VERSION 5.8 ;
BUSBITCHARS "[]" ;
DIVIDERCHAR "/" ;
UNITS
    DATABASE MICRONS 1000 ;
END UNITS

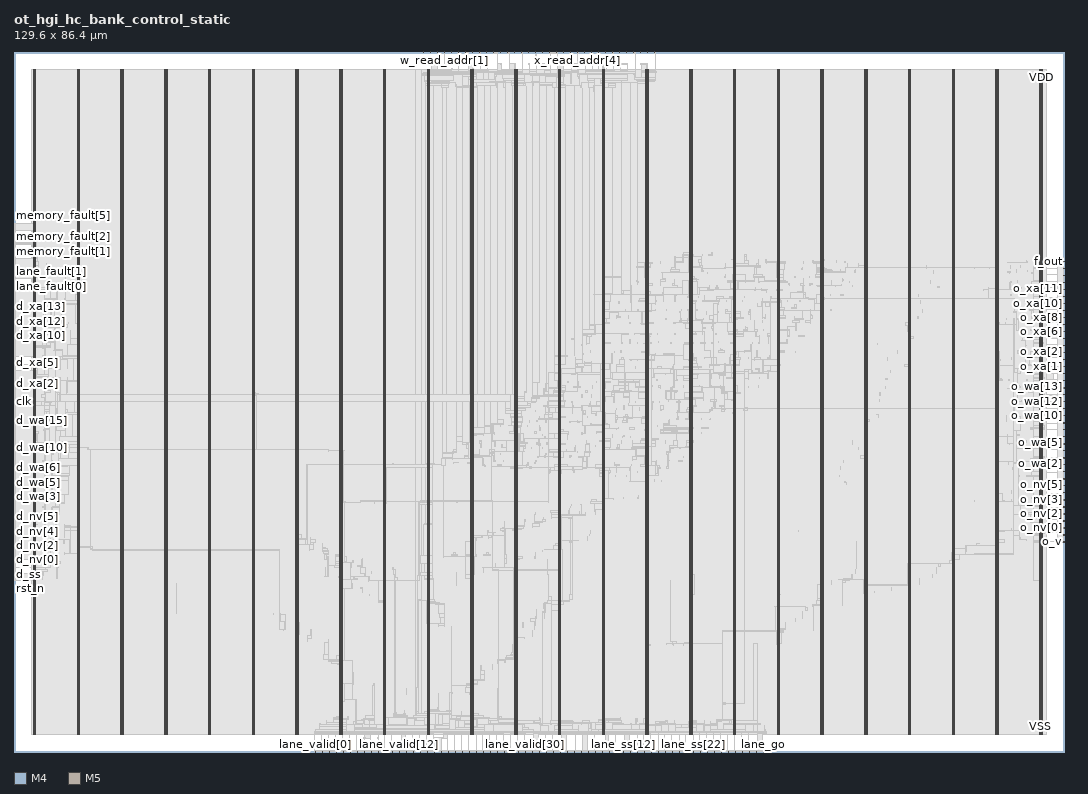
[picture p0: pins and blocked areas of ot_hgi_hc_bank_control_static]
MACRO ot_hgi_hc_bank_control_static
  FOREIGN ot_hgi_hc_bank_control_static 0 0 ;
  CLASS BLOCK ;
  SIZE 129.6 BY 86.4 ;
  PIN clk
    DIRECTION INPUT ;
    USE SIGNAL ;
    PORT
      LAYER M4 ;
        RECT  0 43.2 0.084 43.224 ;
    END
  END clk
  PIN d_nv[0]
    DIRECTION INPUT ;
    USE SIGNAL ;
    PORT
      LAYER M4 ;
        RECT  0 23.76 0.084 23.784 ;
    END
  END d_nv[0]
  PIN d_nv[1]
    DIRECTION INPUT ;
    USE SIGNAL ;
    PORT
      LAYER M4 ;
        RECT  0 24.624 0.084 24.648 ;
    END
  END d_nv[1]
  PIN d_nv[2]
    DIRECTION INPUT ;
    USE SIGNAL ;
    PORT
      LAYER M4 ;
        RECT  0 25.488 0.084 25.512 ;
    END
  END d_nv[2]
  PIN d_nv[3]
    DIRECTION INPUT ;
    USE SIGNAL ;
    PORT
      LAYER M4 ;
        RECT  0 26.352 0.084 26.376 ;
    END
  END d_nv[3]
  PIN d_nv[4]
    DIRECTION INPUT ;
    USE SIGNAL ;
    PORT
      LAYER M4 ;
        RECT  0 27.216 0.084 27.24 ;
    END
  END d_nv[4]
  PIN d_nv[5]
    DIRECTION INPUT ;
    USE SIGNAL ;
    PORT
      LAYER M4 ;
        RECT  0 28.08 0.084 28.104 ;
    END
  END d_nv[5]
  PIN d_ss
    DIRECTION INPUT ;
    USE SIGNAL ;
    PORT
      LAYER M4 ;
        RECT  0 22.896 0.084 22.92 ;
    END
  END d_ss
  PIN d_v
    DIRECTION INPUT ;
    USE SIGNAL ;
    PORT
      LAYER M4 ;
        RECT  0 22.032 0.084 22.056 ;
    END
  END d_v
  PIN d_wa[0]
    DIRECTION INPUT ;
    USE SIGNAL ;
    PORT
      LAYER M4 ;
        RECT  0 28.944 0.084 28.968 ;
    END
  END d_wa[0]
  PIN d_wa[10]
    DIRECTION INPUT ;
    USE SIGNAL ;
    PORT
      LAYER M4 ;
        RECT  0 37.584 0.084 37.608 ;
    END
  END d_wa[10]
  PIN d_wa[11]
    DIRECTION INPUT ;
    USE SIGNAL ;
    PORT
      LAYER M4 ;
        RECT  0 38.448 0.084 38.472 ;
    END
  END d_wa[11]
  PIN d_wa[12]
    DIRECTION INPUT ;
    USE SIGNAL ;
    PORT
      LAYER M4 ;
        RECT  0 39.312 0.084 39.336 ;
    END
  END d_wa[12]
  PIN d_wa[13]
    DIRECTION INPUT ;
    USE SIGNAL ;
    PORT
      LAYER M4 ;
        RECT  0 40.176 0.084 40.2 ;
    END
  END d_wa[13]
  PIN d_wa[14]
    DIRECTION INPUT ;
    USE SIGNAL ;
    PORT
      LAYER M4 ;
        RECT  0 41.04 0.084 41.064 ;
    END
  END d_wa[14]
  PIN d_wa[15]
    DIRECTION INPUT ;
    USE SIGNAL ;
    PORT
      LAYER M4 ;
        RECT  0 41.904 0.084 41.928 ;
    END
  END d_wa[15]
  PIN d_wa[1]
    DIRECTION INPUT ;
    USE SIGNAL ;
    PORT
      LAYER M4 ;
        RECT  0 29.808 0.084 29.832 ;
    END
  END d_wa[1]
  PIN d_wa[2]
    DIRECTION INPUT ;
    USE SIGNAL ;
    PORT
      LAYER M4 ;
        RECT  0 30.672 0.084 30.696 ;
    END
  END d_wa[2]
  PIN d_wa[3]
    DIRECTION INPUT ;
    USE SIGNAL ;
    PORT
      LAYER M4 ;
        RECT  0 31.536 0.084 31.56 ;
    END
  END d_wa[3]
  PIN d_wa[4]
    DIRECTION INPUT ;
    USE SIGNAL ;
    PORT
      LAYER M4 ;
        RECT  0 32.4 0.084 32.424 ;
    END
  END d_wa[4]
  PIN d_wa[5]
    DIRECTION INPUT ;
    USE SIGNAL ;
    PORT
      LAYER M4 ;
        RECT  0 33.264 0.084 33.288 ;
    END
  END d_wa[5]
  PIN d_wa[6]
    DIRECTION INPUT ;
    USE SIGNAL ;
    PORT
      LAYER M4 ;
        RECT  0 34.128 0.084 34.152 ;
    END
  END d_wa[6]
  PIN d_wa[7]
    DIRECTION INPUT ;
    USE SIGNAL ;
    PORT
      LAYER M4 ;
        RECT  0 34.992 0.084 35.016 ;
    END
  END d_wa[7]
  PIN d_wa[8]
    DIRECTION INPUT ;
    USE SIGNAL ;
    PORT
      LAYER M4 ;
        RECT  0 35.856 0.084 35.88 ;
    END
  END d_wa[8]
  PIN d_wa[9]
    DIRECTION INPUT ;
    USE SIGNAL ;
    PORT
      LAYER M4 ;
        RECT  0 36.72 0.084 36.744 ;
    END
  END d_wa[9]
  PIN d_xa[0]
    DIRECTION INPUT ;
    USE SIGNAL ;
    PORT
      LAYER M4 ;
        RECT  0 42.768 0.084 42.792 ;
    END
  END d_xa[0]
  PIN d_xa[10]
    DIRECTION INPUT ;
    USE SIGNAL ;
    PORT
      LAYER M4 ;
        RECT  0 51.408 0.084 51.432 ;
    END
  END d_xa[10]
  PIN d_xa[11]
    DIRECTION INPUT ;
    USE SIGNAL ;
    PORT
      LAYER M4 ;
        RECT  0 52.272 0.084 52.296 ;
    END
  END d_xa[11]
  PIN d_xa[12]
    DIRECTION INPUT ;
    USE SIGNAL ;
    PORT
      LAYER M4 ;
        RECT  0 53.136 0.084 53.16 ;
    END
  END d_xa[12]
  PIN d_xa[13]
    DIRECTION INPUT ;
    USE SIGNAL ;
    PORT
      LAYER M4 ;
        RECT  0 54 0.084 54.024 ;
    END
  END d_xa[13]
  PIN d_xa[14]
    DIRECTION INPUT ;
    USE SIGNAL ;
    PORT
      LAYER M4 ;
        RECT  0 54.864 0.084 54.888 ;
    END
  END d_xa[14]
  PIN d_xa[15]
    DIRECTION INPUT ;
    USE SIGNAL ;
    PORT
      LAYER M4 ;
        RECT  0 55.728 0.084 55.752 ;
    END
  END d_xa[15]
  PIN d_xa[1]
    DIRECTION INPUT ;
    USE SIGNAL ;
    PORT
      LAYER M4 ;
        RECT  0 43.632 0.084 43.656 ;
    END
  END d_xa[1]
  PIN d_xa[2]
    DIRECTION INPUT ;
    USE SIGNAL ;
    PORT
      LAYER M4 ;
        RECT  0 44.496 0.084 44.52 ;
    END
  END d_xa[2]
  PIN d_xa[3]
    DIRECTION INPUT ;
    USE SIGNAL ;
    PORT
      LAYER M4 ;
        RECT  0 45.36 0.084 45.384 ;
    END
  END d_xa[3]
  PIN d_xa[4]
    DIRECTION INPUT ;
    USE SIGNAL ;
    PORT
      LAYER M4 ;
        RECT  0 46.224 0.084 46.248 ;
    END
  END d_xa[4]
  PIN d_xa[5]
    DIRECTION INPUT ;
    USE SIGNAL ;
    PORT
      LAYER M4 ;
        RECT  0 47.088 0.084 47.112 ;
    END
  END d_xa[5]
  PIN d_xa[6]
    DIRECTION INPUT ;
    USE SIGNAL ;
    PORT
      LAYER M4 ;
        RECT  0 47.952 0.084 47.976 ;
    END
  END d_xa[6]
  PIN d_xa[7]
    DIRECTION INPUT ;
    USE SIGNAL ;
    PORT
      LAYER M4 ;
        RECT  0 48.816 0.084 48.84 ;
    END
  END d_xa[7]
  PIN d_xa[8]
    DIRECTION INPUT ;
    USE SIGNAL ;
    PORT
      LAYER M4 ;
        RECT  0 49.68 0.084 49.704 ;
    END
  END d_xa[8]
  PIN d_xa[9]
    DIRECTION INPUT ;
    USE SIGNAL ;
    PORT
      LAYER M4 ;
        RECT  0 50.544 0.084 50.568 ;
    END
  END d_xa[9]
  PIN f_in
    DIRECTION INPUT ;
    USE SIGNAL ;
    PORT
      LAYER M4 ;
        RECT  0 56.592 0.084 56.616 ;
    END
  END f_in
  PIN f_out
    DIRECTION OUTPUT ;
    USE SIGNAL ;
    PORT
      LAYER M4 ;
        RECT  129.516 60.48 129.6 60.504 ;
    END
  END f_out
  PIN lane_fault[0]
    DIRECTION INPUT ;
    USE SIGNAL ;
    PORT
      LAYER M4 ;
        RECT  0 57.456 0.084 57.48 ;
    END
  END lane_fault[0]
  PIN lane_fault[1]
    DIRECTION INPUT ;
    USE SIGNAL ;
    PORT
      LAYER M4 ;
        RECT  0 58.32 0.084 58.344 ;
    END
  END lane_fault[1]
  PIN lane_fault[2]
    DIRECTION INPUT ;
    USE SIGNAL ;
    PORT
      LAYER M4 ;
        RECT  0 59.184 0.084 59.208 ;
    END
  END lane_fault[2]
  PIN lane_fault[3]
    DIRECTION INPUT ;
    USE SIGNAL ;
    PORT
      LAYER M4 ;
        RECT  0 60.048 0.084 60.072 ;
    END
  END lane_fault[3]
  PIN lane_go
    DIRECTION OUTPUT ;
    USE SIGNAL ;
    PORT
      LAYER M5 ;
        RECT  92.448 0 92.472 0.084 ;
    END
  END lane_go
  PIN lane_ss[0]
    DIRECTION OUTPUT ;
    USE SIGNAL ;
    PORT
      LAYER M5 ;
        RECT  64.8 0 64.824 0.084 ;
    END
  END lane_ss[0]
  PIN lane_ss[10]
    DIRECTION OUTPUT ;
    USE SIGNAL ;
    PORT
      LAYER M5 ;
        RECT  73.44 0 73.464 0.084 ;
    END
  END lane_ss[10]
  PIN lane_ss[11]
    DIRECTION OUTPUT ;
    USE SIGNAL ;
    PORT
      LAYER M5 ;
        RECT  74.304 0 74.328 0.084 ;
    END
  END lane_ss[11]
  PIN lane_ss[12]
    DIRECTION OUTPUT ;
    USE SIGNAL ;
    PORT
      LAYER M5 ;
        RECT  75.168 0 75.192 0.084 ;
    END
  END lane_ss[12]
  PIN lane_ss[13]
    DIRECTION OUTPUT ;
    USE SIGNAL ;
    PORT
      LAYER M5 ;
        RECT  76.032 0 76.056 0.084 ;
    END
  END lane_ss[13]
  PIN lane_ss[14]
    DIRECTION OUTPUT ;
    USE SIGNAL ;
    PORT
      LAYER M5 ;
        RECT  76.896 0 76.92 0.084 ;
    END
  END lane_ss[14]
  PIN lane_ss[15]
    DIRECTION OUTPUT ;
    USE SIGNAL ;
    PORT
      LAYER M5 ;
        RECT  77.76 0 77.784 0.084 ;
    END
  END lane_ss[15]
  PIN lane_ss[16]
    DIRECTION OUTPUT ;
    USE SIGNAL ;
    PORT
      LAYER M5 ;
        RECT  78.624 0 78.648 0.084 ;
    END
  END lane_ss[16]
  PIN lane_ss[17]
    DIRECTION OUTPUT ;
    USE SIGNAL ;
    PORT
      LAYER M5 ;
        RECT  79.488 0 79.512 0.084 ;
    END
  END lane_ss[17]
  PIN lane_ss[18]
    DIRECTION OUTPUT ;
    USE SIGNAL ;
    PORT
      LAYER M5 ;
        RECT  80.352 0 80.376 0.084 ;
    END
  END lane_ss[18]
  PIN lane_ss[19]
    DIRECTION OUTPUT ;
    USE SIGNAL ;
    PORT
      LAYER M5 ;
        RECT  81.216 0 81.24 0.084 ;
    END
  END lane_ss[19]
  PIN lane_ss[1]
    DIRECTION OUTPUT ;
    USE SIGNAL ;
    PORT
      LAYER M5 ;
        RECT  65.664 0 65.688 0.084 ;
    END
  END lane_ss[1]
  PIN lane_ss[20]
    DIRECTION OUTPUT ;
    USE SIGNAL ;
    PORT
      LAYER M5 ;
        RECT  82.08 0 82.104 0.084 ;
    END
  END lane_ss[20]
  PIN lane_ss[21]
    DIRECTION OUTPUT ;
    USE SIGNAL ;
    PORT
      LAYER M5 ;
        RECT  82.944 0 82.968 0.084 ;
    END
  END lane_ss[21]
  PIN lane_ss[22]
    DIRECTION OUTPUT ;
    USE SIGNAL ;
    PORT
      LAYER M5 ;
        RECT  83.808 0 83.832 0.084 ;
    END
  END lane_ss[22]
  PIN lane_ss[23]
    DIRECTION OUTPUT ;
    USE SIGNAL ;
    PORT
      LAYER M5 ;
        RECT  84.672 0 84.696 0.084 ;
    END
  END lane_ss[23]
  PIN lane_ss[24]
    DIRECTION OUTPUT ;
    USE SIGNAL ;
    PORT
      LAYER M5 ;
        RECT  85.536 0 85.56 0.084 ;
    END
  END lane_ss[24]
  PIN lane_ss[25]
    DIRECTION OUTPUT ;
    USE SIGNAL ;
    PORT
      LAYER M5 ;
        RECT  86.4 0 86.424 0.084 ;
    END
  END lane_ss[25]
  PIN lane_ss[26]
    DIRECTION OUTPUT ;
    USE SIGNAL ;
    PORT
      LAYER M5 ;
        RECT  87.264 0 87.288 0.084 ;
    END
  END lane_ss[26]
  PIN lane_ss[27]
    DIRECTION OUTPUT ;
    USE SIGNAL ;
    PORT
      LAYER M5 ;
        RECT  88.128 0 88.152 0.084 ;
    END
  END lane_ss[27]
  PIN lane_ss[28]
    DIRECTION OUTPUT ;
    USE SIGNAL ;
    PORT
      LAYER M5 ;
        RECT  88.992 0 89.016 0.084 ;
    END
  END lane_ss[28]
  PIN lane_ss[29]
    DIRECTION OUTPUT ;
    USE SIGNAL ;
    PORT
      LAYER M5 ;
        RECT  89.856 0 89.88 0.084 ;
    END
  END lane_ss[29]
  PIN lane_ss[2]
    DIRECTION OUTPUT ;
    USE SIGNAL ;
    PORT
      LAYER M5 ;
        RECT  66.528 0 66.552 0.084 ;
    END
  END lane_ss[2]
  PIN lane_ss[30]
    DIRECTION OUTPUT ;
    USE SIGNAL ;
    PORT
      LAYER M5 ;
        RECT  90.72 0 90.744 0.084 ;
    END
  END lane_ss[30]
  PIN lane_ss[31]
    DIRECTION OUTPUT ;
    USE SIGNAL ;
    PORT
      LAYER M5 ;
        RECT  91.584 0 91.608 0.084 ;
    END
  END lane_ss[31]
  PIN lane_ss[3]
    DIRECTION OUTPUT ;
    USE SIGNAL ;
    PORT
      LAYER M5 ;
        RECT  67.392 0 67.416 0.084 ;
    END
  END lane_ss[3]
  PIN lane_ss[4]
    DIRECTION OUTPUT ;
    USE SIGNAL ;
    PORT
      LAYER M5 ;
        RECT  68.256 0 68.28 0.084 ;
    END
  END lane_ss[4]
  PIN lane_ss[5]
    DIRECTION OUTPUT ;
    USE SIGNAL ;
    PORT
      LAYER M5 ;
        RECT  69.12 0 69.144 0.084 ;
    END
  END lane_ss[5]
  PIN lane_ss[6]
    DIRECTION OUTPUT ;
    USE SIGNAL ;
    PORT
      LAYER M5 ;
        RECT  69.984 0 70.008 0.084 ;
    END
  END lane_ss[6]
  PIN lane_ss[7]
    DIRECTION OUTPUT ;
    USE SIGNAL ;
    PORT
      LAYER M5 ;
        RECT  70.848 0 70.872 0.084 ;
    END
  END lane_ss[7]
  PIN lane_ss[8]
    DIRECTION OUTPUT ;
    USE SIGNAL ;
    PORT
      LAYER M5 ;
        RECT  71.712 0 71.736 0.084 ;
    END
  END lane_ss[8]
  PIN lane_ss[9]
    DIRECTION OUTPUT ;
    USE SIGNAL ;
    PORT
      LAYER M5 ;
        RECT  72.576 0 72.6 0.084 ;
    END
  END lane_ss[9]
  PIN lane_valid[0]
    DIRECTION OUTPUT ;
    USE SIGNAL ;
    PORT
      LAYER M5 ;
        RECT  37.152 0 37.176 0.084 ;
    END
  END lane_valid[0]
  PIN lane_valid[10]
    DIRECTION OUTPUT ;
    USE SIGNAL ;
    PORT
      LAYER M5 ;
        RECT  45.792 0 45.816 0.084 ;
    END
  END lane_valid[10]
  PIN lane_valid[11]
    DIRECTION OUTPUT ;
    USE SIGNAL ;
    PORT
      LAYER M5 ;
        RECT  46.656 0 46.68 0.084 ;
    END
  END lane_valid[11]
  PIN lane_valid[12]
    DIRECTION OUTPUT ;
    USE SIGNAL ;
    PORT
      LAYER M5 ;
        RECT  47.52 0 47.544 0.084 ;
    END
  END lane_valid[12]
  PIN lane_valid[13]
    DIRECTION OUTPUT ;
    USE SIGNAL ;
    PORT
      LAYER M5 ;
        RECT  48.384 0 48.408 0.084 ;
    END
  END lane_valid[13]
  PIN lane_valid[14]
    DIRECTION OUTPUT ;
    USE SIGNAL ;
    PORT
      LAYER M5 ;
        RECT  49.248 0 49.272 0.084 ;
    END
  END lane_valid[14]
  PIN lane_valid[15]
    DIRECTION OUTPUT ;
    USE SIGNAL ;
    PORT
      LAYER M5 ;
        RECT  50.112 0 50.136 0.084 ;
    END
  END lane_valid[15]
  PIN lane_valid[16]
    DIRECTION OUTPUT ;
    USE SIGNAL ;
    PORT
      LAYER M5 ;
        RECT  50.976 0 51 0.084 ;
    END
  END lane_valid[16]
  PIN lane_valid[17]
    DIRECTION OUTPUT ;
    USE SIGNAL ;
    PORT
      LAYER M5 ;
        RECT  51.84 0 51.864 0.084 ;
    END
  END lane_valid[17]
  PIN lane_valid[18]
    DIRECTION OUTPUT ;
    USE SIGNAL ;
    PORT
      LAYER M5 ;
        RECT  52.704 0 52.728 0.084 ;
    END
  END lane_valid[18]
  PIN lane_valid[19]
    DIRECTION OUTPUT ;
    USE SIGNAL ;
    PORT
      LAYER M5 ;
        RECT  53.568 0 53.592 0.084 ;
    END
  END lane_valid[19]
  PIN lane_valid[1]
    DIRECTION OUTPUT ;
    USE SIGNAL ;
    PORT
      LAYER M5 ;
        RECT  38.016 0 38.04 0.084 ;
    END
  END lane_valid[1]
  PIN lane_valid[20]
    DIRECTION OUTPUT ;
    USE SIGNAL ;
    PORT
      LAYER M5 ;
        RECT  54.432 0 54.456 0.084 ;
    END
  END lane_valid[20]
  PIN lane_valid[21]
    DIRECTION OUTPUT ;
    USE SIGNAL ;
    PORT
      LAYER M5 ;
        RECT  55.296 0 55.32 0.084 ;
    END
  END lane_valid[21]
  PIN lane_valid[22]
    DIRECTION OUTPUT ;
    USE SIGNAL ;
    PORT
      LAYER M5 ;
        RECT  56.16 0 56.184 0.084 ;
    END
  END lane_valid[22]
  PIN lane_valid[23]
    DIRECTION OUTPUT ;
    USE SIGNAL ;
    PORT
      LAYER M5 ;
        RECT  57.024 0 57.048 0.084 ;
    END
  END lane_valid[23]
  PIN lane_valid[24]
    DIRECTION OUTPUT ;
    USE SIGNAL ;
    PORT
      LAYER M5 ;
        RECT  57.888 0 57.912 0.084 ;
    END
  END lane_valid[24]
  PIN lane_valid[25]
    DIRECTION OUTPUT ;
    USE SIGNAL ;
    PORT
      LAYER M5 ;
        RECT  58.752 0 58.776 0.084 ;
    END
  END lane_valid[25]
  PIN lane_valid[26]
    DIRECTION OUTPUT ;
    USE SIGNAL ;
    PORT
      LAYER M5 ;
        RECT  59.616 0 59.64 0.084 ;
    END
  END lane_valid[26]
  PIN lane_valid[27]
    DIRECTION OUTPUT ;
    USE SIGNAL ;
    PORT
      LAYER M5 ;
        RECT  60.48 0 60.504 0.084 ;
    END
  END lane_valid[27]
  PIN lane_valid[28]
    DIRECTION OUTPUT ;
    USE SIGNAL ;
    PORT
      LAYER M5 ;
        RECT  61.344 0 61.368 0.084 ;
    END
  END lane_valid[28]
  PIN lane_valid[29]
    DIRECTION OUTPUT ;
    USE SIGNAL ;
    PORT
      LAYER M5 ;
        RECT  62.208 0 62.232 0.084 ;
    END
  END lane_valid[29]
  PIN lane_valid[2]
    DIRECTION OUTPUT ;
    USE SIGNAL ;
    PORT
      LAYER M5 ;
        RECT  38.88 0 38.904 0.084 ;
    END
  END lane_valid[2]
  PIN lane_valid[30]
    DIRECTION OUTPUT ;
    USE SIGNAL ;
    PORT
      LAYER M5 ;
        RECT  63.072 0 63.096 0.084 ;
    END
  END lane_valid[30]
  PIN lane_valid[31]
    DIRECTION OUTPUT ;
    USE SIGNAL ;
    PORT
      LAYER M5 ;
        RECT  63.936 0 63.96 0.084 ;
    END
  END lane_valid[31]
  PIN lane_valid[3]
    DIRECTION OUTPUT ;
    USE SIGNAL ;
    PORT
      LAYER M5 ;
        RECT  39.744 0 39.768 0.084 ;
    END
  END lane_valid[3]
  PIN lane_valid[4]
    DIRECTION OUTPUT ;
    USE SIGNAL ;
    PORT
      LAYER M5 ;
        RECT  40.608 0 40.632 0.084 ;
    END
  END lane_valid[4]
  PIN lane_valid[5]
    DIRECTION OUTPUT ;
    USE SIGNAL ;
    PORT
      LAYER M5 ;
        RECT  41.472 0 41.496 0.084 ;
    END
  END lane_valid[5]
  PIN lane_valid[6]
    DIRECTION OUTPUT ;
    USE SIGNAL ;
    PORT
      LAYER M5 ;
        RECT  42.336 0 42.36 0.084 ;
    END
  END lane_valid[6]
  PIN lane_valid[7]
    DIRECTION OUTPUT ;
    USE SIGNAL ;
    PORT
      LAYER M5 ;
        RECT  43.2 0 43.224 0.084 ;
    END
  END lane_valid[7]
  PIN lane_valid[8]
    DIRECTION OUTPUT ;
    USE SIGNAL ;
    PORT
      LAYER M5 ;
        RECT  44.064 0 44.088 0.084 ;
    END
  END lane_valid[8]
  PIN lane_valid[9]
    DIRECTION OUTPUT ;
    USE SIGNAL ;
    PORT
      LAYER M5 ;
        RECT  44.928 0 44.952 0.084 ;
    END
  END lane_valid[9]
  PIN memory_fault[0]
    DIRECTION INPUT ;
    USE SIGNAL ;
    PORT
      LAYER M4 ;
        RECT  0 60.912 0.084 60.936 ;
    END
  END memory_fault[0]
  PIN memory_fault[1]
    DIRECTION INPUT ;
    USE SIGNAL ;
    PORT
      LAYER M4 ;
        RECT  0 61.776 0.084 61.8 ;
    END
  END memory_fault[1]
  PIN memory_fault[2]
    DIRECTION INPUT ;
    USE SIGNAL ;
    PORT
      LAYER M4 ;
        RECT  0 62.64 0.084 62.664 ;
    END
  END memory_fault[2]
  PIN memory_fault[3]
    DIRECTION INPUT ;
    USE SIGNAL ;
    PORT
      LAYER M4 ;
        RECT  0 63.504 0.084 63.528 ;
    END
  END memory_fault[3]
  PIN memory_fault[4]
    DIRECTION INPUT ;
    USE SIGNAL ;
    PORT
      LAYER M4 ;
        RECT  0 64.368 0.084 64.392 ;
    END
  END memory_fault[4]
  PIN memory_fault[5]
    DIRECTION INPUT ;
    USE SIGNAL ;
    PORT
      LAYER M4 ;
        RECT  0 65.232 0.084 65.256 ;
    END
  END memory_fault[5]
  PIN o_nv[0]
    DIRECTION OUTPUT ;
    USE SIGNAL ;
    PORT
      LAYER M4 ;
        RECT  129.516 27.648 129.6 27.672 ;
    END
  END o_nv[0]
  PIN o_nv[1]
    DIRECTION OUTPUT ;
    USE SIGNAL ;
    PORT
      LAYER M4 ;
        RECT  129.516 28.512 129.6 28.536 ;
    END
  END o_nv[1]
  PIN o_nv[2]
    DIRECTION OUTPUT ;
    USE SIGNAL ;
    PORT
      LAYER M4 ;
        RECT  129.516 29.376 129.6 29.4 ;
    END
  END o_nv[2]
  PIN o_nv[3]
    DIRECTION OUTPUT ;
    USE SIGNAL ;
    PORT
      LAYER M4 ;
        RECT  129.516 30.24 129.6 30.264 ;
    END
  END o_nv[3]
  PIN o_nv[4]
    DIRECTION OUTPUT ;
    USE SIGNAL ;
    PORT
      LAYER M4 ;
        RECT  129.516 31.104 129.6 31.128 ;
    END
  END o_nv[4]
  PIN o_nv[5]
    DIRECTION OUTPUT ;
    USE SIGNAL ;
    PORT
      LAYER M4 ;
        RECT  129.516 31.968 129.6 31.992 ;
    END
  END o_nv[5]
  PIN o_ss
    DIRECTION OUTPUT ;
    USE SIGNAL ;
    PORT
      LAYER M4 ;
        RECT  129.516 26.784 129.6 26.808 ;
    END
  END o_ss
  PIN o_v
    DIRECTION OUTPUT ;
    USE SIGNAL ;
    PORT
      LAYER M4 ;
        RECT  129.516 25.92 129.6 25.944 ;
    END
  END o_v
  PIN o_wa[0]
    DIRECTION OUTPUT ;
    USE SIGNAL ;
    PORT
      LAYER M4 ;
        RECT  129.516 32.832 129.6 32.856 ;
    END
  END o_wa[0]
  PIN o_wa[10]
    DIRECTION OUTPUT ;
    USE SIGNAL ;
    PORT
      LAYER M4 ;
        RECT  129.516 41.472 129.6 41.496 ;
    END
  END o_wa[10]
  PIN o_wa[11]
    DIRECTION OUTPUT ;
    USE SIGNAL ;
    PORT
      LAYER M4 ;
        RECT  129.516 42.336 129.6 42.36 ;
    END
  END o_wa[11]
  PIN o_wa[12]
    DIRECTION OUTPUT ;
    USE SIGNAL ;
    PORT
      LAYER M4 ;
        RECT  129.516 43.2 129.6 43.224 ;
    END
  END o_wa[12]
  PIN o_wa[13]
    DIRECTION OUTPUT ;
    USE SIGNAL ;
    PORT
      LAYER M4 ;
        RECT  129.516 44.064 129.6 44.088 ;
    END
  END o_wa[13]
  PIN o_wa[14]
    DIRECTION OUTPUT ;
    USE SIGNAL ;
    PORT
      LAYER M4 ;
        RECT  129.516 44.928 129.6 44.952 ;
    END
  END o_wa[14]
  PIN o_wa[15]
    DIRECTION OUTPUT ;
    USE SIGNAL ;
    PORT
      LAYER M4 ;
        RECT  129.516 45.792 129.6 45.816 ;
    END
  END o_wa[15]
  PIN o_wa[1]
    DIRECTION OUTPUT ;
    USE SIGNAL ;
    PORT
      LAYER M4 ;
        RECT  129.516 33.696 129.6 33.72 ;
    END
  END o_wa[1]
  PIN o_wa[2]
    DIRECTION OUTPUT ;
    USE SIGNAL ;
    PORT
      LAYER M4 ;
        RECT  129.516 34.56 129.6 34.584 ;
    END
  END o_wa[2]
  PIN o_wa[3]
    DIRECTION OUTPUT ;
    USE SIGNAL ;
    PORT
      LAYER M4 ;
        RECT  129.516 35.424 129.6 35.448 ;
    END
  END o_wa[3]
  PIN o_wa[4]
    DIRECTION OUTPUT ;
    USE SIGNAL ;
    PORT
      LAYER M4 ;
        RECT  129.516 36.288 129.6 36.312 ;
    END
  END o_wa[4]
  PIN o_wa[5]
    DIRECTION OUTPUT ;
    USE SIGNAL ;
    PORT
      LAYER M4 ;
        RECT  129.516 37.152 129.6 37.176 ;
    END
  END o_wa[5]
  PIN o_wa[6]
    DIRECTION OUTPUT ;
    USE SIGNAL ;
    PORT
      LAYER M4 ;
        RECT  129.516 38.016 129.6 38.04 ;
    END
  END o_wa[6]
  PIN o_wa[7]
    DIRECTION OUTPUT ;
    USE SIGNAL ;
    PORT
      LAYER M4 ;
        RECT  129.516 38.88 129.6 38.904 ;
    END
  END o_wa[7]
  PIN o_wa[8]
    DIRECTION OUTPUT ;
    USE SIGNAL ;
    PORT
      LAYER M4 ;
        RECT  129.516 39.744 129.6 39.768 ;
    END
  END o_wa[8]
  PIN o_wa[9]
    DIRECTION OUTPUT ;
    USE SIGNAL ;
    PORT
      LAYER M4 ;
        RECT  129.516 40.608 129.6 40.632 ;
    END
  END o_wa[9]
  PIN o_xa[0]
    DIRECTION OUTPUT ;
    USE SIGNAL ;
    PORT
      LAYER M4 ;
        RECT  129.516 46.656 129.6 46.68 ;
    END
  END o_xa[0]
  PIN o_xa[10]
    DIRECTION OUTPUT ;
    USE SIGNAL ;
    PORT
      LAYER M4 ;
        RECT  129.516 55.296 129.6 55.32 ;
    END
  END o_xa[10]
  PIN o_xa[11]
    DIRECTION OUTPUT ;
    USE SIGNAL ;
    PORT
      LAYER M4 ;
        RECT  129.516 56.16 129.6 56.184 ;
    END
  END o_xa[11]
  PIN o_xa[12]
    DIRECTION OUTPUT ;
    USE SIGNAL ;
    PORT
      LAYER M4 ;
        RECT  129.516 57.024 129.6 57.048 ;
    END
  END o_xa[12]
  PIN o_xa[13]
    DIRECTION OUTPUT ;
    USE SIGNAL ;
    PORT
      LAYER M4 ;
        RECT  129.516 57.888 129.6 57.912 ;
    END
  END o_xa[13]
  PIN o_xa[14]
    DIRECTION OUTPUT ;
    USE SIGNAL ;
    PORT
      LAYER M4 ;
        RECT  129.516 58.752 129.6 58.776 ;
    END
  END o_xa[14]
  PIN o_xa[15]
    DIRECTION OUTPUT ;
    USE SIGNAL ;
    PORT
      LAYER M4 ;
        RECT  129.516 59.616 129.6 59.64 ;
    END
  END o_xa[15]
  PIN o_xa[1]
    DIRECTION OUTPUT ;
    USE SIGNAL ;
    PORT
      LAYER M4 ;
        RECT  129.516 47.52 129.6 47.544 ;
    END
  END o_xa[1]
  PIN o_xa[2]
    DIRECTION OUTPUT ;
    USE SIGNAL ;
    PORT
      LAYER M4 ;
        RECT  129.516 48.384 129.6 48.408 ;
    END
  END o_xa[2]
  PIN o_xa[3]
    DIRECTION OUTPUT ;
    USE SIGNAL ;
    PORT
      LAYER M4 ;
        RECT  129.516 49.248 129.6 49.272 ;
    END
  END o_xa[3]
  PIN o_xa[4]
    DIRECTION OUTPUT ;
    USE SIGNAL ;
    PORT
      LAYER M4 ;
        RECT  129.516 50.112 129.6 50.136 ;
    END
  END o_xa[4]
  PIN o_xa[5]
    DIRECTION OUTPUT ;
    USE SIGNAL ;
    PORT
      LAYER M4 ;
        RECT  129.516 50.976 129.6 51 ;
    END
  END o_xa[5]
  PIN o_xa[6]
    DIRECTION OUTPUT ;
    USE SIGNAL ;
    PORT
      LAYER M4 ;
        RECT  129.516 51.84 129.6 51.864 ;
    END
  END o_xa[6]
  PIN o_xa[7]
    DIRECTION OUTPUT ;
    USE SIGNAL ;
    PORT
      LAYER M4 ;
        RECT  129.516 52.704 129.6 52.728 ;
    END
  END o_xa[7]
  PIN o_xa[8]
    DIRECTION OUTPUT ;
    USE SIGNAL ;
    PORT
      LAYER M4 ;
        RECT  129.516 53.568 129.6 53.592 ;
    END
  END o_xa[8]
  PIN o_xa[9]
    DIRECTION OUTPUT ;
    USE SIGNAL ;
    PORT
      LAYER M4 ;
        RECT  129.516 54.432 129.6 54.456 ;
    END
  END o_xa[9]
  PIN rst_n
    DIRECTION INPUT ;
    USE SIGNAL ;
    PORT
      LAYER M4 ;
        RECT  0 21.168 0.084 21.192 ;
    END
  END rst_n
  PIN w_read_addr[0]
    DIRECTION OUTPUT ;
    USE SIGNAL ;
    PORT
      LAYER M5 ;
        RECT  52.272 86.316 52.296 86.4 ;
    END
  END w_read_addr[0]
  PIN w_read_addr[10]
    DIRECTION OUTPUT ;
    USE SIGNAL ;
    PORT
      LAYER M5 ;
        RECT  60.912 86.316 60.936 86.4 ;
    END
  END w_read_addr[10]
  PIN w_read_addr[11]
    DIRECTION OUTPUT ;
    USE SIGNAL ;
    PORT
      LAYER M5 ;
        RECT  61.776 86.316 61.8 86.4 ;
    END
  END w_read_addr[11]
  PIN w_read_addr[12]
    DIRECTION OUTPUT ;
    USE SIGNAL ;
    PORT
      LAYER M5 ;
        RECT  62.64 86.316 62.664 86.4 ;
    END
  END w_read_addr[12]
  PIN w_read_addr[13]
    DIRECTION OUTPUT ;
    USE SIGNAL ;
    PORT
      LAYER M5 ;
        RECT  63.504 86.316 63.528 86.4 ;
    END
  END w_read_addr[13]
  PIN w_read_addr[14]
    DIRECTION OUTPUT ;
    USE SIGNAL ;
    PORT
      LAYER M5 ;
        RECT  64.368 86.316 64.392 86.4 ;
    END
  END w_read_addr[14]
  PIN w_read_addr[15]
    DIRECTION OUTPUT ;
    USE SIGNAL ;
    PORT
      LAYER M5 ;
        RECT  65.232 86.316 65.256 86.4 ;
    END
  END w_read_addr[15]
  PIN w_read_addr[1]
    DIRECTION OUTPUT ;
    USE SIGNAL ;
    PORT
      LAYER M5 ;
        RECT  53.136 86.316 53.16 86.4 ;
    END
  END w_read_addr[1]
  PIN w_read_addr[2]
    DIRECTION OUTPUT ;
    USE SIGNAL ;
    PORT
      LAYER M5 ;
        RECT  54 86.316 54.024 86.4 ;
    END
  END w_read_addr[2]
  PIN w_read_addr[3]
    DIRECTION OUTPUT ;
    USE SIGNAL ;
    PORT
      LAYER M5 ;
        RECT  54.864 86.316 54.888 86.4 ;
    END
  END w_read_addr[3]
  PIN w_read_addr[4]
    DIRECTION OUTPUT ;
    USE SIGNAL ;
    PORT
      LAYER M5 ;
        RECT  55.728 86.316 55.752 86.4 ;
    END
  END w_read_addr[4]
  PIN w_read_addr[5]
    DIRECTION OUTPUT ;
    USE SIGNAL ;
    PORT
      LAYER M5 ;
        RECT  56.592 86.316 56.616 86.4 ;
    END
  END w_read_addr[5]
  PIN w_read_addr[6]
    DIRECTION OUTPUT ;
    USE SIGNAL ;
    PORT
      LAYER M5 ;
        RECT  57.456 86.316 57.48 86.4 ;
    END
  END w_read_addr[6]
  PIN w_read_addr[7]
    DIRECTION OUTPUT ;
    USE SIGNAL ;
    PORT
      LAYER M5 ;
        RECT  58.32 86.316 58.344 86.4 ;
    END
  END w_read_addr[7]
  PIN w_read_addr[8]
    DIRECTION OUTPUT ;
    USE SIGNAL ;
    PORT
      LAYER M5 ;
        RECT  59.184 86.316 59.208 86.4 ;
    END
  END w_read_addr[8]
  PIN w_read_addr[9]
    DIRECTION OUTPUT ;
    USE SIGNAL ;
    PORT
      LAYER M5 ;
        RECT  60.048 86.316 60.072 86.4 ;
    END
  END w_read_addr[9]
  PIN w_read_v
    DIRECTION OUTPUT ;
    USE SIGNAL ;
    PORT
      LAYER M5 ;
        RECT  50.544 86.316 50.568 86.4 ;
    END
  END w_read_v
  PIN x_read_addr[0]
    DIRECTION OUTPUT ;
    USE SIGNAL ;
    PORT
      LAYER M5 ;
        RECT  66.096 86.316 66.12 86.4 ;
    END
  END x_read_addr[0]
  PIN x_read_addr[10]
    DIRECTION OUTPUT ;
    USE SIGNAL ;
    PORT
      LAYER M5 ;
        RECT  74.736 86.316 74.76 86.4 ;
    END
  END x_read_addr[10]
  PIN x_read_addr[11]
    DIRECTION OUTPUT ;
    USE SIGNAL ;
    PORT
      LAYER M5 ;
        RECT  75.6 86.316 75.624 86.4 ;
    END
  END x_read_addr[11]
  PIN x_read_addr[12]
    DIRECTION OUTPUT ;
    USE SIGNAL ;
    PORT
      LAYER M5 ;
        RECT  76.464 86.316 76.488 86.4 ;
    END
  END x_read_addr[12]
  PIN x_read_addr[13]
    DIRECTION OUTPUT ;
    USE SIGNAL ;
    PORT
      LAYER M5 ;
        RECT  77.328 86.316 77.352 86.4 ;
    END
  END x_read_addr[13]
  PIN x_read_addr[14]
    DIRECTION OUTPUT ;
    USE SIGNAL ;
    PORT
      LAYER M5 ;
        RECT  78.192 86.316 78.216 86.4 ;
    END
  END x_read_addr[14]
  PIN x_read_addr[15]
    DIRECTION OUTPUT ;
    USE SIGNAL ;
    PORT
      LAYER M5 ;
        RECT  79.056 86.316 79.08 86.4 ;
    END
  END x_read_addr[15]
  PIN x_read_addr[1]
    DIRECTION OUTPUT ;
    USE SIGNAL ;
    PORT
      LAYER M5 ;
        RECT  66.96 86.316 66.984 86.4 ;
    END
  END x_read_addr[1]
  PIN x_read_addr[2]
    DIRECTION OUTPUT ;
    USE SIGNAL ;
    PORT
      LAYER M5 ;
        RECT  67.824 86.316 67.848 86.4 ;
    END
  END x_read_addr[2]
  PIN x_read_addr[3]
    DIRECTION OUTPUT ;
    USE SIGNAL ;
    PORT
      LAYER M5 ;
        RECT  68.688 86.316 68.712 86.4 ;
    END
  END x_read_addr[3]
  PIN x_read_addr[4]
    DIRECTION OUTPUT ;
    USE SIGNAL ;
    PORT
      LAYER M5 ;
        RECT  69.552 86.316 69.576 86.4 ;
    END
  END x_read_addr[4]
  PIN x_read_addr[5]
    DIRECTION OUTPUT ;
    USE SIGNAL ;
    PORT
      LAYER M5 ;
        RECT  70.416 86.316 70.44 86.4 ;
    END
  END x_read_addr[5]
  PIN x_read_addr[6]
    DIRECTION OUTPUT ;
    USE SIGNAL ;
    PORT
      LAYER M5 ;
        RECT  71.28 86.316 71.304 86.4 ;
    END
  END x_read_addr[6]
  PIN x_read_addr[7]
    DIRECTION OUTPUT ;
    USE SIGNAL ;
    PORT
      LAYER M5 ;
        RECT  72.144 86.316 72.168 86.4 ;
    END
  END x_read_addr[7]
  PIN x_read_addr[8]
    DIRECTION OUTPUT ;
    USE SIGNAL ;
    PORT
      LAYER M5 ;
        RECT  73.008 86.316 73.032 86.4 ;
    END
  END x_read_addr[8]
  PIN x_read_addr[9]
    DIRECTION OUTPUT ;
    USE SIGNAL ;
    PORT
      LAYER M5 ;
        RECT  73.872 86.316 73.896 86.4 ;
    END
  END x_read_addr[9]
  PIN x_read_v
    DIRECTION OUTPUT ;
    USE SIGNAL ;
    PORT
      LAYER M5 ;
        RECT  51.408 86.316 51.432 86.4 ;
    END
  END x_read_v
  PIN VDD
    DIRECTION INOUT ;
    USE POWER ;
    PORT
      LAYER M5 ;
        RECT  126.792 2.151 126.912 84.249 ;
        RECT  121.392 2.151 121.512 84.249 ;
        RECT  115.992 2.151 116.112 84.249 ;
        RECT  110.592 2.151 110.712 84.249 ;
        RECT  105.192 2.151 105.312 84.249 ;
        RECT  99.792 2.151 99.912 84.249 ;
        RECT  94.392 2.151 94.512 84.249 ;
        RECT  88.992 2.151 89.112 84.249 ;
        RECT  83.592 2.151 83.712 84.249 ;
        RECT  78.192 2.151 78.312 84.249 ;
        RECT  72.792 2.151 72.912 84.249 ;
        RECT  67.392 2.151 67.512 84.249 ;
        RECT  61.992 2.151 62.112 84.249 ;
        RECT  56.592 2.151 56.712 84.249 ;
        RECT  51.192 2.151 51.312 84.249 ;
        RECT  45.792 2.151 45.912 84.249 ;
        RECT  40.392 2.151 40.512 84.249 ;
        RECT  34.992 2.151 35.112 84.249 ;
        RECT  29.592 2.151 29.712 84.249 ;
        RECT  24.192 2.151 24.312 84.249 ;
        RECT  18.792 2.151 18.912 84.249 ;
        RECT  13.392 2.151 13.512 84.249 ;
        RECT  7.992 2.151 8.112 84.249 ;
        RECT  2.592 2.151 2.712 84.249 ;
    END
  END VDD
  PIN VSS
    DIRECTION INOUT ;
    USE GROUND ;
    PORT
      LAYER M5 ;
        RECT  126.6 2.137 126.72 84.263 ;
        RECT  121.2 2.137 121.32 84.263 ;
        RECT  115.8 2.137 115.92 84.263 ;
        RECT  110.4 2.137 110.52 84.263 ;
        RECT  105 2.137 105.12 84.263 ;
        RECT  99.6 2.137 99.72 84.263 ;
        RECT  94.2 2.137 94.32 84.263 ;
        RECT  88.8 2.137 88.92 84.263 ;
        RECT  83.4 2.137 83.52 84.263 ;
        RECT  78 2.137 78.12 84.263 ;
        RECT  72.6 2.137 72.72 84.263 ;
        RECT  67.2 2.137 67.32 84.263 ;
        RECT  61.8 2.137 61.92 84.263 ;
        RECT  56.4 2.137 56.52 84.263 ;
        RECT  51 2.137 51.12 84.263 ;
        RECT  45.6 2.137 45.72 84.263 ;
        RECT  40.2 2.137 40.32 84.263 ;
        RECT  34.8 2.137 34.92 84.263 ;
        RECT  29.4 2.137 29.52 84.263 ;
        RECT  24 2.137 24.12 84.263 ;
        RECT  18.6 2.137 18.72 84.263 ;
        RECT  13.2 2.137 13.32 84.263 ;
        RECT  7.8 2.137 7.92 84.263 ;
        RECT  2.4 2.137 2.52 84.263 ;
    END
  END VSS
  # OT_OBS_CLOSED layer=M5 d_um=1.536 added=58
  OBS
    LAYER RVTN ;
     RECT  2.16 2.16 127.44 2.295 ;
     RECT  2.16 2.565 127.44 2.835 ;
     RECT  2.16 3.105 127.44 3.375 ;
     RECT  2.16 3.645 127.44 3.915 ;
     RECT  2.16 4.185 127.44 4.455 ;
     RECT  2.16 4.725 127.44 4.995 ;
     RECT  2.16 5.265 127.44 5.535 ;
     RECT  2.16 5.805 127.44 6.075 ;
     RECT  2.16 6.345 127.44 6.615 ;
     RECT  2.16 6.885 127.44 7.155 ;
     RECT  2.16 7.425 127.44 7.695 ;
     RECT  2.16 7.965 127.44 8.235 ;
     RECT  2.16 8.505 127.44 8.775 ;
     RECT  2.16 9.045 127.44 9.315 ;
     RECT  2.16 9.585 127.44 9.855 ;
     RECT  2.16 10.125 127.44 10.395 ;
     RECT  2.16 10.665 127.44 10.935 ;
     RECT  2.16 11.205 127.44 11.475 ;
     RECT  2.16 11.745 127.44 12.015 ;
     RECT  2.16 12.285 127.44 12.555 ;
     RECT  2.16 12.825 127.44 13.095 ;
     RECT  2.16 13.365 127.44 13.635 ;
     RECT  2.16 13.905 127.44 14.175 ;
     RECT  2.16 14.445 127.44 14.715 ;
     RECT  2.16 14.985 127.44 15.255 ;
     RECT  2.16 15.525 127.44 15.795 ;
     RECT  2.16 16.065 127.44 16.335 ;
     RECT  2.16 16.605 127.44 16.875 ;
     RECT  2.16 17.145 127.44 17.415 ;
     RECT  2.16 17.685 127.44 17.955 ;
     RECT  2.16 18.225 127.44 18.495 ;
     RECT  2.16 18.765 127.44 19.035 ;
     RECT  2.16 19.305 127.44 19.575 ;
     RECT  2.16 19.845 127.44 20.115 ;
     RECT  2.16 20.385 127.44 20.655 ;
     RECT  2.16 20.925 127.44 21.195 ;
     RECT  2.16 21.465 127.44 21.735 ;
     RECT  2.16 22.005 127.44 22.275 ;
     RECT  2.16 22.545 127.44 22.815 ;
     RECT  2.16 23.085 127.44 23.355 ;
     RECT  2.16 23.625 127.44 23.895 ;
     RECT  2.16 24.165 127.44 24.435 ;
     RECT  2.16 24.705 127.44 24.975 ;
     RECT  2.16 25.245 127.44 25.515 ;
     RECT  2.16 25.785 127.44 26.055 ;
     RECT  2.16 26.325 127.44 26.595 ;
     RECT  2.16 26.865 127.44 27.135 ;
     RECT  2.16 27.405 127.44 27.675 ;
     RECT  2.16 27.945 127.44 28.215 ;
     RECT  2.16 28.485 127.44 28.755 ;
     RECT  2.16 29.025 127.44 29.295 ;
     RECT  2.16 29.565 127.44 29.835 ;
     RECT  2.16 30.105 127.44 30.375 ;
     RECT  2.16 30.645 127.44 30.915 ;
     RECT  2.16 31.185 127.44 31.455 ;
     RECT  2.16 31.725 127.44 31.995 ;
     RECT  2.16 32.265 127.44 32.535 ;
     RECT  2.16 32.805 127.44 33.075 ;
     RECT  2.16 33.345 127.44 33.615 ;
     RECT  2.16 33.885 127.44 34.155 ;
     RECT  2.16 34.425 127.44 34.695 ;
     RECT  2.16 34.965 127.44 35.235 ;
     RECT  2.16 35.505 127.44 35.775 ;
     RECT  2.16 36.045 127.44 36.315 ;
     RECT  2.16 36.585 127.44 36.855 ;
     RECT  2.16 37.125 127.44 37.395 ;
     RECT  2.16 37.665 127.44 37.935 ;
     RECT  2.16 38.205 127.44 38.475 ;
     RECT  2.16 38.745 127.44 39.015 ;
     RECT  2.16 39.285 127.44 39.555 ;
     RECT  2.16 39.825 127.44 40.095 ;
     RECT  2.16 40.365 127.44 40.635 ;
     RECT  2.16 40.905 127.44 41.175 ;
     RECT  2.16 41.445 127.44 41.715 ;
     RECT  2.16 41.985 127.44 42.255 ;
     RECT  2.16 42.525 127.44 42.795 ;
     RECT  2.16 43.065 127.44 43.335 ;
     RECT  2.16 43.605 127.44 43.875 ;
     RECT  2.16 44.145 127.44 44.415 ;
     RECT  2.16 44.685 127.44 44.955 ;
     RECT  2.16 45.225 127.44 45.495 ;
     RECT  2.16 45.765 127.44 46.035 ;
     RECT  2.16 46.305 127.44 46.575 ;
     RECT  2.16 46.845 127.44 47.115 ;
     RECT  2.16 47.385 127.44 47.655 ;
     RECT  2.16 47.925 127.44 48.195 ;
     RECT  2.16 48.465 127.44 48.735 ;
     RECT  2.16 49.005 127.44 49.275 ;
     RECT  2.16 49.545 127.44 49.815 ;
     RECT  2.16 50.085 127.44 50.355 ;
     RECT  2.16 50.625 127.44 50.895 ;
     RECT  2.16 51.165 127.44 51.435 ;
     RECT  2.16 51.705 127.44 51.975 ;
     RECT  2.16 52.245 127.44 52.515 ;
     RECT  2.16 52.785 127.44 53.055 ;
     RECT  2.16 53.325 127.44 53.595 ;
     RECT  2.16 53.865 127.44 54.135 ;
     RECT  2.16 54.405 127.44 54.675 ;
     RECT  2.16 54.945 127.44 55.215 ;
     RECT  2.16 55.485 127.44 55.755 ;
     RECT  2.16 56.025 127.44 56.295 ;
     RECT  2.16 56.565 127.44 56.835 ;
     RECT  2.16 57.105 127.44 57.375 ;
     RECT  2.16 57.645 127.44 57.915 ;
     RECT  2.16 58.185 127.44 58.455 ;
     RECT  2.16 58.725 127.44 58.995 ;
     RECT  2.16 59.265 127.44 59.535 ;
     RECT  2.16 59.805 127.44 60.075 ;
     RECT  2.16 60.345 127.44 60.615 ;
     RECT  2.16 60.885 127.44 61.155 ;
     RECT  2.16 61.425 127.44 61.695 ;
     RECT  2.16 61.965 127.44 62.235 ;
     RECT  2.16 62.505 127.44 62.775 ;
     RECT  2.16 63.045 127.44 63.315 ;
     RECT  2.16 63.585 127.44 63.855 ;
     RECT  2.16 64.125 127.44 64.395 ;
     RECT  2.16 64.665 127.44 64.935 ;
     RECT  2.16 65.205 127.44 65.475 ;
     RECT  2.16 65.745 127.44 66.015 ;
     RECT  2.16 66.285 127.44 66.555 ;
     RECT  2.16 66.825 127.44 67.095 ;
     RECT  2.16 67.365 127.44 67.635 ;
     RECT  2.16 67.905 127.44 68.175 ;
     RECT  2.16 68.445 127.44 68.715 ;
     RECT  2.16 68.985 127.44 69.255 ;
     RECT  2.16 69.525 127.44 69.795 ;
     RECT  2.16 70.065 127.44 70.335 ;
     RECT  2.16 70.605 127.44 70.875 ;
     RECT  2.16 71.145 127.44 71.415 ;
     RECT  2.16 71.685 127.44 71.955 ;
     RECT  2.16 72.225 127.44 72.495 ;
     RECT  2.16 72.765 127.44 73.035 ;
     RECT  2.16 73.305 127.44 73.575 ;
     RECT  2.16 73.845 127.44 74.115 ;
     RECT  2.16 74.385 127.44 74.655 ;
     RECT  2.16 74.925 127.44 75.195 ;
     RECT  2.16 75.465 127.44 75.735 ;
     RECT  2.16 76.005 127.44 76.275 ;
     RECT  2.16 76.545 127.44 76.815 ;
     RECT  2.16 77.085 127.44 77.355 ;
     RECT  2.16 77.625 127.44 77.895 ;
     RECT  2.16 78.165 127.44 78.435 ;
     RECT  2.16 78.705 127.44 78.975 ;
     RECT  2.16 79.245 127.44 79.515 ;
     RECT  2.16 79.785 127.44 80.055 ;
     RECT  2.16 80.325 127.44 80.595 ;
     RECT  2.16 80.865 127.44 81.135 ;
     RECT  2.16 81.405 127.44 81.675 ;
     RECT  2.16 81.945 127.44 82.215 ;
     RECT  2.16 82.485 127.44 82.755 ;
     RECT  2.16 83.025 127.44 83.295 ;
     RECT  2.16 83.565 127.44 83.835 ;
     RECT  2.16 84.105 127.44 84.24 ;
    LAYER RVTP ;
     RECT  2.16 2.295 127.44 2.565 ;
     RECT  2.16 2.835 127.44 3.105 ;
     RECT  2.16 3.375 127.44 3.645 ;
     RECT  2.16 3.915 127.44 4.185 ;
     RECT  2.16 4.455 127.44 4.725 ;
     RECT  2.16 4.995 127.44 5.265 ;
     RECT  2.16 5.535 127.44 5.805 ;
     RECT  2.16 6.075 127.44 6.345 ;
     RECT  2.16 6.615 127.44 6.885 ;
     RECT  2.16 7.155 127.44 7.425 ;
     RECT  2.16 7.695 127.44 7.965 ;
     RECT  2.16 8.235 127.44 8.505 ;
     RECT  2.16 8.775 127.44 9.045 ;
     RECT  2.16 9.315 127.44 9.585 ;
     RECT  2.16 9.855 127.44 10.125 ;
     RECT  2.16 10.395 127.44 10.665 ;
     RECT  2.16 10.935 127.44 11.205 ;
     RECT  2.16 11.475 127.44 11.745 ;
     RECT  2.16 12.015 127.44 12.285 ;
     RECT  2.16 12.555 127.44 12.825 ;
     RECT  2.16 13.095 127.44 13.365 ;
     RECT  2.16 13.635 127.44 13.905 ;
     RECT  2.16 14.175 127.44 14.445 ;
     RECT  2.16 14.715 127.44 14.985 ;
     RECT  2.16 15.255 127.44 15.525 ;
     RECT  2.16 15.795 127.44 16.065 ;
     RECT  2.16 16.335 127.44 16.605 ;
     RECT  2.16 16.875 127.44 17.145 ;
     RECT  2.16 17.415 127.44 17.685 ;
     RECT  2.16 17.955 127.44 18.225 ;
     RECT  2.16 18.495 127.44 18.765 ;
     RECT  2.16 19.035 127.44 19.305 ;
     RECT  2.16 19.575 127.44 19.845 ;
     RECT  2.16 20.115 127.44 20.385 ;
     RECT  2.16 20.655 127.44 20.925 ;
     RECT  2.16 21.195 127.44 21.465 ;
     RECT  2.16 21.735 127.44 22.005 ;
     RECT  2.16 22.275 127.44 22.545 ;
     RECT  2.16 22.815 127.44 23.085 ;
     RECT  2.16 23.355 127.44 23.625 ;
     RECT  2.16 23.895 127.44 24.165 ;
     RECT  2.16 24.435 127.44 24.705 ;
     RECT  2.16 24.975 127.44 25.245 ;
     RECT  2.16 25.515 127.44 25.785 ;
     RECT  2.16 26.055 127.44 26.325 ;
     RECT  2.16 26.595 127.44 26.865 ;
     RECT  2.16 27.135 127.44 27.405 ;
     RECT  2.16 27.675 127.44 27.945 ;
     RECT  2.16 28.215 127.44 28.485 ;
     RECT  2.16 28.755 127.44 29.025 ;
     RECT  2.16 29.295 127.44 29.565 ;
     RECT  2.16 29.835 127.44 30.105 ;
     RECT  2.16 30.375 127.44 30.645 ;
     RECT  2.16 30.915 127.44 31.185 ;
     RECT  2.16 31.455 127.44 31.725 ;
     RECT  2.16 31.995 127.44 32.265 ;
     RECT  2.16 32.535 127.44 32.805 ;
     RECT  2.16 33.075 127.44 33.345 ;
     RECT  2.16 33.615 127.44 33.885 ;
     RECT  2.16 34.155 127.44 34.425 ;
     RECT  2.16 34.695 127.44 34.965 ;
     RECT  2.16 35.235 127.44 35.505 ;
     RECT  2.16 35.775 127.44 36.045 ;
     RECT  2.16 36.315 127.44 36.585 ;
     RECT  2.16 36.855 127.44 37.125 ;
     RECT  2.16 37.395 127.44 37.665 ;
     RECT  2.16 37.935 127.44 38.205 ;
     RECT  2.16 38.475 127.44 38.745 ;
     RECT  2.16 39.015 127.44 39.285 ;
     RECT  2.16 39.555 127.44 39.825 ;
     RECT  2.16 40.095 127.44 40.365 ;
     RECT  2.16 40.635 127.44 40.905 ;
     RECT  2.16 41.175 127.44 41.445 ;
     RECT  2.16 41.715 127.44 41.985 ;
     RECT  2.16 42.255 127.44 42.525 ;
     RECT  2.16 42.795 127.44 43.065 ;
     RECT  2.16 43.335 127.44 43.605 ;
     RECT  2.16 43.875 127.44 44.145 ;
     RECT  2.16 44.415 127.44 44.685 ;
     RECT  2.16 44.955 127.44 45.225 ;
     RECT  2.16 45.495 127.44 45.765 ;
     RECT  2.16 46.035 127.44 46.305 ;
     RECT  2.16 46.575 127.44 46.845 ;
     RECT  2.16 47.115 127.44 47.385 ;
     RECT  2.16 47.655 127.44 47.925 ;
     RECT  2.16 48.195 127.44 48.465 ;
     RECT  2.16 48.735 127.44 49.005 ;
     RECT  2.16 49.275 127.44 49.545 ;
     RECT  2.16 49.815 127.44 50.085 ;
     RECT  2.16 50.355 127.44 50.625 ;
     RECT  2.16 50.895 127.44 51.165 ;
     RECT  2.16 51.435 127.44 51.705 ;
     RECT  2.16 51.975 127.44 52.245 ;
     RECT  2.16 52.515 127.44 52.785 ;
     RECT  2.16 53.055 127.44 53.325 ;
     RECT  2.16 53.595 127.44 53.865 ;
     RECT  2.16 54.135 127.44 54.405 ;
     RECT  2.16 54.675 127.44 54.945 ;
     RECT  2.16 55.215 127.44 55.485 ;
     RECT  2.16 55.755 127.44 56.025 ;
     RECT  2.16 56.295 127.44 56.565 ;
     RECT  2.16 56.835 127.44 57.105 ;
     RECT  2.16 57.375 127.44 57.645 ;
     RECT  2.16 57.915 127.44 58.185 ;
     RECT  2.16 58.455 127.44 58.725 ;
     RECT  2.16 58.995 127.44 59.265 ;
     RECT  2.16 59.535 127.44 59.805 ;
     RECT  2.16 60.075 127.44 60.345 ;
     RECT  2.16 60.615 127.44 60.885 ;
     RECT  2.16 61.155 127.44 61.425 ;
     RECT  2.16 61.695 127.44 61.965 ;
     RECT  2.16 62.235 127.44 62.505 ;
     RECT  2.16 62.775 127.44 63.045 ;
     RECT  2.16 63.315 127.44 63.585 ;
     RECT  2.16 63.855 127.44 64.125 ;
     RECT  2.16 64.395 127.44 64.665 ;
     RECT  2.16 64.935 127.44 65.205 ;
     RECT  2.16 65.475 127.44 65.745 ;
     RECT  2.16 66.015 127.44 66.285 ;
     RECT  2.16 66.555 127.44 66.825 ;
     RECT  2.16 67.095 127.44 67.365 ;
     RECT  2.16 67.635 127.44 67.905 ;
     RECT  2.16 68.175 127.44 68.445 ;
     RECT  2.16 68.715 127.44 68.985 ;
     RECT  2.16 69.255 127.44 69.525 ;
     RECT  2.16 69.795 127.44 70.065 ;
     RECT  2.16 70.335 127.44 70.605 ;
     RECT  2.16 70.875 127.44 71.145 ;
     RECT  2.16 71.415 127.44 71.685 ;
     RECT  2.16 71.955 127.44 72.225 ;
     RECT  2.16 72.495 127.44 72.765 ;
     RECT  2.16 73.035 127.44 73.305 ;
     RECT  2.16 73.575 127.44 73.845 ;
     RECT  2.16 74.115 127.44 74.385 ;
     RECT  2.16 74.655 127.44 74.925 ;
     RECT  2.16 75.195 127.44 75.465 ;
     RECT  2.16 75.735 127.44 76.005 ;
     RECT  2.16 76.275 127.44 76.545 ;
     RECT  2.16 76.815 127.44 77.085 ;
     RECT  2.16 77.355 127.44 77.625 ;
     RECT  2.16 77.895 127.44 78.165 ;
     RECT  2.16 78.435 127.44 78.705 ;
     RECT  2.16 78.975 127.44 79.245 ;
     RECT  2.16 79.515 127.44 79.785 ;
     RECT  2.16 80.055 127.44 80.325 ;
     RECT  2.16 80.595 127.44 80.865 ;
     RECT  2.16 81.135 127.44 81.405 ;
     RECT  2.16 81.675 127.44 81.945 ;
     RECT  2.16 82.215 127.44 82.485 ;
     RECT  2.16 82.755 127.44 83.025 ;
     RECT  2.16 83.295 127.44 83.565 ;
     RECT  2.16 83.835 127.44 84.105 ;
    LAYER M1 ;
     RECT  2.16 2.151 127.44 84.249 ;
    LAYER M2 ;
     RECT  0.103 22.788 2.16 22.806 ;
     RECT  0.103 47.862 2.16 47.88 ;
     RECT  0.103 61.47 2.16 61.488 ;
     RECT  0.103 62.82 2.16 62.838 ;
     RECT  2.16 2.151 49.531 84.249 ;
     RECT  49.531 2.106 50.351 84.249 ;
     RECT  50.351 2.151 127.44 84.249 ;
     RECT  127.44 55.386 128.255 56.124 ;
     RECT  127.44 45.936 128.291 46.674 ;
     RECT  127.44 25.956 128.831 25.974 ;
     RECT  127.44 27.036 128.831 27.36 ;
     RECT  127.44 28.656 128.831 28.674 ;
     RECT  127.44 29.736 128.831 30.204 ;
     RECT  127.44 31.086 128.831 31.104 ;
     RECT  127.44 32.976 128.831 33.534 ;
     RECT  127.44 34.506 128.831 34.524 ;
     RECT  127.44 35.442 128.831 35.46 ;
     RECT  127.44 36.288 128.831 36.306 ;
     RECT  127.44 37.296 128.831 37.314 ;
     RECT  127.44 38.106 128.831 38.736 ;
     RECT  127.44 39.762 128.831 39.78 ;
     RECT  127.44 40.536 128.831 40.554 ;
     RECT  127.44 41.616 128.831 41.634 ;
     RECT  127.44 42.426 128.831 42.444 ;
     RECT  127.44 43.236 128.831 43.254 ;
     RECT  127.44 44.046 128.831 44.064 ;
     RECT  127.44 44.856 128.831 44.874 ;
     RECT  128.291 45.936 128.831 45.954 ;
     RECT  127.44 47.556 128.831 47.574 ;
     RECT  127.44 48.636 128.831 49.266 ;
     RECT  127.44 50.256 128.831 50.274 ;
     RECT  127.44 51.066 128.831 51.804 ;
     RECT  127.44 52.956 128.831 53.514 ;
     RECT  127.44 54.576 128.831 54.594 ;
     RECT  128.255 56.106 128.831 56.124 ;
     RECT  127.44 57.276 128.831 57.294 ;
     RECT  127.44 58.086 128.831 58.104 ;
     RECT  127.44 58.896 128.831 58.914 ;
     RECT  127.44 59.706 128.831 59.724 ;
     RECT  127.44 60.516 128.831 60.534 ;
     RECT  128.831 33.516 128.867 33.534 ;
     RECT  128.831 38.718 128.867 38.736 ;
     RECT  128.831 27.342 129.515 27.36 ;
     RECT  128.831 30.186 129.515 30.204 ;
     RECT  127.44 31.896 129.515 31.914 ;
     RECT  128.831 48.636 129.515 48.654 ;
     RECT  128.831 53.496 129.515 53.514 ;
    LAYER M3 ;
     RECT  44.028 0.091 44.046 1.723 ;
     RECT  53.532 0.091 53.55 1.723 ;
     RECT  49.212 0.091 49.23 2.101 ;
     RECT  50.076 0.091 50.094 2.101 ;
     RECT  50.94 0.091 50.958 2.101 ;
     RECT  39.708 0.091 39.726 2.143 ;
     RECT  40.572 0.091 40.59 2.143 ;
     RECT  44.964 1.723 44.982 2.143 ;
     RECT  45.756 0.091 45.774 2.143 ;
     RECT  49.212 2.101 50.958 2.143 ;
     RECT  51.804 1.723 51.822 2.143 ;
     RECT  56.124 0.091 56.142 2.143 ;
     RECT  57.024 0.091 57.042 2.143 ;
     RECT  61.308 0.091 61.326 2.143 ;
     RECT  62.172 0.091 62.19 2.143 ;
     RECT  66.492 0.091 66.51 2.143 ;
     RECT  67.536 0.091 68.238 2.143 ;
     RECT  72.972 0.091 73.422 2.143 ;
     RECT  77.724 0.091 77.742 2.143 ;
     RECT  78.588 0.091 78.606 2.143 ;
     RECT  82.908 0.091 82.926 2.143 ;
     RECT  83.808 0.091 83.826 2.143 ;
     RECT  88.092 0.091 88.11 2.143 ;
     RECT  88.956 0.091 88.974 2.143 ;
     RECT  37.98 0.091 37.998 2.191 ;
     RECT  42.3 0.091 42.318 2.191 ;
     RECT  43.308 1.723 44.046 2.191 ;
     RECT  44.964 2.143 45.774 2.191 ;
     RECT  46.62 0.091 46.638 2.191 ;
     RECT  47.772 0.091 48.366 2.191 ;
     RECT  49.212 2.143 51.822 2.191 ;
     RECT  52.956 1.723 53.55 2.191 ;
     RECT  54.396 0.091 54.414 2.191 ;
     RECT  55.26 0.091 55.278 2.191 ;
     RECT  56.124 2.143 57.042 2.191 ;
     RECT  57.852 0.091 57.87 2.191 ;
     RECT  58.716 0.091 58.734 2.191 ;
     RECT  59.58 0.091 59.598 2.191 ;
     RECT  61.308 2.143 62.19 2.191 ;
     RECT  63.036 0.091 63.054 2.191 ;
     RECT  70.2 0.091 70.83 2.191 ;
     RECT  71.676 0.091 71.694 2.191 ;
     RECT  75.312 0.091 76.014 2.191 ;
     RECT  76.968 0.091 76.986 2.191 ;
     RECT  77.724 2.143 78.606 2.191 ;
     RECT  79.488 0.091 79.506 2.191 ;
     RECT  80.316 0.091 80.334 2.191 ;
     RECT  81.18 0.091 81.198 2.191 ;
     RECT  82.08 0.091 82.098 2.191 ;
     RECT  82.908 2.143 83.826 2.191 ;
     RECT  84.636 0.091 84.654 2.191 ;
     RECT  85.5 0.091 85.518 2.191 ;
     RECT  86.364 0.091 86.382 2.191 ;
     RECT  87.228 0.091 87.246 2.191 ;
     RECT  88.092 2.143 88.974 2.191 ;
     RECT  89.82 0.091 89.838 2.191 ;
     RECT  90.684 0.091 90.702 2.191 ;
     RECT  37.908 2.191 37.998 2.227 ;
     RECT  38.844 0.091 38.862 2.227 ;
     RECT  44.964 2.191 46.638 2.227 ;
     RECT  72.615 2.143 73.422 2.227 ;
     RECT  74.268 0.091 74.286 2.227 ;
     RECT  37.116 0.091 37.134 2.263 ;
     RECT  37.908 2.227 38.862 2.263 ;
     RECT  41.436 0.091 41.454 2.263 ;
     RECT  42.3 2.191 44.046 2.263 ;
     RECT  44.964 2.227 46.782 2.263 ;
     RECT  47.772 2.191 51.822 2.263 ;
     RECT  52.956 2.191 55.278 2.263 ;
     RECT  56.124 2.191 57.87 2.263 ;
     RECT  69.264 0.091 69.282 2.263 ;
     RECT  72.615 2.227 74.286 2.263 ;
     RECT  75.312 2.191 76.05 2.263 ;
     RECT  76.968 2.191 78.606 2.263 ;
     RECT  91.728 0.091 92.43 2.263 ;
     RECT  37.116 2.263 38.862 2.335 ;
     RECT  39.708 2.143 40.59 2.335 ;
     RECT  41.436 2.263 44.046 2.335 ;
     RECT  44.964 2.263 51.822 2.335 ;
     RECT  52.956 2.263 57.87 2.335 ;
     RECT  58.716 2.191 59.598 2.335 ;
     RECT  60.444 0.091 60.462 2.335 ;
     RECT  61.272 2.191 62.19 2.335 ;
     RECT  63.036 2.191 63.09 2.335 ;
     RECT  64.152 0.091 64.782 2.335 ;
     RECT  65.628 0.091 65.646 2.335 ;
     RECT  66.492 2.143 68.238 2.335 ;
     RECT  68.976 2.263 69.282 2.335 ;
     RECT  70.2 2.191 71.694 2.335 ;
     RECT  72.504 2.263 78.606 2.335 ;
     RECT  37.116 2.335 51.822 2.371 ;
     RECT  52.956 2.335 60.462 2.371 ;
     RECT  61.272 2.335 63.09 2.371 ;
     RECT  64.152 2.335 78.606 2.371 ;
     RECT  79.488 2.191 84.654 2.371 ;
     RECT  85.5 2.191 86.382 2.371 ;
     RECT  87.228 2.191 88.974 2.371 ;
     RECT  89.82 2.191 90.702 2.371 ;
     RECT  91.728 2.263 92.934 2.371 ;
     RECT  2.415 2.143 2.505 2.413 ;
     RECT  7.815 2.143 7.905 2.413 ;
     RECT  13.215 2.143 13.305 2.413 ;
     RECT  18.615 2.143 18.705 2.413 ;
     RECT  24.015 2.143 24.105 2.413 ;
     RECT  29.415 2.143 29.505 2.413 ;
     RECT  34.815 2.143 34.905 2.413 ;
     RECT  94.215 2.143 94.305 2.413 ;
     RECT  99.615 2.143 99.705 2.413 ;
     RECT  105.015 2.143 105.105 2.413 ;
     RECT  110.415 2.143 110.505 2.413 ;
     RECT  115.815 2.143 115.905 2.413 ;
     RECT  121.215 2.143 121.305 2.413 ;
     RECT  126.615 2.143 126.705 2.413 ;
     RECT  37.044 2.371 92.934 2.489 ;
     RECT  37.044 2.489 41.238 2.525 ;
     RECT  59.22 2.489 70.146 2.525 ;
     RECT  70.956 2.489 78.297 2.525 ;
     RECT  91.26 2.489 92.79 2.525 ;
     RECT  59.22 2.525 64.17 2.561 ;
     RECT  37.188 2.525 41.058 2.759 ;
     RECT  62.82 2.561 64.17 2.759 ;
     RECT  66.708 2.525 69.714 2.759 ;
     RECT  72.18 2.525 78.297 2.759 ;
     RECT  86.004 2.489 90.342 2.759 ;
     RECT  92.664 2.525 92.79 2.759 ;
     RECT  62.82 2.759 64.026 2.795 ;
     RECT  73.836 2.759 78.297 2.795 ;
     RECT  42.012 2.489 58.122 2.831 ;
     RECT  70.956 2.525 71.334 2.861 ;
     RECT  42.012 2.831 53.766 2.939 ;
     RECT  42.012 2.939 44.766 3.029 ;
     RECT  54.504 2.831 58.122 3.029 ;
     RECT  62.82 2.795 63.45 3.029 ;
     RECT  81.648 2.489 84.258 3.029 ;
     RECT  37.764 2.759 41.058 3.101 ;
     RECT  45.615 2.939 53.766 3.299 ;
     RECT  64.944 2.525 65.934 3.299 ;
     RECT  66.708 2.759 68.958 3.299 ;
     RECT  69.696 2.759 69.714 3.299 ;
     RECT  92.664 2.759 92.682 3.299 ;
     RECT  79.128 2.489 79.974 3.307 ;
     RECT  85.14 2.489 85.23 3.307 ;
     RECT  86.004 2.759 86.814 3.307 ;
     RECT  43.848 3.029 44.766 3.335 ;
     RECT  73.836 2.795 76.266 3.335 ;
     RECT  42.012 3.029 42.966 3.343 ;
     RECT  55.584 3.029 58.122 3.343 ;
     RECT  72.18 2.759 72.99 3.343 ;
     RECT  64.944 3.299 65.25 3.371 ;
     RECT  79.02 3.307 79.974 3.371 ;
     RECT  64.944 3.371 64.998 3.379 ;
     RECT  80.784 2.489 80.802 3.379 ;
     RECT  81.648 3.029 82.386 3.379 ;
     RECT  55.584 3.343 58.41 3.403 ;
     RECT  59.22 2.561 62.097 3.403 ;
     RECT  85.14 3.307 86.814 3.403 ;
     RECT  55.584 3.403 62.097 3.415 ;
     RECT  62.82 3.029 62.982 3.415 ;
     RECT  87.624 2.759 90.342 3.415 ;
     RECT  91.26 2.525 91.818 3.415 ;
     RECT  37.764 3.101 40.986 3.437 ;
     RECT  80.784 3.379 82.386 3.437 ;
     RECT  85.104 3.403 86.814 3.437 ;
     RECT  79.236 3.371 79.974 3.451 ;
     RECT  80.784 3.437 81.702 3.451 ;
     RECT  83.196 3.029 84.258 3.451 ;
     RECT  85.104 3.437 85.266 3.451 ;
     RECT  79.236 3.451 81.702 3.479 ;
     RECT  37.764 3.437 37.782 3.569 ;
     RECT  55.584 3.415 62.982 3.569 ;
     RECT  67.14 3.299 68.958 3.569 ;
     RECT  69.984 3.415 70.002 3.569 ;
     RECT  70.956 2.861 71.118 3.569 ;
     RECT  73.836 3.335 75.186 3.569 ;
     RECT  76.104 3.335 76.266 3.569 ;
     RECT  77.148 2.795 78.297 3.569 ;
     RECT  79.236 3.479 81.666 3.569 ;
     RECT  83.196 3.451 85.266 3.569 ;
     RECT  86.004 3.437 86.814 3.569 ;
     RECT  87.624 3.415 92.142 3.569 ;
     RECT  83.196 3.569 84.294 3.605 ;
     RECT  70.956 3.569 71.01 3.613 ;
     RECT  38.52 3.437 40.986 3.641 ;
     RECT  67.215 3.569 68.958 3.643 ;
     RECT  71.856 3.343 72.99 3.643 ;
     RECT  73.836 3.569 74.934 3.643 ;
     RECT  71.856 3.643 74.934 3.677 ;
     RECT  41.976 3.343 42.966 3.685 ;
     RECT  64.872 3.379 64.998 3.685 ;
     RECT  45.615 3.299 48.51 3.713 ;
     RECT  67.215 3.643 69.066 3.713 ;
     RECT  79.236 3.569 80.622 3.713 ;
     RECT  86.76 3.569 86.814 3.721 ;
     RECT  41.94 3.685 42.966 3.725 ;
     RECT  79.74 3.713 80.622 3.725 ;
     RECT  79.884 3.725 80.622 3.749 ;
     RECT  83.232 3.605 84.294 3.749 ;
     RECT  86.004 3.569 86.022 3.749 ;
     RECT  42.372 3.725 42.966 3.835 ;
     RECT  64.296 3.685 64.998 3.835 ;
     RECT  38.52 3.641 38.538 3.839 ;
     RECT  42.372 3.835 43.038 3.839 ;
     RECT  55.584 3.569 58.806 3.839 ;
     RECT  59.832 3.569 62.73 3.839 ;
     RECT  64.116 3.835 64.998 3.839 ;
     RECT  67.215 3.713 68.958 3.839 ;
     RECT  70.128 3.613 71.01 3.839 ;
     RECT  80.424 3.749 80.622 3.839 ;
     RECT  81.504 3.569 81.522 3.839 ;
     RECT  83.415 3.749 84.294 3.839 ;
     RECT  85.248 3.569 85.266 3.839 ;
     RECT  88.308 3.569 91.746 3.839 ;
     RECT  43.848 3.335 44.442 3.847 ;
     RECT  66.204 3.343 66.366 3.869 ;
     RECT  72.18 3.677 74.934 3.869 ;
     RECT  64.116 3.839 64.134 3.875 ;
     RECT  68.832 3.839 68.85 3.875 ;
     RECT  70.128 3.839 70.722 3.875 ;
     RECT  80.424 3.839 80.442 3.875 ;
     RECT  88.308 3.839 89.097 3.875 ;
     RECT  90.144 3.839 91.746 3.875 ;
     RECT  67.215 3.839 67.806 3.911 ;
     RECT  70.272 3.875 70.722 3.911 ;
     RECT  54.504 3.029 54.846 3.931 ;
     RECT  55.584 3.839 58.734 3.931 ;
     RECT  39.456 3.641 40.986 3.955 ;
     RECT  86.76 3.721 87.354 3.965 ;
     RECT  42.876 3.839 43.038 3.983 ;
     RECT  46.62 3.713 48.51 3.983 ;
     RECT  72.18 3.869 74.862 3.983 ;
     RECT  87.336 3.965 87.354 3.983 ;
     RECT  88.524 3.875 89.097 3.983 ;
     RECT  43.812 3.847 44.442 3.991 ;
     RECT  49.428 3.299 53.766 3.991 ;
     RECT  54.504 3.931 58.734 3.991 ;
     RECT  59.832 3.839 62.097 4.019 ;
     RECT  39.456 3.955 41.238 4.109 ;
     RECT  59.94 4.019 62.097 4.109 ;
     RECT  72.615 3.983 74.862 4.109 ;
     RECT  76.788 3.721 76.95 4.109 ;
     RECT  77.724 3.569 78.297 4.109 ;
     RECT  76.788 4.109 76.806 4.115 ;
     RECT  43.236 3.991 44.442 4.145 ;
     RECT  60.984 4.109 61.002 4.145 ;
     RECT  64.872 3.839 64.998 4.145 ;
     RECT  43.38 4.145 44.442 4.153 ;
     RECT  49.428 3.991 58.734 4.217 ;
     RECT  64.872 4.145 64.89 4.217 ;
     RECT  39.456 4.109 40.497 4.253 ;
     RECT  74.844 4.109 74.862 4.253 ;
     RECT  49.428 4.217 58.014 4.261 ;
     RECT  49.356 4.261 58.014 4.289 ;
     RECT  46.656 3.983 48.51 4.301 ;
     RECT  39.78 4.253 40.497 4.379 ;
     RECT  41.22 4.109 41.238 4.379 ;
     RECT  46.8 4.301 48.51 4.379 ;
     RECT  59.94 4.109 60.21 4.379 ;
     RECT  46.872 4.379 48.51 4.451 ;
     RECT  43.38 4.153 44.514 4.487 ;
     RECT  49.356 4.289 57.942 4.487 ;
     RECT  43.38 4.487 44.442 4.523 ;
     RECT  49.356 4.487 55.422 4.523 ;
     RECT  49.644 4.523 55.422 4.541 ;
     RECT  43.38 4.523 43.398 4.559 ;
     RECT  55.26 4.541 55.422 4.559 ;
     RECT  56.415 4.487 57.942 4.559 ;
     RECT  46.872 4.451 48.366 4.685 ;
     RECT  48.132 4.685 48.366 4.721 ;
     RECT  46.872 4.685 47.214 4.793 ;
     RECT  48.132 4.721 48.186 4.793 ;
     RECT  49.644 4.541 54.018 4.793 ;
     RECT  56.415 4.559 57.33 4.793 ;
     RECT  46.908 4.793 47.214 4.829 ;
     RECT  49.644 4.793 49.914 4.955 ;
     RECT  46.908 4.829 47.142 5.027 ;
     RECT  50.688 4.793 54.018 5.027 ;
     RECT  55.26 4.559 55.278 5.027 ;
     RECT  48.168 4.793 48.186 5.099 ;
     RECT  51.015 5.027 52.47 5.099 ;
     RECT  53.388 5.027 54.018 5.099 ;
     RECT  51.015 5.099 52.398 5.189 ;
     RECT  52.308 5.189 52.398 5.459 ;
     RECT  87.444 5.881 87.786 6.143 ;
     RECT  87.444 6.143 87.462 6.173 ;
     RECT  40.215 4.379 40.497 6.232 ;
     RECT  42.192 6.235 42.21 6.275 ;
     RECT  40.215 6.232 40.77 6.539 ;
     RECT  56.415 4.793 56.697 7.051 ;
     RECT  53.964 5.099 54.018 7.231 ;
     RECT  52.38 5.459 52.398 7.259 ;
     RECT  53.964 7.231 54.162 7.349 ;
     RECT  56.232 7.051 56.697 7.357 ;
     RECT  53.964 7.349 54.018 7.373 ;
     RECT  59.76 7.765 59.778 7.771 ;
     RECT  48.42 7.051 48.438 7.889 ;
     RECT  59.76 7.771 59.85 7.889 ;
     RECT  59.76 7.889 59.778 7.901 ;
     RECT  55.692 7.357 56.697 7.925 ;
     RECT  49.644 4.955 49.878 7.961 ;
     RECT  44.208 4.523 44.442 8.159 ;
     RECT  55.908 7.925 56.697 8.311 ;
     RECT  55.908 8.311 57.186 8.401 ;
     RECT  44.424 8.159 44.442 8.429 ;
     RECT  55.908 8.401 57.258 8.465 ;
     RECT  41.724 8.311 41.958 8.477 ;
     RECT  56.415 8.465 57.258 8.851 ;
     RECT  56.415 8.851 58.014 9.005 ;
     RECT  41.868 8.477 41.958 9.239 ;
     RECT  40.215 6.539 40.497 9.355 ;
     RECT  41.868 9.239 41.886 9.355 ;
     RECT  57.528 9.005 58.014 9.509 ;
     RECT  40.215 9.355 41.886 9.779 ;
     RECT  40.215 9.779 41.166 10.049 ;
     RECT  57.636 9.509 58.014 10.085 ;
     RECT  57.636 10.085 57.654 10.625 ;
     RECT  40.215 10.049 41.094 10.741 ;
     RECT  39.888 10.741 41.094 10.859 ;
     RECT  59.076 10.201 59.094 10.859 ;
     RECT  59.832 10.741 59.85 10.939 ;
     RECT  39.888 10.859 40.497 10.975 ;
     RECT  39.168 10.975 40.497 11.227 ;
     RECT  59.652 10.939 59.85 11.281 ;
     RECT  60.588 11.011 60.606 11.281 ;
     RECT  38.772 11.227 40.497 11.371 ;
     RECT  38.232 11.371 40.497 11.399 ;
     RECT  59.652 11.281 60.678 11.399 ;
     RECT  60.156 11.399 60.678 11.405 ;
     RECT  60.66 11.405 60.678 11.551 ;
     RECT  61.815 4.109 62.097 11.551 ;
     RECT  60.66 11.551 62.097 11.705 ;
     RECT  39.78 11.399 40.497 11.939 ;
     RECT  60.732 11.705 62.097 11.939 ;
     RECT  38.232 11.399 38.862 11.975 ;
     RECT  61.272 11.939 62.097 11.975 ;
     RECT  61.416 11.975 62.097 12.245 ;
     RECT  78.015 4.109 78.297 13.171 ;
     RECT  94.215 2.413 94.497 13.261 ;
     RECT  78.015 13.171 78.606 13.289 ;
     RECT  81.432 13.171 81.45 13.297 ;
     RECT  61.56 12.245 62.097 13.325 ;
     RECT  91.332 3.875 91.746 13.333 ;
     RECT  82.656 13.171 82.674 13.361 ;
     RECT  94.104 13.261 94.497 13.369 ;
     RECT  80.496 13.297 80.514 13.373 ;
     RECT  91.224 13.333 91.746 13.397 ;
     RECT  61.815 13.325 62.097 13.441 ;
     RECT  81.288 13.297 81.45 13.441 ;
     RECT  83.415 3.839 83.697 13.441 ;
     RECT  38.376 11.975 38.862 13.559 ;
     RECT  82.8 13.441 83.697 13.559 ;
     RECT  81.288 13.441 81.774 13.595 ;
     RECT  81.288 13.595 81.45 13.639 ;
     RECT  81.036 13.639 81.45 13.667 ;
     RECT  38.844 13.559 38.862 13.829 ;
     RECT  36.252 13.639 36.27 13.981 ;
     RECT  63.036 13.981 63.054 14.099 ;
     RECT  62.892 14.107 62.91 14.144 ;
     RECT  61.815 13.441 62.154 14.215 ;
     RECT  36.252 13.981 36.666 14.369 ;
     RECT  34.815 2.413 35.097 14.485 ;
     RECT  63.972 14.251 63.99 14.675 ;
     RECT  94.104 13.369 94.734 14.791 ;
     RECT  34.815 14.485 35.262 14.909 ;
     RECT  94.104 14.791 94.986 14.923 ;
     RECT  64.008 14.791 64.026 14.945 ;
     RECT  93.924 14.923 94.986 15.053 ;
     RECT  33.3 15.025 33.318 15.061 ;
     RECT  94.215 15.053 94.986 15.061 ;
     RECT  33.3 15.061 33.462 15.101 ;
     RECT  36.648 14.369 36.666 15.179 ;
     RECT  61.815 14.215 62.19 15.179 ;
     RECT  94.215 15.061 95.238 15.215 ;
     RECT  53.964 7.373 53.982 15.449 ;
     RECT  53.1 15.457 53.118 15.493 ;
     RECT  52.344 15.529 52.362 15.601 ;
     RECT  53.1 15.493 53.154 15.601 ;
     RECT  64.224 15.061 64.242 15.601 ;
     RECT  52.344 15.601 53.154 15.869 ;
     RECT  34.815 14.909 35.19 15.989 ;
     RECT  62.82 15.331 62.838 16.025 ;
     RECT  95.22 15.215 95.238 16.025 ;
     RECT  33.444 15.101 33.462 16.105 ;
     RECT  64.224 15.601 64.35 16.141 ;
     RECT  32.76 16.105 33.462 16.157 ;
     RECT  63.792 16.141 64.35 16.501 ;
     RECT  63.792 16.501 64.458 16.529 ;
     RECT  96.408 16.141 96.426 16.529 ;
     RECT  52.632 15.869 53.154 16.645 ;
     RECT  64.332 16.529 64.458 16.673 ;
     RECT  32.904 16.157 33.462 16.979 ;
     RECT  18.615 2.413 18.897 17.041 ;
     RECT  52.524 16.645 53.154 17.041 ;
     RECT  32.904 16.979 32.922 17.069 ;
     RECT  32.04 16.951 32.058 17.105 ;
     RECT  65.52 16.501 65.538 17.275 ;
     RECT  65.448 17.275 65.538 17.339 ;
     RECT  97.272 16.501 97.29 17.375 ;
     RECT  66.348 3.869 66.366 17.491 ;
     RECT  67.215 3.911 67.497 17.491 ;
     RECT  64.44 16.673 64.458 17.645 ;
     RECT  97.704 17.491 97.902 17.879 ;
     RECT  97.704 17.879 97.722 17.987 ;
     RECT  98.676 14.953 98.694 17.995 ;
     RECT  98.496 17.995 98.694 18.031 ;
     RECT  99.615 2.413 99.897 18.031 ;
     RECT  98.496 18.031 99.897 18.149 ;
     RECT  66.348 17.491 67.497 18.185 ;
     RECT  52.416 17.041 53.154 18.193 ;
     RECT  67.215 18.185 67.497 18.193 ;
     RECT  51.015 5.189 51.297 18.301 ;
     RECT  52.02 18.193 53.154 18.301 ;
     RECT  65.412 17.653 65.43 18.301 ;
     RECT  66.348 18.185 66.366 18.301 ;
     RECT  51.015 18.301 53.154 18.329 ;
     RECT  65.412 18.301 66.366 18.329 ;
     RECT  51.015 18.329 52.506 18.419 ;
     RECT  45.615 3.713 45.897 18.463 ;
     RECT  45 18.463 45.897 18.535 ;
     RECT  51.015 18.419 52.038 18.563 ;
     RECT  67.215 18.193 67.842 18.571 ;
     RECT  67.215 18.571 68.562 18.689 ;
     RECT  99.072 18.149 99.897 18.725 ;
     RECT  65.844 18.329 66.366 18.749 ;
     RECT  49.86 7.961 49.878 18.769 ;
     RECT  68.544 18.689 68.562 18.769 ;
     RECT  49.86 18.769 50.274 18.797 ;
     RECT  51.015 18.563 51.858 18.797 ;
     RECT  44.964 18.535 45.897 18.802 ;
     RECT  99.18 18.725 99.897 18.995 ;
     RECT  45 18.802 45.897 19.229 ;
     RECT  65.916 18.749 66.366 19.229 ;
     RECT  94.215 15.215 94.497 19.381 ;
     RECT  83.415 13.559 83.697 19.471 ;
     RECT  43.848 19.345 43.866 19.499 ;
     RECT  68.544 18.769 68.886 19.499 ;
     RECT  94.215 19.381 94.662 19.499 ;
     RECT  106.164 19.651 106.182 19.805 ;
     RECT  41.616 20.149 41.634 20.191 ;
     RECT  42.984 19.651 43.002 20.191 ;
     RECT  42.804 20.191 43.002 20.309 ;
     RECT  42.804 20.309 42.822 20.345 ;
     RECT  108.324 19.921 108.342 20.345 ;
     RECT  50.256 18.797 50.274 20.615 ;
     RECT  99.216 18.995 99.897 20.615 ;
     RECT  41.616 20.191 41.778 20.695 ;
     RECT  20.016 17.077 20.034 20.849 ;
     RECT  41.4 20.695 41.778 20.849 ;
     RECT  102.276 18.121 102.294 20.965 ;
     RECT  40.215 11.939 40.497 21.001 ;
     RECT  45.615 19.229 45.897 21.091 ;
     RECT  81.036 13.667 81.054 21.119 ;
     RECT  100.908 20.731 100.926 21.119 ;
     RECT  2.415 2.413 2.697 21.163 ;
     RECT  43.776 21.091 43.794 21.163 ;
     RECT  46.908 5.027 47.034 21.163 ;
     RECT  45.036 21.091 45.897 21.197 ;
     RECT  102.276 20.965 102.582 21.199 ;
     RECT  126.615 2.413 126.897 21.199 ;
     RECT  51.015 18.797 51.786 21.235 ;
     RECT  102.276 21.199 103.086 21.235 ;
     RECT  41.832 21.235 41.85 21.271 ;
     RECT  101.772 21.235 103.086 21.271 ;
     RECT  101.772 21.271 103.446 21.293 ;
     RECT  18.615 17.041 18.954 21.389 ;
     RECT  41.832 21.271 42.354 21.389 ;
     RECT  50.724 21.235 51.786 21.389 ;
     RECT  102.348 21.293 103.446 21.389 ;
     RECT  56.415 9.005 56.697 21.397 ;
     RECT  2.304 21.163 2.697 21.425 ;
     RECT  111.744 20.731 111.762 21.425 ;
     RECT  46.908 21.163 47.286 21.497 ;
     RECT  40.215 21.001 40.986 21.505 ;
     RECT  40.104 21.505 40.986 21.569 ;
     RECT  41.832 21.389 41.994 21.631 ;
     RECT  43.776 21.163 43.866 21.643 ;
     RECT  40.104 21.569 40.497 21.659 ;
     RECT  41.436 21.631 41.994 21.659 ;
     RECT  38.34 21.631 38.502 21.677 ;
     RECT  43.2 21.643 43.866 21.677 ;
     RECT  50.724 21.389 51.606 21.739 ;
     RECT  50.04 21.739 51.606 21.803 ;
     RECT  3.492 21.271 3.51 21.811 ;
     RECT  83.415 19.471 84.042 21.929 ;
     RECT  113.328 21.541 113.346 21.929 ;
     RECT  46.908 21.497 47.034 21.937 ;
     RECT  55.764 21.397 56.697 21.937 ;
     RECT  65.916 19.229 65.934 21.937 ;
     RECT  65.844 21.937 65.934 21.965 ;
     RECT  103.428 21.389 103.446 21.965 ;
     RECT  43.2 21.677 43.398 22.081 ;
     RECT  50.184 21.803 51.606 22.199 ;
     RECT  54.576 20.551 54.594 22.199 ;
     RECT  2.34 21.425 2.697 22.235 ;
     RECT  44.136 22.081 44.154 22.235 ;
     RECT  3.492 21.811 3.69 22.279 ;
     RECT  2.415 22.235 2.697 22.315 ;
     RECT  3.492 22.279 3.834 22.315 ;
     RECT  2.415 22.315 4.086 22.469 ;
     RECT  103.86 22.081 103.878 22.469 ;
     RECT  46.8 21.937 47.034 22.513 ;
     RECT  46.764 22.513 47.034 22.541 ;
     RECT  40.215 21.659 40.497 22.585 ;
     RECT  41.436 21.659 41.454 22.585 ;
     RECT  67.215 18.689 67.497 22.603 ;
     RECT  5.292 21.397 5.31 22.711 ;
     RECT  38.484 21.677 38.502 22.739 ;
     RECT  46.764 22.541 46.782 22.739 ;
     RECT  57.96 22.207 57.978 22.739 ;
     RECT  67.215 22.603 67.698 22.739 ;
     RECT  42.768 22.081 43.398 22.775 ;
     RECT  113.868 22.081 113.886 22.775 ;
     RECT  57.816 22.747 57.834 22.784 ;
     RECT  40.215 22.585 41.454 22.795 ;
     RECT  39.528 22.795 41.454 22.891 ;
     RECT  42.768 22.775 43.002 22.891 ;
     RECT  0.108 22.783 0.126 22.925 ;
     RECT  39.528 22.891 41.562 23.032 ;
     RECT  42.336 22.891 43.002 23.045 ;
     RECT  2.415 22.469 3.834 23.251 ;
     RECT  50.688 22.199 51.606 23.251 ;
     RECT  60.552 22.513 60.57 23.251 ;
     RECT  5.292 22.711 5.49 23.275 ;
     RECT  115.815 2.413 116.097 23.275 ;
     RECT  2.415 23.251 4.014 23.279 ;
     RECT  38.772 23.161 38.79 23.279 ;
     RECT  39.672 23.032 41.562 23.279 ;
     RECT  114.12 22.891 114.318 23.279 ;
     RECT  59.436 22.711 59.454 23.315 ;
     RECT  114.12 23.279 114.138 23.315 ;
     RECT  5.292 23.275 5.562 23.323 ;
     RECT  115.74 23.275 116.097 23.323 ;
     RECT  5.292 23.323 5.706 23.549 ;
     RECT  39.672 23.279 41.094 23.549 ;
     RECT  41.832 23.371 41.85 23.585 ;
     RECT  115.488 23.323 116.097 23.585 ;
     RECT  61.815 15.179 62.097 23.701 ;
     RECT  115.74 23.585 116.097 23.701 ;
     RECT  65.844 21.965 65.862 23.729 ;
     RECT  2.415 23.279 2.697 23.755 ;
     RECT  3.816 23.279 4.014 23.755 ;
     RECT  5.292 23.549 5.49 23.819 ;
     RECT  42.912 23.045 43.002 23.819 ;
     RECT  2.304 23.755 2.697 23.855 ;
     RECT  42.984 23.819 43.002 23.855 ;
     RECT  60.552 23.251 60.786 23.855 ;
     RECT  61.815 23.701 62.334 23.863 ;
     RECT  3.816 23.755 4.554 23.971 ;
     RECT  5.292 23.819 5.31 23.971 ;
     RECT  3.816 23.971 5.31 24.089 ;
     RECT  39.672 23.549 41.058 24.089 ;
     RECT  64.224 23.899 64.35 24.089 ;
     RECT  55.764 21.937 56.898 24.091 ;
     RECT  3.816 24.089 3.978 24.125 ;
     RECT  53.028 24.061 53.046 24.125 ;
     RECT  61.815 23.863 62.73 24.125 ;
     RECT  39.672 24.089 40.497 24.205 ;
     RECT  55.764 24.091 56.97 24.241 ;
     RECT  50.184 23.251 51.606 24.269 ;
     RECT  38.304 23.701 38.574 24.331 ;
     RECT  39.636 24.205 40.497 24.359 ;
     RECT  55.764 24.241 57.114 24.359 ;
     RECT  60.552 23.855 60.75 24.359 ;
     RECT  53.964 24.241 54.774 24.395 ;
     RECT  57.888 24.241 58.77 24.395 ;
     RECT  118.584 24.331 118.602 24.461 ;
     RECT  6.228 24.367 6.246 24.469 ;
     RECT  38.304 24.331 38.79 24.475 ;
     RECT  6.228 24.469 6.966 24.509 ;
     RECT  60.552 24.359 60.606 24.509 ;
     RECT  2.415 23.855 2.697 24.619 ;
     RECT  6.228 24.509 6.246 24.629 ;
     RECT  54.288 24.395 54.522 24.629 ;
     RECT  58.284 24.395 58.518 24.629 ;
     RECT  115.74 23.701 116.73 24.629 ;
     RECT  2.304 24.619 2.697 24.665 ;
     RECT  54.288 24.629 54.306 24.665 ;
     RECT  58.284 24.629 58.302 24.665 ;
     RECT  64.332 24.089 64.35 24.665 ;
     RECT  115.815 24.629 116.73 24.665 ;
     RECT  38.196 24.475 38.79 24.781 ;
     RECT  38.088 24.781 38.79 24.899 ;
     RECT  65.196 24.781 65.214 24.899 ;
     RECT  65.484 25.003 65.502 25.043 ;
     RECT  9.648 24.907 9.666 25.051 ;
     RECT  36.432 24.907 36.45 25.051 ;
     RECT  67.215 22.739 67.497 25.051 ;
     RECT  117.576 24.781 117.594 25.099 ;
     RECT  115.815 24.665 116.262 25.133 ;
     RECT  38.088 24.899 38.718 25.169 ;
     RECT  38.088 25.169 38.43 25.205 ;
     RECT  9.432 25.051 9.666 25.313 ;
     RECT  9.432 25.313 9.45 25.325 ;
     RECT  3.816 24.125 3.834 25.435 ;
     RECT  5.292 24.089 5.31 25.439 ;
     RECT  117.432 25.099 117.594 25.439 ;
     RECT  66.6 25.051 67.497 25.475 ;
     RECT  117.432 25.439 117.45 25.517 ;
     RECT  3.816 25.435 4.374 25.591 ;
     RECT  36.432 25.051 37.026 25.661 ;
     RECT  118.836 25.591 118.854 25.681 ;
     RECT  3.816 25.591 4.518 25.709 ;
     RECT  38.088 25.205 38.106 25.709 ;
     RECT  66.78 25.475 67.497 25.745 ;
     RECT  118.836 25.681 119.214 25.745 ;
     RECT  119.196 25.745 119.214 25.781 ;
     RECT  36.576 25.661 37.026 25.825 ;
     RECT  68.652 19.499 68.886 25.861 ;
     RECT  121.215 2.413 121.497 25.861 ;
     RECT  125.892 21.199 126.897 25.861 ;
     RECT  55.764 24.359 56.898 25.979 ;
     RECT  103.968 22.621 103.986 25.979 ;
     RECT  128.808 25.915 128.826 25.979 ;
     RECT  68.508 25.861 68.886 26.015 ;
     RECT  125.892 25.861 127.134 26.015 ;
     RECT  125.892 26.015 126.897 26.095 ;
     RECT  56.415 25.979 56.898 26.131 ;
     RECT  69.624 26.095 69.642 26.141 ;
     RECT  124.092 26.203 124.11 26.221 ;
     RECT  124.92 26.095 124.938 26.221 ;
     RECT  124.092 26.221 124.938 26.237 ;
     RECT  6.156 25.681 6.174 26.249 ;
     RECT  36.576 25.825 37.206 26.249 ;
     RECT  34.815 15.989 35.097 26.251 ;
     RECT  121.215 25.861 122.202 26.285 ;
     RECT  5.22 26.251 5.238 26.401 ;
     RECT  34.815 26.251 35.37 26.401 ;
     RECT  58.608 26.401 58.626 26.485 ;
     RECT  60.552 24.509 60.57 26.485 ;
     RECT  56.415 26.131 57.042 26.491 ;
     RECT  36.576 26.249 36.594 26.519 ;
     RECT  124.092 26.237 124.254 26.519 ;
     RECT  60.552 26.485 60.606 26.525 ;
     RECT  70.812 26.131 70.83 26.555 ;
     RECT  58.608 26.485 59.058 26.671 ;
     RECT  125.784 26.095 126.897 26.671 ;
     RECT  56.415 26.491 57.762 26.699 ;
     RECT  57.744 26.699 57.762 26.731 ;
     RECT  58.608 26.671 59.13 26.731 ;
     RECT  57.744 26.731 59.13 26.765 ;
     RECT  124.092 26.519 124.11 26.765 ;
     RECT  34.815 26.401 35.514 26.789 ;
     RECT  71.028 26.671 71.046 26.789 ;
     RECT  125.244 26.671 126.897 26.825 ;
     RECT  125.892 26.825 126.897 26.941 ;
     RECT  58.464 26.765 59.13 27.031 ;
     RECT  128.808 26.779 128.826 27.059 ;
     RECT  58.464 27.031 59.49 27.095 ;
     RECT  125.892 26.941 127.134 27.095 ;
     RECT  59.472 27.095 59.49 27.131 ;
     RECT  121.215 26.285 121.497 27.163 ;
     RECT  2.415 24.665 2.697 27.175 ;
     RECT  3.816 25.709 3.906 27.211 ;
     RECT  5.22 26.401 5.382 27.211 ;
     RECT  60.552 26.525 60.57 27.211 ;
     RECT  121.215 27.163 122.022 27.211 ;
     RECT  2.304 27.175 2.697 27.245 ;
     RECT  60.3 27.211 60.57 27.301 ;
     RECT  61.815 24.125 62.097 27.301 ;
     RECT  5.22 27.211 5.454 27.329 ;
     RECT  58.464 27.095 58.626 27.329 ;
     RECT  96.84 27.211 96.858 27.329 ;
     RECT  121.215 27.211 122.202 27.329 ;
     RECT  61.704 27.301 62.097 27.337 ;
     RECT  5.22 27.329 5.274 27.341 ;
     RECT  6.228 26.527 6.246 27.355 ;
     RECT  3.816 27.211 4.374 27.365 ;
     RECT  58.464 27.329 58.482 27.365 ;
     RECT  71.136 26.941 71.154 27.365 ;
     RECT  121.215 27.329 122.022 27.365 ;
     RECT  125.892 27.095 127.098 27.401 ;
     RECT  61.524 27.337 62.097 27.481 ;
     RECT  61.524 27.481 62.694 27.595 ;
     RECT  61.524 27.595 62.91 27.599 ;
     RECT  60.084 27.301 60.57 27.635 ;
     RECT  61.704 27.599 62.91 27.635 ;
     RECT  123.12 27.337 123.138 27.635 ;
     RECT  60.264 27.635 60.57 27.671 ;
     RECT  129.492 27.337 129.51 27.677 ;
     RECT  6.228 27.355 6.966 27.751 ;
     RECT  7.815 2.413 8.097 27.751 ;
     RECT  61.815 27.635 62.91 27.841 ;
     RECT  63.972 27.751 63.99 27.841 ;
     RECT  6.228 27.751 8.097 27.869 ;
     RECT  6.228 27.869 6.966 27.905 ;
     RECT  61.815 27.841 63.054 27.905 ;
     RECT  2.415 27.245 2.697 28.021 ;
     RECT  2.415 28.021 2.898 28.075 ;
     RECT  2.304 28.075 2.898 28.139 ;
     RECT  6.228 27.905 6.246 28.139 ;
     RECT  50.58 24.269 51.606 28.139 ;
     RECT  2.304 28.139 2.697 28.175 ;
     RECT  5.256 27.341 5.274 28.175 ;
     RECT  63.972 27.841 64.818 28.175 ;
     RECT  50.688 28.139 51.606 28.219 ;
     RECT  50.688 28.219 51.642 28.247 ;
     RECT  64.188 28.175 64.818 28.381 ;
     RECT  125.892 27.401 126.897 28.381 ;
     RECT  60.552 27.671 60.57 28.409 ;
     RECT  64.188 28.381 65.214 28.445 ;
     RECT  63.036 27.905 63.054 28.453 ;
     RECT  65.196 28.445 65.214 28.453 ;
     RECT  63.036 28.453 63.162 28.679 ;
     RECT  65.196 28.453 65.574 28.679 ;
     RECT  63.036 28.679 63.054 28.715 ;
     RECT  125.424 28.381 126.897 28.795 ;
     RECT  67.215 25.745 67.497 28.831 ;
     RECT  68.652 26.015 68.886 28.831 ;
     RECT  2.415 28.175 2.697 28.939 ;
     RECT  66.348 28.795 66.366 28.939 ;
     RECT  67.215 28.831 67.59 28.939 ;
     RECT  66.348 28.939 67.59 28.957 ;
     RECT  68.436 28.831 68.994 28.957 ;
     RECT  65.304 28.679 65.322 28.985 ;
     RECT  124.38 29.101 124.398 29.219 ;
     RECT  64.188 28.445 64.206 29.255 ;
     RECT  66.348 28.957 68.994 29.255 ;
     RECT  66.348 29.255 68.526 29.327 ;
     RECT  3.816 27.365 3.834 29.371 ;
     RECT  4.644 29.179 4.662 29.371 ;
     RECT  125.424 28.795 127.098 29.371 ;
     RECT  124.236 29.335 124.254 29.405 ;
     RECT  3.816 29.371 4.806 29.525 ;
     RECT  64.332 29.371 64.35 29.525 ;
     RECT  70.56 29.221 70.578 29.525 ;
     RECT  125.172 29.371 127.098 29.525 ;
     RECT  66.348 29.327 67.497 29.605 ;
     RECT  69.768 29.461 69.786 29.633 ;
     RECT  71.784 29.371 71.802 29.641 ;
     RECT  66.168 29.605 67.497 29.759 ;
     RECT  128.808 28.507 128.826 29.759 ;
     RECT  66.168 29.759 66.186 29.795 ;
     RECT  68.436 29.327 68.526 29.795 ;
     RECT  125.892 29.525 127.098 29.795 ;
     RECT  71.676 29.641 71.802 29.911 ;
     RECT  72.615 4.109 72.897 29.911 ;
     RECT  68.508 29.795 68.526 30.065 ;
     RECT  3.816 29.525 3.834 30.181 ;
     RECT  4.644 29.525 4.806 30.181 ;
     RECT  5.616 29.371 5.634 30.181 ;
     RECT  4.644 30.181 5.634 30.209 ;
     RECT  129.492 30.181 129.51 30.269 ;
     RECT  125.892 29.795 126.897 30.271 ;
     RECT  4.788 30.209 5.634 30.299 ;
     RECT  68.652 30.181 68.67 30.299 ;
     RECT  3.564 30.181 3.834 30.335 ;
     RECT  125.748 30.271 126.897 30.451 ;
     RECT  124.704 30.415 124.722 30.461 ;
     RECT  125.676 30.451 126.897 30.479 ;
     RECT  49.932 30.523 49.95 30.541 ;
     RECT  50.76 28.247 51.642 30.541 ;
     RECT  69.984 30.523 70.002 30.569 ;
     RECT  68.76 30.451 68.778 30.605 ;
     RECT  2.304 28.939 2.697 30.713 ;
     RECT  3.816 30.335 3.834 30.721 ;
     RECT  5.112 30.299 5.634 30.721 ;
     RECT  71.676 29.911 72.897 30.721 ;
     RECT  5.112 30.721 6.246 30.839 ;
     RECT  49.932 30.541 51.642 30.847 ;
     RECT  121.215 27.365 121.497 30.859 ;
     RECT  3.816 30.721 3.978 30.875 ;
     RECT  71.136 30.721 72.897 30.875 ;
     RECT  44.532 30.721 44.55 30.893 ;
     RECT  49.896 30.847 51.642 30.893 ;
     RECT  71.316 30.875 72.897 30.911 ;
     RECT  42.768 30.811 42.786 30.989 ;
     RECT  50.148 30.893 51.642 30.989 ;
     RECT  54.72 30.763 54.738 30.989 ;
     RECT  121.215 30.859 122.202 30.989 ;
     RECT  118.584 30.883 118.602 31.019 ;
     RECT  128.808 31.081 128.826 31.133 ;
     RECT  71.316 30.911 71.838 31.145 ;
     RECT  123.12 30.991 123.138 31.145 ;
     RECT  125.676 30.479 125.874 31.261 ;
     RECT  73.944 31.225 73.962 31.325 ;
     RECT  76.932 31.261 77.094 31.379 ;
     RECT  125.64 31.261 125.874 31.379 ;
     RECT  75.24 31.261 75.258 31.415 ;
     RECT  2.415 30.713 2.697 31.531 ;
     RECT  77.076 31.379 77.094 31.685 ;
     RECT  3.816 30.875 3.834 31.801 ;
     RECT  5.58 30.839 6.246 31.801 ;
     RECT  121.215 30.989 122.022 31.919 ;
     RECT  3.816 31.801 4.014 31.955 ;
     RECT  121.215 31.919 121.878 31.955 ;
     RECT  129.492 31.891 129.51 31.997 ;
     RECT  124.812 32.071 124.83 32.189 ;
     RECT  123.12 31.891 123.138 32.225 ;
     RECT  2.34 31.531 2.697 32.395 ;
     RECT  4.644 32.431 4.662 32.477 ;
     RECT  2.304 32.395 2.697 32.495 ;
     RECT  3.816 31.955 3.834 32.611 ;
     RECT  4.788 32.611 4.806 32.729 ;
     RECT  3.564 32.611 3.834 32.765 ;
     RECT  125.856 31.379 125.874 32.881 ;
     RECT  126.615 30.479 126.897 32.881 ;
     RECT  128.808 32.827 128.826 32.999 ;
     RECT  125.856 32.881 126.897 33.043 ;
     RECT  124.92 33.019 124.938 33.071 ;
     RECT  78.015 13.289 78.297 33.241 ;
     RECT  102.78 33.007 102.798 33.241 ;
     RECT  2.415 32.495 2.697 33.259 ;
     RECT  102.564 33.241 102.798 33.269 ;
     RECT  125.856 33.043 127.134 33.269 ;
     RECT  102.564 33.269 102.582 33.341 ;
     RECT  79.956 33.421 79.974 33.539 ;
     RECT  5.58 31.801 6.714 33.547 ;
     RECT  2.304 33.259 2.697 33.575 ;
     RECT  79.056 33.421 79.074 33.575 ;
     RECT  3.816 32.765 3.834 33.691 ;
     RECT  4.608 33.583 4.626 33.691 ;
     RECT  128.844 33.511 128.862 33.725 ;
     RECT  72.615 30.911 72.897 33.787 ;
     RECT  3.816 33.691 4.806 33.809 ;
     RECT  77.976 33.241 78.297 33.809 ;
     RECT  3.816 33.809 4.698 33.845 ;
     RECT  123.948 33.787 123.966 33.845 ;
     RECT  72.615 33.787 73.278 33.961 ;
     RECT  125.856 33.269 126.897 33.961 ;
     RECT  5.544 33.547 6.714 34.051 ;
     RECT  75.636 33.961 75.654 34.079 ;
     RECT  124.128 33.961 124.146 34.079 ;
     RECT  5.508 34.051 6.714 34.087 ;
     RECT  74.196 33.961 74.214 34.115 ;
     RECT  124.92 33.961 126.897 34.115 ;
     RECT  101.916 34.051 101.934 34.151 ;
     RECT  2.412 33.575 2.697 34.157 ;
     RECT  78.015 33.809 78.297 34.231 ;
     RECT  72.288 33.961 73.422 34.321 ;
     RECT  5.508 34.087 6.894 34.349 ;
     RECT  4.68 33.845 4.698 34.385 ;
     RECT  79.236 34.123 79.578 34.385 ;
     RECT  67.215 29.759 67.497 34.429 ;
     RECT  66.096 34.321 66.114 34.465 ;
     RECT  67.215 34.429 67.554 34.501 ;
     RECT  69.048 34.465 69.066 34.501 ;
     RECT  72.288 34.321 73.458 34.501 ;
     RECT  128.808 34.501 128.826 34.589 ;
     RECT  76.932 34.501 76.95 34.619 ;
     RECT  125.64 34.115 126.897 34.619 ;
     RECT  69.048 34.501 69.21 34.781 ;
     RECT  72.288 34.501 73.602 34.781 ;
     RECT  66.096 34.465 66.258 34.889 ;
     RECT  2.415 34.157 2.697 34.987 ;
     RECT  72.288 34.781 72.897 34.987 ;
     RECT  70.164 34.891 70.182 35.005 ;
     RECT  79.38 34.385 79.578 35.005 ;
     RECT  61.815 27.905 62.097 35.041 ;
     RECT  63.864 35.005 63.882 35.041 ;
     RECT  67.176 34.501 67.554 35.041 ;
     RECT  70.164 35.005 70.578 35.041 ;
     RECT  71.784 34.987 72.897 35.041 ;
     RECT  78.015 34.231 78.354 35.041 ;
     RECT  79.38 35.005 79.65 35.041 ;
     RECT  123.228 34.843 123.246 35.041 ;
     RECT  125.64 34.619 125.874 35.041 ;
     RECT  50.76 30.989 51.642 35.131 ;
     RECT  61.308 35.041 62.802 35.159 ;
     RECT  79.38 35.041 79.794 35.159 ;
     RECT  123.228 35.041 123.39 35.159 ;
     RECT  50.724 35.131 51.642 35.168 ;
     RECT  76.032 34.795 76.05 35.182 ;
     RECT  2.415 34.987 2.754 35.195 ;
     RECT  61.416 35.159 62.802 35.195 ;
     RECT  63.576 35.041 63.882 35.195 ;
     RECT  69.516 35.041 70.722 35.195 ;
     RECT  78.015 35.041 78.426 35.195 ;
     RECT  80.568 35.041 80.73 35.195 ;
     RECT  102.024 34.861 102.042 35.195 ;
     RECT  124.164 35.041 124.182 35.195 ;
     RECT  70.164 35.195 70.722 35.231 ;
     RECT  58.104 35.203 58.122 35.275 ;
     RECT  78.015 35.195 78.297 35.275 ;
     RECT  5.544 34.349 6.894 35.311 ;
     RECT  7.815 27.869 8.097 35.311 ;
     RECT  60.192 35.275 60.21 35.311 ;
     RECT  74.376 34.501 74.394 35.311 ;
     RECT  52.776 35.311 52.794 35.323 ;
     RECT  58.104 35.275 58.158 35.323 ;
     RECT  61.815 35.195 62.802 35.323 ;
     RECT  79.38 35.159 79.65 35.323 ;
     RECT  52.776 35.323 53.298 35.357 ;
     RECT  57.816 35.323 58.158 35.357 ;
     RECT  61.815 35.323 63.45 35.357 ;
     RECT  79.164 35.323 79.65 35.357 ;
     RECT  57.816 35.357 58.122 35.429 ;
     RECT  59.652 35.311 60.21 35.429 ;
     RECT  63.288 35.357 63.45 35.429 ;
     RECT  66.672 35.041 68.274 35.429 ;
     RECT  71.748 35.041 72.897 35.429 ;
     RECT  76.176 35.311 76.194 35.429 ;
     RECT  4.572 35.311 4.59 35.465 ;
     RECT  52.992 35.357 53.298 35.465 ;
     RECT  59.652 35.429 59.67 35.465 ;
     RECT  67.176 35.429 68.202 35.465 ;
     RECT  71.748 35.429 71.766 35.465 ;
     RECT  74.088 35.311 74.682 35.465 ;
     RECT  77.292 35.275 78.297 35.465 ;
     RECT  80.604 35.195 80.73 35.465 ;
     RECT  128.808 35.419 128.826 35.465 ;
     RECT  50.76 35.168 51.642 35.473 ;
     RECT  126.615 34.619 126.897 35.545 ;
     RECT  50.76 35.473 51.858 35.573 ;
     RECT  56.415 26.699 56.697 35.581 ;
     RECT  125.532 35.041 125.874 35.581 ;
     RECT  126.615 35.545 127.098 35.581 ;
     RECT  46.764 35.437 46.782 35.609 ;
     RECT  54.216 35.581 54.234 35.671 ;
     RECT  4.644 35.659 4.662 35.699 ;
     RECT  55.98 35.581 56.697 35.699 ;
     RECT  63.432 35.429 63.45 35.699 ;
     RECT  74.088 35.465 74.106 35.699 ;
     RECT  122.76 35.545 122.778 35.699 ;
     RECT  64.224 35.581 64.422 35.735 ;
     RECT  54.216 35.671 54.882 35.771 ;
     RECT  121.215 31.955 121.497 35.845 ;
     RECT  3.816 33.845 3.834 35.851 ;
     RECT  64.404 35.735 64.422 35.851 ;
     RECT  125.532 35.581 127.098 35.851 ;
     RECT  79.164 35.357 79.326 35.885 ;
     RECT  121.215 35.845 121.842 35.885 ;
     RECT  80.712 35.465 80.73 35.941 ;
     RECT  4.788 35.851 4.806 35.969 ;
     RECT  60.408 35.851 60.426 35.969 ;
     RECT  64.404 35.851 64.458 35.969 ;
     RECT  79.308 35.885 79.326 35.969 ;
     RECT  82.044 35.851 82.494 35.969 ;
     RECT  102.384 35.671 102.402 35.969 ;
     RECT  123.696 35.611 124.002 35.969 ;
     RECT  3.564 35.851 3.834 36.005 ;
     RECT  82.476 35.969 82.494 36.005 ;
     RECT  59.22 35.851 59.418 36.041 ;
     RECT  64.44 35.969 64.458 36.041 ;
     RECT  80.712 35.941 80.91 36.041 ;
     RECT  76.356 35.941 76.374 36.085 ;
     RECT  52.992 35.465 53.01 36.121 ;
     RECT  54.144 36.121 54.162 36.211 ;
     RECT  105.015 2.413 105.297 36.211 ;
     RECT  5.544 35.311 8.097 36.239 ;
     RECT  57.816 35.429 57.978 36.239 ;
     RECT  77.76 35.465 78.297 36.275 ;
     RECT  125.424 35.851 127.098 36.275 ;
     RECT  128.808 36.283 128.826 36.32 ;
     RECT  125.856 36.275 127.098 36.355 ;
     RECT  52.884 36.121 53.01 36.391 ;
     RECT  54 36.211 54.162 36.391 ;
     RECT  56.415 35.699 56.697 36.391 ;
     RECT  57.816 36.239 57.834 36.391 ;
     RECT  67.176 35.465 67.497 36.391 ;
     RECT  70.164 35.231 70.29 36.391 ;
     RECT  64.584 36.391 64.746 36.461 ;
     RECT  123.696 35.969 123.714 36.461 ;
     RECT  69.696 36.391 70.29 36.475 ;
     RECT  68.616 36.391 68.634 36.481 ;
     RECT  64.728 36.461 64.746 36.509 ;
     RECT  69.696 36.475 70.974 36.509 ;
     RECT  76.356 36.085 76.842 36.509 ;
     RECT  82.656 36.391 82.674 36.509 ;
     RECT  125.856 36.355 127.134 36.509 ;
     RECT  55.584 36.391 55.602 36.523 ;
     RECT  56.415 36.391 57.834 36.523 ;
     RECT  55.584 36.523 57.834 36.545 ;
     RECT  65.52 36.391 65.61 36.545 ;
     RECT  77.796 36.275 78.297 36.545 ;
     RECT  104.472 36.211 105.297 36.545 ;
     RECT  56.052 36.545 57.834 36.557 ;
     RECT  76.824 36.509 76.842 36.557 ;
     RECT  68.616 36.481 68.814 36.581 ;
     RECT  59.22 36.041 59.274 36.625 ;
     RECT  61.815 35.357 62.097 36.661 ;
     RECT  65.592 36.545 65.61 36.661 ;
     RECT  80.712 36.041 80.73 36.661 ;
     RECT  56.052 36.557 57.438 36.689 ;
     RECT  2.415 35.195 2.697 36.715 ;
     RECT  61.815 36.661 62.802 36.779 ;
     RECT  73.836 36.661 73.854 36.779 ;
     RECT  2.304 36.715 2.697 36.815 ;
     RECT  60.048 36.661 60.066 36.815 ;
     RECT  65.592 36.661 65.682 36.815 ;
     RECT  52.884 36.391 54.162 36.895 ;
     RECT  6.696 36.239 8.097 36.923 ;
     RECT  3.816 36.005 3.834 36.931 ;
     RECT  4.788 36.763 4.806 36.931 ;
     RECT  5.544 36.239 5.742 36.931 ;
     RECT  70.38 36.509 70.974 36.931 ;
     RECT  52.884 36.895 54.198 36.959 ;
     RECT  80.568 36.661 80.73 37.003 ;
     RECT  54.18 36.959 54.198 37.021 ;
     RECT  59.112 36.625 59.274 37.021 ;
     RECT  66.564 36.391 67.497 37.021 ;
     RECT  78.015 36.545 78.297 37.021 ;
     RECT  80.568 37.003 80.982 37.037 ;
     RECT  3.816 36.931 5.742 37.049 ;
     RECT  54.18 37.021 54.63 37.049 ;
     RECT  69.588 36.931 69.606 37.049 ;
     RECT  70.38 36.931 71.154 37.049 ;
     RECT  80.712 37.037 80.982 37.049 ;
     RECT  66.096 37.021 67.497 37.051 ;
     RECT  3.816 37.049 4.302 37.085 ;
     RECT  70.38 37.049 70.974 37.085 ;
     RECT  66.096 37.051 68.238 37.091 ;
     RECT  34.815 26.789 35.097 37.285 ;
     RECT  72.615 35.429 72.897 37.285 ;
     RECT  13.215 2.413 13.497 37.291 ;
     RECT  24.015 2.413 24.297 37.291 ;
     RECT  54.288 37.049 54.63 37.319 ;
     RECT  58.68 37.021 59.274 37.319 ;
     RECT  66.096 37.091 67.497 37.319 ;
     RECT  68.22 37.091 68.238 37.319 ;
     RECT  34.704 37.285 35.097 37.325 ;
     RECT  38.772 37.147 38.79 37.325 ;
     RECT  13.104 37.291 13.497 37.328 ;
     RECT  23.904 37.291 24.297 37.328 ;
     RECT  76.032 37.291 76.734 37.328 ;
     RECT  57.42 36.689 57.438 37.355 ;
     RECT  66.708 37.319 67.497 37.355 ;
     RECT  78.015 37.021 78.714 37.435 ;
     RECT  80.964 37.049 80.982 37.435 ;
     RECT  124.596 37.429 124.614 37.469 ;
     RECT  56.052 36.689 56.697 37.471 ;
     RECT  62.928 37.051 62.946 37.471 ;
     RECT  74.664 37.399 74.682 37.471 ;
     RECT  76.176 37.328 76.734 37.471 ;
     RECT  77.544 37.435 78.714 37.471 ;
     RECT  80.964 37.435 81.27 37.471 ;
     RECT  125.856 36.509 126.897 37.471 ;
     RECT  2.415 36.815 2.697 37.561 ;
     RECT  82.188 37.471 82.206 37.561 ;
     RECT  83.415 21.929 83.697 37.561 ;
     RECT  2.415 37.561 2.898 37.579 ;
     RECT  60.84 37.051 60.858 37.579 ;
     RECT  61.815 36.779 62.097 37.579 ;
     RECT  80.964 37.471 81.414 37.579 ;
     RECT  82.188 37.561 83.697 37.579 ;
     RECT  65.196 37.435 65.214 37.589 ;
     RECT  76.176 37.471 78.714 37.589 ;
     RECT  124.776 37.471 124.794 37.589 ;
     RECT  60.84 37.579 62.097 37.597 ;
     RECT  72.615 37.285 73.458 37.597 ;
     RECT  2.412 37.579 2.898 37.625 ;
     RECT  5.256 37.049 5.742 37.625 ;
     RECT  60.228 37.597 62.097 37.625 ;
     RECT  63.9 37.471 63.918 37.625 ;
     RECT  69.156 37.051 69.318 37.625 ;
     RECT  74.376 37.471 74.718 37.625 ;
     RECT  80.964 37.579 83.697 37.625 ;
     RECT  104.184 37.291 104.202 37.625 ;
     RECT  125.568 37.471 126.897 37.625 ;
     RECT  82.872 37.625 83.697 37.733 ;
     RECT  60.984 37.625 62.097 37.741 ;
     RECT  62.928 37.471 63.126 37.741 ;
     RECT  76.356 37.589 78.714 37.741 ;
     RECT  60.984 37.741 63.126 37.859 ;
     RECT  69.3 37.625 69.318 37.859 ;
     RECT  71.784 37.741 71.802 37.859 ;
     RECT  80.964 37.625 81.918 37.859 ;
     RECT  60.228 37.625 60.246 37.895 ;
     RECT  70.56 37.085 70.974 37.895 ;
     RECT  74.484 37.625 74.718 37.895 ;
     RECT  2.415 37.625 2.898 38.011 ;
     RECT  3.816 37.085 3.834 38.011 ;
     RECT  5.436 37.625 5.742 38.011 ;
     RECT  6.876 36.923 8.097 38.011 ;
     RECT  55.836 37.471 56.697 38.011 ;
     RECT  64.836 37.819 64.998 38.011 ;
     RECT  67.215 37.355 67.497 38.011 ;
     RECT  61.38 37.859 63.126 38.101 ;
     RECT  122.832 38.011 122.85 38.101 ;
     RECT  64.44 38.011 64.998 38.129 ;
     RECT  67.215 38.011 68.094 38.129 ;
     RECT  70.668 37.895 70.974 38.129 ;
     RECT  76.356 37.741 79.218 38.129 ;
     RECT  122.688 38.101 122.85 38.129 ;
     RECT  128.808 37.147 128.826 38.129 ;
     RECT  57.636 37.561 57.654 38.137 ;
     RECT  55.368 38.011 56.697 38.141 ;
     RECT  122.688 38.129 122.706 38.141 ;
     RECT  2.415 38.011 3.834 38.165 ;
     RECT  61.38 38.101 63.378 38.165 ;
     RECT  64.548 38.129 64.566 38.165 ;
     RECT  65.772 38.011 65.79 38.165 ;
     RECT  59.364 37.741 59.382 38.173 ;
     RECT  82.98 37.733 83.697 38.173 ;
     RECT  61.815 38.165 63.378 38.201 ;
     RECT  54.612 37.319 54.63 38.281 ;
     RECT  55.368 38.141 55.386 38.281 ;
     RECT  72.615 37.597 73.566 38.281 ;
     RECT  5.436 38.011 8.097 38.309 ;
     RECT  57.492 38.137 57.654 38.371 ;
     RECT  59.364 38.173 59.49 38.371 ;
     RECT  61.815 38.201 62.946 38.381 ;
     RECT  58.932 38.371 59.49 38.399 ;
     RECT  70.668 38.129 70.686 38.399 ;
     RECT  76.356 38.129 76.374 38.399 ;
     RECT  80.352 38.101 80.37 38.399 ;
     RECT  81.36 37.859 81.918 38.399 ;
     RECT  103.536 38.011 103.554 38.399 ;
     RECT  124.92 38.173 124.938 38.399 ;
     RECT  72.216 38.281 73.674 38.435 ;
     RECT  75.024 38.137 75.042 38.435 ;
     RECT  77.364 38.129 79.218 38.435 ;
     RECT  81.36 38.399 81.774 38.435 ;
     RECT  82.98 38.173 83.898 38.435 ;
     RECT  57.492 38.371 57.69 38.471 ;
     RECT  58.932 38.399 58.95 38.471 ;
     RECT  83.232 38.435 83.697 38.471 ;
     RECT  77.508 38.435 79.218 38.515 ;
     RECT  125.856 37.625 126.897 38.635 ;
     RECT  67.215 38.129 67.497 38.641 ;
     RECT  72.615 38.435 73.674 38.669 ;
     RECT  77.508 38.515 79.542 38.669 ;
     RECT  125.856 38.635 127.278 38.675 ;
     RECT  66.924 38.641 67.497 38.683 ;
     RECT  78.015 38.669 78.93 38.705 ;
     RECT  125.856 38.675 127.098 38.705 ;
     RECT  61.815 38.381 62.91 38.813 ;
     RECT  128.844 38.713 128.862 38.909 ;
     RECT  75.096 38.821 75.114 38.911 ;
     RECT  5.652 38.309 8.097 38.939 ;
     RECT  54.612 38.281 55.386 38.939 ;
     RECT  65.484 38.677 65.646 38.939 ;
     RECT  76.104 38.821 76.122 38.939 ;
     RECT  125.856 38.705 126.897 38.939 ;
     RECT  122.472 38.911 122.49 38.957 ;
     RECT  4.824 38.713 4.842 38.975 ;
     RECT  75.096 38.911 75.294 38.975 ;
     RECT  75.276 38.975 75.294 39.011 ;
     RECT  56.232 38.141 56.697 39.019 ;
     RECT  123.696 38.137 123.714 39.091 ;
     RECT  68.292 38.551 68.31 39.181 ;
     RECT  65.268 39.091 65.286 39.209 ;
     RECT  73.908 38.821 73.926 39.209 ;
     RECT  122.616 39.091 122.634 39.209 ;
     RECT  123.408 39.091 124.146 39.209 ;
     RECT  56.232 39.019 57.042 39.211 ;
     RECT  57.924 39.091 57.942 39.211 ;
     RECT  123.408 39.209 123.426 39.245 ;
     RECT  56.232 39.211 57.942 39.259 ;
     RECT  61.815 38.813 62.118 39.289 ;
     RECT  70.092 39.181 70.11 39.289 ;
     RECT  81.756 38.435 81.774 39.289 ;
     RECT  83.415 38.471 83.697 39.289 ;
     RECT  62.892 38.813 62.91 39.293 ;
     RECT  2.415 38.165 2.934 39.307 ;
     RECT  56.232 39.259 58.122 39.317 ;
     RECT  66.708 38.683 67.497 39.341 ;
     RECT  70.092 39.289 70.506 39.341 ;
     RECT  59.292 39.217 59.31 39.361 ;
     RECT  64.44 39.325 64.458 39.361 ;
     RECT  66.816 39.341 67.497 39.361 ;
     RECT  68.292 39.181 68.418 39.361 ;
     RECT  81.504 39.289 81.774 39.361 ;
     RECT  71.856 39.289 71.874 39.451 ;
     RECT  72.615 38.669 72.897 39.451 ;
     RECT  58.788 39.361 59.31 39.479 ;
     RECT  70.092 39.341 70.11 39.479 ;
     RECT  84.816 39.361 84.834 39.479 ;
     RECT  2.415 39.307 2.97 39.515 ;
     RECT  61.164 39.289 62.118 39.515 ;
     RECT  64.224 39.361 64.458 39.515 ;
     RECT  66.816 39.361 68.418 39.515 ;
     RECT  71.856 39.451 72.897 39.515 ;
     RECT  72.036 39.515 72.897 39.551 ;
     RECT  81.504 39.361 81.918 39.595 ;
     RECT  3.816 38.165 3.834 39.631 ;
     RECT  78.015 38.705 78.297 39.631 ;
     RECT  79.812 39.355 80.154 39.631 ;
     RECT  81.144 39.595 81.918 39.631 ;
     RECT  5.688 38.939 6.39 39.721 ;
     RECT  66.816 39.515 67.842 39.749 ;
     RECT  77.832 39.631 78.297 39.749 ;
     RECT  79.812 39.631 81.918 39.749 ;
     RECT  3.672 39.631 3.834 39.785 ;
     RECT  67.215 39.749 67.698 39.785 ;
     RECT  77.94 39.749 78.297 39.785 ;
     RECT  124.164 39.739 124.182 39.785 ;
     RECT  128.808 39.739 128.826 39.785 ;
     RECT  3.816 39.785 3.834 39.865 ;
     RECT  80.136 39.749 81.918 39.865 ;
     RECT  83.232 39.289 83.697 39.865 ;
     RECT  125.856 38.939 125.874 39.865 ;
     RECT  126.615 38.939 126.897 39.865 ;
     RECT  74.376 39.865 74.394 39.901 ;
     RECT  80.136 39.865 83.697 39.901 ;
     RECT  125.46 39.865 125.874 39.901 ;
     RECT  126.615 39.865 127.134 39.901 ;
     RECT  3.816 39.865 4.374 39.917 ;
     RECT  74.376 39.901 74.574 39.917 ;
     RECT  61.632 39.515 62.118 39.979 ;
     RECT  56.232 39.317 58.05 40.019 ;
     RECT  64.836 39.721 65.034 40.019 ;
     RECT  74.556 39.917 74.574 40.019 ;
     RECT  75.996 39.865 76.626 40.019 ;
     RECT  80.136 39.901 83.862 40.019 ;
     RECT  84.852 39.901 85.662 40.019 ;
     RECT  75.996 40.019 76.014 40.055 ;
     RECT  83.196 40.019 83.697 40.055 ;
     RECT  84.852 40.019 84.87 40.055 ;
     RECT  85.644 40.019 85.662 40.055 ;
     RECT  125.46 39.901 127.134 40.055 ;
     RECT  2.415 39.515 2.697 40.171 ;
     RECT  58.032 40.019 58.05 40.171 ;
     RECT  58.788 39.479 59.166 40.171 ;
     RECT  61.632 39.979 62.478 40.171 ;
     RECT  72.615 39.551 72.897 40.171 ;
     RECT  78.015 39.785 78.297 40.171 ;
     RECT  5.292 39.721 6.39 40.199 ;
     RECT  61.632 40.171 62.622 40.261 ;
     RECT  58.032 40.171 59.166 40.289 ;
     RECT  64.836 40.019 64.854 40.289 ;
     RECT  80.136 40.019 81.81 40.289 ;
     RECT  125.856 40.055 127.134 40.289 ;
     RECT  63.396 40.171 63.414 40.325 ;
     RECT  79.38 40.171 79.398 40.325 ;
     RECT  80.136 40.289 81.09 40.325 ;
     RECT  61.02 40.261 62.622 40.361 ;
     RECT  72.615 40.171 73.098 40.411 ;
     RECT  58.788 40.289 59.166 40.441 ;
     RECT  60.012 40.171 60.03 40.441 ;
     RECT  71.82 40.261 71.838 40.441 ;
     RECT  71.1 40.441 71.838 40.445 ;
     RECT  58.788 40.441 60.03 40.459 ;
     RECT  58.788 40.459 60.426 40.493 ;
     RECT  80.136 40.325 80.946 40.493 ;
     RECT  78.015 40.171 78.642 40.531 ;
     RECT  70.164 40.441 70.182 40.559 ;
     RECT  71.1 40.445 71.298 40.559 ;
     RECT  77.436 40.531 78.642 40.559 ;
     RECT  71.1 40.559 71.118 40.595 ;
     RECT  72.615 40.411 73.314 40.595 ;
     RECT  128.808 40.531 128.826 40.637 ;
     RECT  3.816 39.917 4.086 40.675 ;
     RECT  61.344 40.361 62.622 40.711 ;
     RECT  69.84 40.675 69.858 40.711 ;
     RECT  3.816 40.675 4.482 40.733 ;
     RECT  105.015 36.545 105.297 40.801 ;
     RECT  61.344 40.711 62.802 40.829 ;
     RECT  65.592 40.711 65.682 40.829 ;
     RECT  68.58 40.711 68.742 40.829 ;
     RECT  69.516 40.711 69.858 40.829 ;
     RECT  125.856 40.289 127.062 40.829 ;
     RECT  63.576 40.711 63.594 40.865 ;
     RECT  69.516 40.829 69.534 40.865 ;
     RECT  75.096 40.711 75.762 40.865 ;
     RECT  80.82 40.493 80.946 40.865 ;
     RECT  124.668 40.795 124.686 40.865 ;
     RECT  64.548 40.801 64.566 40.901 ;
     RECT  74.268 40.711 74.358 40.981 ;
     RECT  83.415 40.055 83.697 40.981 ;
     RECT  125.856 40.829 126.897 40.981 ;
     RECT  67.215 39.785 67.497 41.083 ;
     RECT  59.688 40.493 60.426 41.099 ;
     RECT  80.928 40.865 80.946 41.099 ;
     RECT  82.908 40.981 83.754 41.099 ;
     RECT  85.824 40.981 85.95 41.099 ;
     RECT  105.015 40.801 105.606 41.099 ;
     RECT  64.692 41.071 64.71 41.117 ;
     RECT  66.708 41.083 67.497 41.135 ;
     RECT  81.828 40.981 82.026 41.135 ;
     RECT  82.908 41.099 83.697 41.135 ;
     RECT  84.852 40.981 84.87 41.135 ;
     RECT  85.932 41.099 85.95 41.135 ;
     RECT  77.436 40.559 78.534 41.215 ;
     RECT  61.344 40.829 62.73 41.251 ;
     RECT  65.628 40.829 65.682 41.251 ;
     RECT  67.215 41.135 67.497 41.251 ;
     RECT  75.24 40.865 75.762 41.251 ;
     RECT  77.4 41.215 78.534 41.261 ;
     RECT  64.836 41.251 64.854 41.369 ;
     RECT  70.776 41.251 70.794 41.369 ;
     RECT  77.58 41.261 78.534 41.369 ;
     RECT  81.9 41.135 82.026 41.369 ;
     RECT  2.304 40.171 2.697 41.405 ;
     RECT  61.308 41.251 62.73 41.405 ;
     RECT  67.215 41.251 68.13 41.405 ;
     RECT  75.24 41.251 75.798 41.405 ;
     RECT  124.02 41.371 124.038 41.411 ;
     RECT  125.748 40.981 126.897 41.449 ;
     RECT  122.544 40.801 122.562 41.513 ;
     RECT  3.816 40.733 3.834 41.521 ;
     RECT  5.292 40.199 5.418 41.521 ;
     RECT  6.372 40.199 6.39 41.521 ;
     RECT  74.268 40.981 74.466 41.549 ;
     RECT  6.336 41.521 6.39 41.611 ;
     RECT  7.236 38.939 8.097 41.611 ;
     RECT  65.628 41.251 66.438 41.611 ;
     RECT  106.668 41.341 106.686 41.611 ;
     RECT  5.292 41.521 5.562 41.639 ;
     RECT  75.456 41.405 75.69 41.639 ;
     RECT  106.452 41.611 106.686 41.639 ;
     RECT  124.992 41.449 126.897 41.639 ;
     RECT  5.292 41.639 5.454 41.645 ;
     RECT  65.484 41.611 66.438 41.675 ;
     RECT  75.456 41.639 75.474 41.675 ;
     RECT  124.992 41.639 125.01 41.675 ;
     RECT  106.452 41.639 106.47 41.711 ;
     RECT  125.856 41.639 126.897 41.711 ;
     RECT  71.82 41.521 71.838 41.755 ;
     RECT  61.308 41.405 62.586 41.791 ;
     RECT  71.64 41.755 71.838 41.791 ;
     RECT  88.815 3.983 89.097 41.791 ;
     RECT  65.628 41.675 66.438 41.881 ;
     RECT  67.215 41.405 67.497 41.881 ;
     RECT  81.9 41.369 81.954 41.899 ;
     RECT  6.336 41.611 8.097 41.909 ;
     RECT  72.615 40.595 72.954 41.909 ;
     RECT  88.704 41.791 89.097 41.909 ;
     RECT  65.628 41.881 67.497 41.945 ;
     RECT  81.792 41.899 81.954 41.945 ;
     RECT  3.816 41.521 4.014 42.061 ;
     RECT  71.28 41.791 71.838 42.061 ;
     RECT  72.615 41.909 72.897 42.061 ;
     RECT  83.415 41.135 83.697 42.061 ;
     RECT  85.824 41.899 85.842 42.061 ;
     RECT  87.732 42.025 87.75 42.061 ;
     RECT  60.624 41.791 62.586 42.151 ;
     RECT  70.344 41.707 70.506 42.151 ;
     RECT  78.015 41.369 78.534 42.151 ;
     RECT  90.144 42.139 90.162 42.151 ;
     RECT  64.332 42.061 64.35 42.179 ;
     RECT  70.092 42.151 70.506 42.179 ;
     RECT  74.268 41.549 74.286 42.179 ;
     RECT  81.936 41.945 81.954 42.179 ;
     RECT  85.824 42.061 86.022 42.187 ;
     RECT  3.816 42.061 4.554 42.215 ;
     RECT  6.336 41.909 6.57 42.215 ;
     RECT  82.98 42.061 83.826 42.215 ;
     RECT  85.824 42.187 86.166 42.221 ;
     RECT  77.976 42.151 78.534 42.295 ;
     RECT  79.848 42.151 79.866 42.331 ;
     RECT  87.3 42.061 87.75 42.331 ;
     RECT  121.215 35.885 121.497 42.331 ;
     RECT  5.292 41.645 5.418 42.359 ;
     RECT  60.624 42.151 63.162 42.449 ;
     RECT  74.34 42.331 74.358 42.449 ;
     RECT  77.976 42.295 78.786 42.449 ;
     RECT  87.3 42.331 87.822 42.449 ;
     RECT  121.215 42.331 121.554 42.449 ;
     RECT  128.808 41.467 128.826 42.449 ;
     RECT  90.144 42.151 90.486 42.461 ;
     RECT  75.204 42.331 75.402 42.485 ;
     RECT  77.184 42.151 77.202 42.485 ;
     RECT  83.124 42.215 83.826 42.485 ;
     RECT  86.148 42.221 86.166 42.485 ;
     RECT  61.524 42.449 63.162 42.493 ;
     RECT  125.856 41.711 125.874 42.565 ;
     RECT  126.615 41.711 126.897 42.565 ;
     RECT  65.628 41.945 66.078 42.601 ;
     RECT  68.976 41.791 68.994 42.601 ;
     RECT  71.28 42.061 72.897 42.601 ;
     RECT  83.415 42.485 83.826 42.601 ;
     RECT  87.3 42.449 87.75 42.601 ;
     RECT  66.852 41.945 67.497 42.691 ;
     RECT  61.524 42.493 63.702 42.719 ;
     RECT  65.304 42.601 66.078 42.719 ;
     RECT  70.092 42.179 70.182 42.719 ;
     RECT  70.956 42.601 72.897 42.719 ;
     RECT  79.848 42.331 80.118 42.719 ;
     RECT  2.415 41.405 2.697 42.727 ;
     RECT  3.816 42.215 4.482 42.727 ;
     RECT  65.412 42.719 66.078 42.755 ;
     RECT  68.94 42.601 69.03 42.755 ;
     RECT  70.956 42.719 71.154 42.755 ;
     RECT  75.24 42.485 75.402 42.755 ;
     RECT  79.848 42.719 79.902 42.755 ;
     RECT  83.415 42.601 84.222 42.755 ;
     RECT  87.12 42.601 87.75 42.755 ;
     RECT  123.804 42.421 123.822 42.755 ;
     RECT  65.952 42.755 66.078 42.763 ;
     RECT  66.852 42.691 67.914 42.763 ;
     RECT  2.415 42.727 4.482 42.797 ;
     RECT  70.092 42.719 70.11 42.797 ;
     RECT  125.856 42.565 126.897 42.871 ;
     RECT  75.816 42.763 75.834 42.989 ;
     RECT  62.964 42.719 63.702 43.025 ;
     RECT  70.992 42.755 71.154 43.025 ;
     RECT  3.816 42.797 4.482 43.141 ;
     RECT  68.94 42.755 68.994 43.141 ;
     RECT  78.015 42.449 78.786 43.141 ;
     RECT  82.08 42.763 82.098 43.141 ;
     RECT  125.64 42.871 126.897 43.141 ;
     RECT  6.336 42.215 6.354 43.169 ;
     RECT  62.964 43.025 63.126 43.169 ;
     RECT  63.9 43.141 64.422 43.231 ;
     RECT  65.952 42.763 67.914 43.231 ;
     RECT  71.928 42.719 72.897 43.231 ;
     RECT  86.328 42.601 86.346 43.231 ;
     RECT  125.64 43.141 127.134 43.231 ;
     RECT  3.816 43.141 4.626 43.259 ;
     RECT  62.964 43.169 63.054 43.259 ;
     RECT  68.868 43.141 68.994 43.259 ;
     RECT  71.136 43.025 71.154 43.259 ;
     RECT  78.015 43.141 78.93 43.259 ;
     RECT  81.792 43.141 82.242 43.259 ;
     RECT  125.424 43.231 127.134 43.259 ;
     RECT  128.808 43.195 128.826 43.259 ;
     RECT  85.932 43.231 86.346 43.291 ;
     RECT  3.816 43.259 4.014 43.295 ;
     RECT  68.976 43.259 68.994 43.295 ;
     RECT  71.928 43.231 72.99 43.295 ;
     RECT  74.052 43.141 74.178 43.295 ;
     RECT  76.752 43.141 76.77 43.295 ;
     RECT  78.015 43.259 78.498 43.295 ;
     RECT  79.704 43.141 79.722 43.295 ;
     RECT  81.792 43.259 81.882 43.295 ;
     RECT  126.615 43.259 127.134 43.295 ;
     RECT  0.108 43.195 0.126 43.325 ;
     RECT  124.344 43.267 124.362 43.325 ;
     RECT  65.952 43.231 68.058 43.331 ;
     RECT  80.748 43.231 80.766 43.331 ;
     RECT  88.815 41.909 89.097 43.411 ;
     RECT  87.732 42.755 87.75 43.501 ;
     RECT  88.596 43.411 89.097 43.501 ;
     RECT  83.415 42.755 84.114 43.528 ;
     RECT  85.14 43.411 85.158 43.529 ;
     RECT  85.932 43.291 86.67 43.529 ;
     RECT  106.776 43.231 106.794 43.529 ;
     RECT  85.932 43.529 85.95 43.565 ;
     RECT  87.732 43.501 89.097 43.565 ;
     RECT  125.424 43.259 125.874 43.565 ;
     RECT  61.524 42.719 62.154 43.609 ;
     RECT  62.964 43.259 62.982 43.609 ;
     RECT  63.9 43.231 64.494 43.609 ;
     RECT  2.415 42.797 2.697 43.627 ;
     RECT  82.98 43.528 84.114 43.645 ;
     RECT  78.015 43.295 78.297 43.681 ;
     RECT  80.568 43.531 80.73 43.681 ;
     RECT  82.98 43.645 85.086 43.681 ;
     RECT  7.524 41.909 8.097 43.709 ;
     RECT  3.816 43.295 3.834 43.771 ;
     RECT  75.96 43.141 75.978 43.771 ;
     RECT  63.9 43.609 64.89 43.799 ;
     RECT  82.764 43.681 85.086 43.799 ;
     RECT  2.304 43.627 2.697 43.835 ;
     RECT  61.524 43.609 62.982 43.835 ;
     RECT  72.615 43.295 72.99 43.843 ;
     RECT  74.052 43.295 74.142 43.843 ;
     RECT  29.415 2.413 29.697 43.915 ;
     RECT  64.008 43.799 64.89 43.915 ;
     RECT  65.952 43.331 67.842 43.915 ;
     RECT  72.615 43.843 73.026 43.915 ;
     RECT  73.98 43.843 74.142 43.915 ;
     RECT  75.276 43.771 75.978 43.915 ;
     RECT  64.008 43.915 67.842 43.949 ;
     RECT  29.415 43.915 29.862 44.059 ;
     RECT  70.092 43.771 70.11 44.069 ;
     RECT  72.615 43.915 74.142 44.069 ;
     RECT  128.808 44.041 128.826 44.093 ;
     RECT  3.42 43.771 3.834 44.105 ;
     RECT  65.412 43.949 67.842 44.105 ;
     RECT  71.244 43.771 71.262 44.105 ;
     RECT  5.4 42.359 5.418 44.107 ;
     RECT  126.615 43.295 126.897 44.185 ;
     RECT  87.732 43.565 88.074 44.221 ;
     RECT  88.815 43.565 89.097 44.221 ;
     RECT  29.415 44.059 30.15 44.249 ;
     RECT  6.48 44.221 6.498 44.311 ;
     RECT  81.504 43.681 81.522 44.311 ;
     RECT  29.415 44.249 29.862 44.339 ;
     RECT  87.3 44.221 88.074 44.339 ;
     RECT  88.815 44.221 89.73 44.339 ;
     RECT  82.8 43.799 85.086 44.375 ;
     RECT  106.884 44.041 106.902 44.375 ;
     RECT  5.4 44.107 5.67 44.383 ;
     RECT  62.964 43.835 62.982 44.383 ;
     RECT  66.6 44.105 67.842 44.383 ;
     RECT  125.856 43.565 125.874 44.383 ;
     RECT  3.816 44.105 3.834 44.419 ;
     RECT  73.692 44.069 74.142 44.419 ;
     RECT  75.276 43.915 76.014 44.419 ;
     RECT  77.076 43.681 78.297 44.419 ;
     RECT  123.84 44.383 123.858 44.429 ;
     RECT  77.076 44.419 78.678 44.443 ;
     RECT  80.388 43.681 80.73 44.443 ;
     RECT  81.504 44.311 81.738 44.443 ;
     RECT  62.964 44.383 63.27 44.447 ;
     RECT  80.388 44.443 81.738 44.455 ;
     RECT  73.692 44.419 76.014 44.477 ;
     RECT  87.3 44.339 87.894 44.477 ;
     RECT  66.6 44.383 67.914 44.491 ;
     RECT  72.615 44.069 72.897 44.491 ;
     RECT  73.836 44.477 76.014 44.491 ;
     RECT  5.4 44.383 5.742 44.609 ;
     RECT  66.6 44.491 68.094 44.609 ;
     RECT  70.56 44.311 70.758 44.609 ;
     RECT  73.836 44.491 76.194 44.609 ;
     RECT  80.388 44.455 81.954 44.609 ;
     RECT  126.615 44.185 127.134 44.609 ;
     RECT  3.816 44.419 4.554 44.645 ;
     RECT  66.6 44.609 68.022 44.645 ;
     RECT  70.56 44.609 70.578 44.645 ;
     RECT  72.396 44.491 72.897 44.645 ;
     RECT  73.908 44.609 75.906 44.645 ;
     RECT  81.072 44.609 81.738 44.645 ;
     RECT  125.208 44.383 125.874 44.645 ;
     RECT  65.412 44.105 65.43 44.725 ;
     RECT  5.4 44.609 5.418 44.753 ;
     RECT  65.376 44.725 65.43 44.851 ;
     RECT  72.615 44.645 72.897 44.851 ;
     RECT  87.3 44.477 87.678 44.851 ;
     RECT  65.376 44.851 65.754 44.879 ;
     RECT  122.688 44.827 122.706 44.879 ;
     RECT  128.808 44.851 128.826 44.957 ;
     RECT  69.552 44.443 69.57 44.995 ;
     RECT  77.04 44.443 78.678 44.995 ;
     RECT  66.672 44.645 68.022 45.005 ;
     RECT  81.072 44.645 81.27 45.023 ;
     RECT  69.084 44.995 69.606 45.031 ;
     RECT  79.812 44.851 79.83 45.031 ;
     RECT  87.228 44.851 87.678 45.031 ;
     RECT  124.056 44.995 124.074 45.031 ;
     RECT  76.716 44.995 78.678 45.121 ;
     RECT  69.084 45.031 69.966 45.149 ;
     RECT  76.716 45.121 78.75 45.149 ;
     RECT  81.252 45.023 81.27 45.149 ;
     RECT  83.415 44.375 84.978 45.149 ;
     RECT  86.04 45.031 87.678 45.149 ;
     RECT  90.648 44.995 90.666 45.149 ;
     RECT  107.532 44.887 107.55 45.149 ;
     RECT  124.056 45.031 124.29 45.149 ;
     RECT  67.104 45.005 68.022 45.185 ;
     RECT  71.352 44.851 71.37 45.185 ;
     RECT  74.016 44.645 75.906 45.185 ;
     RECT  79.524 45.031 79.83 45.185 ;
     RECT  82.584 44.995 82.602 45.185 ;
     RECT  84.636 45.149 84.654 45.185 ;
     RECT  86.04 45.149 86.058 45.185 ;
     RECT  87.228 45.149 87.246 45.185 ;
     RECT  88.815 44.339 89.298 45.185 ;
     RECT  91.872 44.995 91.89 45.185 ;
     RECT  124.056 45.149 124.074 45.185 ;
     RECT  77.976 45.149 78.75 45.221 ;
     RECT  2.415 43.835 2.697 45.355 ;
     RECT  2.304 45.355 2.697 45.455 ;
     RECT  65.7 44.879 65.754 45.455 ;
     RECT  2.415 45.455 2.697 45.571 ;
     RECT  3.816 44.645 3.834 45.571 ;
     RECT  64.008 43.949 64.602 45.571 ;
     RECT  72.615 44.851 72.954 45.571 ;
     RECT  74.664 45.185 75.906 45.571 ;
     RECT  76.716 45.149 77.202 45.571 ;
     RECT  64.008 45.571 64.89 45.599 ;
     RECT  68.292 45.571 68.418 45.689 ;
     RECT  69.552 45.149 69.714 45.689 ;
     RECT  68.4 45.689 68.418 45.725 ;
     RECT  71.856 45.571 71.874 45.725 ;
     RECT  72.615 45.571 73.566 45.725 ;
     RECT  74.664 45.571 77.202 45.725 ;
     RECT  6.48 44.311 6.606 45.769 ;
     RECT  7.815 43.709 8.097 45.769 ;
     RECT  6.48 45.769 8.097 45.805 ;
     RECT  121.215 42.449 121.497 45.805 ;
     RECT  67.104 45.185 67.497 45.841 ;
     RECT  81.72 45.805 81.738 45.841 ;
     RECT  83.415 45.149 83.697 45.841 ;
     RECT  121.215 45.805 121.878 45.841 ;
     RECT  125.856 44.645 125.874 45.841 ;
     RECT  126.615 44.609 126.897 45.841 ;
     RECT  6.408 45.805 8.097 45.869 ;
     RECT  81.72 45.841 81.918 45.869 ;
     RECT  74.664 45.725 75.402 45.931 ;
     RECT  6.552 45.869 6.606 45.959 ;
     RECT  73.944 45.931 75.402 45.959 ;
     RECT  81.9 45.869 81.918 45.959 ;
     RECT  125.028 45.841 125.046 45.959 ;
     RECT  128.808 45.787 128.826 45.959 ;
     RECT  107.604 45.931 107.622 45.967 ;
     RECT  5.04 45.841 5.058 45.995 ;
     RECT  76.5 45.725 77.202 45.995 ;
     RECT  77.976 45.221 78.534 45.995 ;
     RECT  79.308 45.841 79.398 45.995 ;
     RECT  85.896 45.931 85.914 45.995 ;
     RECT  121.215 45.841 122.022 45.995 ;
     RECT  122.796 45.841 122.814 45.995 ;
     RECT  90.612 46.003 90.63 46.075 ;
     RECT  125.856 45.841 126.897 46.075 ;
     RECT  107.604 45.967 107.802 46.103 ;
     RECT  82.692 45.841 83.697 46.111 ;
     RECT  88.815 45.185 89.097 46.111 ;
     RECT  107.784 46.103 107.802 46.139 ;
     RECT  90.612 46.075 90.666 46.157 ;
     RECT  121.215 45.995 121.878 46.157 ;
     RECT  2.415 45.571 3.834 46.219 ;
     RECT  78.015 45.995 78.534 46.219 ;
     RECT  76.824 45.995 77.202 46.229 ;
     RECT  90.612 46.157 90.63 46.229 ;
     RECT  125.856 46.075 127.134 46.229 ;
     RECT  76.824 46.229 77.058 46.253 ;
     RECT  2.304 46.219 3.834 46.265 ;
     RECT  6.588 45.959 6.606 46.265 ;
     RECT  87.984 46.111 89.097 46.265 ;
     RECT  91.98 46.111 91.998 46.265 ;
     RECT  2.415 46.265 3.834 46.381 ;
     RECT  87.12 46.111 87.138 46.459 ;
     RECT  2.415 46.381 4.23 46.535 ;
     RECT  72.615 45.725 72.897 46.603 ;
     RECT  73.944 45.959 74.682 46.603 ;
     RECT  69.552 45.689 69.57 46.637 ;
     RECT  71.82 46.603 71.838 46.651 ;
     RECT  72.615 46.603 74.682 46.651 ;
     RECT  82.692 46.111 84.402 46.651 ;
     RECT  87.12 46.459 87.75 46.651 ;
     RECT  125.856 46.229 127.062 46.651 ;
     RECT  128.268 46.645 128.286 46.685 ;
     RECT  66.672 45.841 67.497 46.747 ;
     RECT  71.208 46.651 74.682 46.747 ;
     RECT  88.524 46.265 89.097 46.747 ;
     RECT  71.208 46.747 74.79 46.769 ;
     RECT  78.015 46.219 79.11 46.769 ;
     RECT  82.044 46.651 84.438 46.769 ;
     RECT  86.04 46.111 86.058 46.769 ;
     RECT  87.012 46.651 87.75 46.769 ;
     RECT  125.604 46.651 127.062 46.769 ;
     RECT  71.208 46.769 71.262 46.805 ;
     RECT  72.615 46.769 74.79 46.805 ;
     RECT  75.564 46.651 75.582 46.805 ;
     RECT  76.824 46.253 76.986 46.805 ;
     RECT  80.424 46.651 80.442 46.805 ;
     RECT  82.584 46.769 84.438 46.805 ;
     RECT  87.012 46.769 87.678 46.805 ;
     RECT  74.196 46.805 74.79 46.849 ;
     RECT  66.672 46.747 67.59 46.877 ;
     RECT  74.196 46.849 75.33 46.877 ;
     RECT  88.524 46.747 89.19 46.877 ;
     RECT  87.552 46.805 87.678 46.883 ;
     RECT  93.06 46.111 93.078 46.921 ;
     RECT  124.2 46.747 124.218 46.921 ;
     RECT  87.552 46.883 87.57 46.949 ;
     RECT  93.06 46.921 93.438 47.039 ;
     RECT  124.2 46.921 124.362 47.039 ;
     RECT  91.152 46.921 91.17 47.075 ;
     RECT  108.18 46.813 108.198 47.075 ;
     RECT  81.36 46.843 81.378 47.131 ;
     RECT  68.832 46.651 69.354 47.191 ;
     RECT  91.944 46.921 91.962 47.191 ;
     RECT  90.216 46.885 90.234 47.261 ;
     RECT  68.724 47.191 69.354 47.275 ;
     RECT  3.816 46.535 4.23 47.281 ;
     RECT  5.616 47.275 5.634 47.281 ;
     RECT  2.415 46.535 2.934 47.309 ;
     RECT  68.58 47.275 69.354 47.309 ;
     RECT  91.548 47.191 91.962 47.309 ;
     RECT  5.616 47.281 5.706 47.315 ;
     RECT  68.58 47.309 68.598 47.315 ;
     RECT  72.615 46.805 73.35 47.315 ;
     RECT  80.964 47.131 81.378 47.315 ;
     RECT  123.408 47.275 123.426 47.315 ;
     RECT  124.2 47.039 124.218 47.323 ;
     RECT  91.548 47.309 91.566 47.345 ;
     RECT  123.48 47.323 124.218 47.357 ;
     RECT  69.336 47.309 69.354 47.461 ;
     RECT  70.092 46.651 70.11 47.461 ;
     RECT  82.62 46.805 84.438 47.461 ;
     RECT  125.928 46.769 127.062 47.461 ;
     RECT  110.415 2.413 110.697 47.551 ;
     RECT  5.688 47.315 5.706 47.579 ;
     RECT  72.615 47.315 72.954 47.579 ;
     RECT  74.34 46.877 75.33 47.579 ;
     RECT  79.452 47.227 79.974 47.579 ;
     RECT  82.62 47.461 84.906 47.579 ;
     RECT  128.808 47.515 128.826 47.579 ;
     RECT  3.816 47.281 4.626 47.615 ;
     RECT  69.336 47.461 70.326 47.615 ;
     RECT  76.752 47.281 76.77 47.615 ;
     RECT  79.452 47.579 79.47 47.615 ;
     RECT  81.288 47.315 81.378 47.615 ;
     RECT  83.232 47.579 84.402 47.615 ;
     RECT  125.928 47.461 127.134 47.615 ;
     RECT  121.215 46.157 121.497 47.659 ;
     RECT  123.48 47.357 123.498 47.693 ;
     RECT  71.244 46.805 71.262 47.695 ;
     RECT  85.824 47.461 85.842 47.731 ;
     RECT  86.976 47.695 86.994 47.731 ;
     RECT  88.524 46.877 89.097 47.731 ;
     RECT  94.215 19.499 94.497 47.731 ;
     RECT  125.028 47.323 125.046 47.731 ;
     RECT  125.928 47.615 126.897 47.731 ;
     RECT  125.028 47.731 126.897 47.741 ;
     RECT  93.384 47.039 93.402 47.821 ;
     RECT  94.215 47.731 94.554 47.821 ;
     RECT  69.336 47.615 69.534 47.849 ;
     RECT  85.824 47.731 87.138 47.849 ;
     RECT  92.448 47.731 92.61 47.849 ;
     RECT  93.384 47.821 94.554 47.849 ;
     RECT  125.208 47.741 126.897 47.849 ;
     RECT  66.672 46.877 67.497 47.857 ;
     RECT  81.36 47.615 81.378 47.857 ;
     RECT  74.34 47.579 75.294 47.885 ;
     RECT  81.36 47.857 81.522 47.885 ;
     RECT  85.824 47.849 86.994 47.885 ;
     RECT  87.912 47.731 89.514 47.885 ;
     RECT  109.908 47.551 110.697 47.885 ;
     RECT  83.415 47.615 84.402 47.921 ;
     RECT  0.108 47.857 0.126 47.981 ;
     RECT  70.452 47.695 71.262 48.119 ;
     RECT  3.816 47.615 4.554 48.155 ;
     RECT  70.452 48.119 70.47 48.155 ;
     RECT  71.244 48.119 71.262 48.155 ;
     RECT  6.552 47.281 6.57 48.271 ;
     RECT  78.015 46.769 78.642 48.271 ;
     RECT  121.215 47.659 121.59 48.271 ;
     RECT  78.015 48.271 79.038 48.361 ;
     RECT  83.415 47.921 84.186 48.361 ;
     RECT  69.336 47.849 69.39 48.389 ;
     RECT  76.032 48.271 76.194 48.389 ;
     RECT  121.215 48.271 121.77 48.389 ;
     RECT  88.308 47.885 89.514 48.397 ;
     RECT  91.44 48.361 91.458 48.397 ;
     RECT  74.736 47.885 75.294 48.425 ;
     RECT  76.968 48.271 76.986 48.425 ;
     RECT  6.552 48.271 6.606 48.427 ;
     RECT  76.032 48.389 76.05 48.461 ;
     RECT  77.94 48.361 79.038 48.461 ;
     RECT  5.976 48.427 6.606 48.541 ;
     RECT  7.344 45.869 8.097 48.541 ;
     RECT  83.232 48.361 84.186 48.541 ;
     RECT  93.384 47.849 94.497 48.541 ;
     RECT  3.816 48.155 4.23 48.569 ;
     RECT  85.248 48.541 85.266 48.631 ;
     RECT  86.112 47.885 86.67 48.631 ;
     RECT  69.336 48.389 69.354 48.659 ;
     RECT  74.988 48.425 75.186 48.659 ;
     RECT  82.584 48.541 84.186 48.659 ;
     RECT  88.308 48.397 89.73 48.659 ;
     RECT  90.648 48.541 90.666 48.659 ;
     RECT  91.44 48.397 92.178 48.659 ;
     RECT  107.856 48.271 107.874 48.659 ;
     RECT  125.388 47.849 126.897 48.659 ;
     RECT  129.492 48.379 129.51 48.659 ;
     RECT  74.988 48.659 75.006 48.695 ;
     RECT  82.584 48.659 83.826 48.695 ;
     RECT  85.248 48.631 86.67 48.695 ;
     RECT  88.815 48.659 89.73 48.695 ;
     RECT  91.44 48.659 91.71 48.695 ;
     RECT  93.06 48.541 94.497 48.695 ;
     RECT  123.12 48.397 123.138 48.695 ;
     RECT  85.5 48.695 85.95 48.731 ;
     RECT  3.816 48.569 3.834 48.811 ;
     RECT  66.672 47.857 68.094 48.811 ;
     RECT  5.976 48.541 8.097 48.845 ;
     RECT  78.015 48.461 79.038 48.901 ;
     RECT  6.12 48.845 8.097 48.929 ;
     RECT  66.672 48.811 68.346 48.929 ;
     RECT  93.204 48.695 93.402 48.929 ;
     RECT  3.564 48.811 3.834 48.965 ;
     RECT  82.656 48.695 83.826 48.965 ;
     RECT  93.204 48.929 93.222 48.965 ;
     RECT  78.015 48.901 79.074 49.037 ;
     RECT  81.504 47.885 81.522 49.081 ;
     RECT  73.8 47.899 73.818 49.199 ;
     RECT  79.2 49.081 79.218 49.199 ;
     RECT  80.208 49.081 81.522 49.199 ;
     RECT  70.236 49.003 70.254 49.235 ;
     RECT  80.208 49.199 80.226 49.235 ;
     RECT  81.288 49.199 81.306 49.235 ;
     RECT  82.764 48.965 83.826 49.235 ;
     RECT  83.016 49.235 83.697 49.271 ;
     RECT  128.808 49.243 128.826 49.28 ;
     RECT  78.015 49.037 78.297 49.351 ;
     RECT  94.14 48.695 94.497 49.351 ;
     RECT  94.14 49.351 95.13 49.373 ;
     RECT  90.144 49.351 90.162 49.441 ;
     RECT  74.124 49.351 74.142 49.469 ;
     RECT  77.472 49.351 78.297 49.469 ;
     RECT  88.815 48.695 89.37 49.469 ;
     RECT  91.62 48.695 91.71 49.469 ;
     RECT  96.48 49.351 96.498 49.469 ;
     RECT  121.215 48.389 121.59 49.469 ;
     RECT  125.424 48.659 126.897 49.469 ;
     RECT  71.172 49.351 71.19 49.505 ;
     RECT  74.916 49.351 74.934 49.505 ;
     RECT  86.904 49.351 87.714 49.505 ;
     RECT  90.144 49.441 90.738 49.505 ;
     RECT  91.692 49.469 91.71 49.505 ;
     RECT  94.215 49.373 95.13 49.505 ;
     RECT  109.044 49.171 109.062 49.505 ;
     RECT  123.912 49.171 123.93 49.505 ;
     RECT  90.72 49.505 90.738 49.541 ;
     RECT  85.932 48.731 85.95 49.565 ;
     RECT  2.415 47.309 2.697 49.675 ;
     RECT  87.228 49.505 87.462 49.739 ;
     RECT  2.304 49.675 2.697 49.775 ;
     RECT  87.228 49.739 87.246 49.775 ;
     RECT  3.816 48.965 3.834 49.855 ;
     RECT  2.415 49.775 2.697 49.891 ;
     RECT  3.492 49.855 3.834 49.891 ;
     RECT  2.415 49.891 4.446 50.045 ;
     RECT  3.492 50.045 4.446 50.141 ;
     RECT  124.884 50.107 124.902 50.153 ;
     RECT  94.215 49.505 94.497 50.155 ;
     RECT  6.552 48.929 8.097 50.279 ;
     RECT  70.092 50.203 70.11 50.279 ;
     RECT  93.96 50.155 94.497 50.279 ;
     RECT  82.656 50.251 82.674 50.315 ;
     RECT  90.972 50.251 90.99 50.315 ;
     RECT  78.015 49.469 78.297 50.395 ;
     RECT  125.856 49.469 126.897 50.395 ;
     RECT  106.596 50.251 106.614 50.423 ;
     RECT  70.632 50.323 70.65 50.431 ;
     RECT  72.615 47.579 72.897 50.431 ;
     RECT  74.988 50.395 75.006 50.431 ;
     RECT  77.76 50.395 78.297 50.431 ;
     RECT  83.415 49.271 83.697 50.431 ;
     RECT  85.212 50.203 85.23 50.431 ;
     RECT  88.815 49.469 89.097 50.431 ;
     RECT  94.104 50.279 94.497 50.431 ;
     RECT  77.76 50.431 78.714 50.459 ;
     RECT  2.415 50.045 2.697 50.539 ;
     RECT  72.615 50.431 73.674 50.549 ;
     RECT  74.988 50.431 75.15 50.549 ;
     RECT  77.904 50.459 78.714 50.549 ;
     RECT  81.036 50.431 81.126 50.549 ;
     RECT  82.8 50.431 83.898 50.549 ;
     RECT  84.708 50.431 85.374 50.549 ;
     RECT  88.416 50.431 89.097 50.549 ;
     RECT  91.116 50.431 91.134 50.549 ;
     RECT  125.856 50.395 127.098 50.549 ;
     RECT  2.304 50.539 2.697 50.585 ;
     RECT  73.656 50.549 73.674 50.585 ;
     RECT  75.924 50.431 76.05 50.585 ;
     RECT  76.968 50.431 76.986 50.585 ;
     RECT  78.015 50.549 78.714 50.585 ;
     RECT  81.108 50.549 81.126 50.585 ;
     RECT  83.415 50.549 83.898 50.585 ;
     RECT  84.78 50.549 84.798 50.585 ;
     RECT  86.148 50.431 86.166 50.585 ;
     RECT  88.524 50.549 89.097 50.585 ;
     RECT  91.908 50.431 92.07 50.585 ;
     RECT  94.104 50.431 95.49 50.585 ;
     RECT  79.488 50.521 79.506 50.621 ;
     RECT  86.94 50.521 86.958 50.621 ;
     RECT  3.528 50.141 4.446 50.701 ;
     RECT  74.988 50.549 75.006 50.717 ;
     RECT  124.308 50.731 124.326 50.819 ;
     RECT  3.528 50.701 5.022 50.855 ;
     RECT  75.96 50.585 76.05 50.855 ;
     RECT  95.292 50.585 95.49 50.855 ;
     RECT  69.192 48.973 69.21 50.971 ;
     RECT  125.856 50.549 126.897 50.971 ;
     RECT  6.912 50.279 8.097 50.999 ;
     RECT  110.415 47.885 110.697 51.061 ;
     RECT  68.832 50.971 69.21 51.089 ;
     RECT  124.452 50.971 124.47 51.089 ;
     RECT  125.244 50.971 126.897 51.125 ;
     RECT  110.415 51.061 111.078 51.233 ;
     RECT  70.632 50.431 71.046 51.241 ;
     RECT  88.815 50.585 89.097 51.241 ;
     RECT  93.132 50.431 93.15 51.241 ;
     RECT  94.104 50.585 94.497 51.241 ;
     RECT  78.015 50.585 78.297 51.307 ;
     RECT  96.804 51.241 96.822 51.331 ;
     RECT  97.596 51.241 97.614 51.331 ;
     RECT  91.98 50.585 92.07 51.359 ;
     RECT  95.508 51.241 95.742 51.359 ;
     RECT  96.804 51.331 97.614 51.359 ;
     RECT  93.06 51.241 94.497 51.395 ;
     RECT  2.415 50.585 2.697 51.397 ;
     RECT  96.804 51.359 97.074 51.431 ;
     RECT  2.415 51.397 2.826 51.437 ;
     RECT  83.415 50.585 83.697 51.475 ;
     RECT  3.816 50.855 5.022 51.511 ;
     RECT  70.632 51.241 71.226 51.511 ;
     RECT  75.636 51.475 75.798 51.511 ;
     RECT  78.015 51.307 78.498 51.511 ;
     RECT  83.415 51.475 84.078 51.511 ;
     RECT  88.815 51.241 90.09 51.511 ;
     RECT  72.615 50.549 72.897 51.601 ;
     RECT  76.572 51.511 76.59 51.601 ;
     RECT  77.364 51.511 78.678 51.601 ;
     RECT  75.024 51.511 75.798 51.629 ;
     RECT  76.572 51.601 78.678 51.629 ;
     RECT  81.576 51.511 81.666 51.629 ;
     RECT  83.415 51.511 84.222 51.629 ;
     RECT  88.236 51.511 90.09 51.629 ;
     RECT  70.164 51.511 71.802 51.665 ;
     RECT  75.132 51.629 75.654 51.665 ;
     RECT  76.572 51.629 78.297 51.665 ;
     RECT  79.452 51.511 79.47 51.665 ;
     RECT  81.648 51.629 81.666 51.665 ;
     RECT  86.58 51.511 86.706 51.665 ;
     RECT  93.06 51.395 93.33 51.665 ;
     RECT  75.636 51.665 75.654 51.677 ;
     RECT  72.615 51.601 73.422 51.701 ;
     RECT  77.076 51.665 77.094 51.701 ;
     RECT  84.996 51.511 85.014 51.835 ;
     RECT  83.415 51.629 84.078 51.869 ;
     RECT  128.808 50.107 128.826 51.869 ;
     RECT  110.415 51.233 110.697 51.871 ;
     RECT  125.856 51.125 126.897 51.899 ;
     RECT  88.236 51.629 89.262 51.965 ;
     RECT  86.292 52.015 86.31 52.051 ;
     RECT  90.036 51.629 90.09 52.051 ;
     RECT  94.215 51.395 94.497 52.051 ;
     RECT  95.508 51.359 95.67 52.051 ;
     RECT  125.856 51.899 125.874 52.051 ;
     RECT  6.912 50.999 6.93 52.079 ;
     RECT  94.215 52.051 95.67 52.141 ;
     RECT  70.164 51.665 71.694 52.169 ;
     RECT  88.815 51.965 89.262 52.169 ;
     RECT  91.404 51.871 91.746 52.169 ;
     RECT  93.708 52.141 95.67 52.169 ;
     RECT  125.46 52.051 125.874 52.169 ;
     RECT  90.036 52.051 90.594 52.205 ;
     RECT  92.52 52.051 92.538 52.205 ;
     RECT  93.708 52.169 95.526 52.205 ;
     RECT  124.704 52.051 124.722 52.205 ;
     RECT  93.708 52.205 94.497 52.241 ;
     RECT  83.415 51.869 83.697 52.321 ;
     RECT  84.924 51.835 85.014 52.321 ;
     RECT  86.22 52.051 86.31 52.321 ;
     RECT  5.904 51.511 5.922 52.411 ;
     RECT  84.924 52.321 85.374 52.439 ;
     RECT  90.252 52.205 90.486 52.439 ;
     RECT  3.816 51.511 5.13 52.445 ;
     RECT  96.444 52.051 96.606 52.459 ;
     RECT  86.148 52.321 86.31 52.475 ;
     RECT  90.252 52.439 90.27 52.475 ;
     RECT  95.508 52.205 95.526 52.493 ;
     RECT  2.415 51.437 2.697 52.591 ;
     RECT  110.232 51.871 110.697 52.681 ;
     RECT  71.028 52.169 71.694 52.699 ;
     RECT  5.904 52.411 6.642 52.745 ;
     RECT  71.028 52.699 71.766 52.745 ;
     RECT  78.015 51.665 78.297 52.825 ;
     RECT  7.815 50.999 8.097 52.861 ;
     RECT  72.615 51.701 72.897 52.861 ;
     RECT  77.436 52.825 78.297 52.861 ;
     RECT  82.908 52.321 83.697 52.861 ;
     RECT  86.256 52.475 86.31 52.861 ;
     RECT  121.215 49.469 121.497 52.861 ;
     RECT  126.615 51.899 126.897 52.861 ;
     RECT  77.328 52.861 78.93 52.925 ;
     RECT  6.768 52.861 6.786 52.979 ;
     RECT  77.436 52.925 78.93 52.979 ;
     RECT  81.432 52.861 81.594 52.979 ;
     RECT  121.215 52.861 121.59 52.979 ;
     RECT  128.808 52.699 128.826 52.979 ;
     RECT  82.692 52.861 83.697 52.987 ;
     RECT  94.215 52.241 94.497 52.987 ;
     RECT  96.408 52.459 96.606 52.987 ;
     RECT  98.352 52.861 98.37 52.987 ;
     RECT  126.615 52.861 126.954 52.987 ;
     RECT  72.615 52.861 73.53 53.015 ;
     RECT  75.996 52.861 76.122 53.015 ;
     RECT  77.508 52.979 78.93 53.015 ;
     RECT  82.224 52.987 83.697 53.015 ;
     RECT  110.016 52.681 110.697 53.015 ;
     RECT  122.364 52.861 122.382 53.015 ;
     RECT  81.432 52.979 81.45 53.021 ;
     RECT  86.256 52.861 86.634 53.021 ;
     RECT  2.415 52.591 2.862 53.131 ;
     RECT  91.404 52.169 91.422 53.131 ;
     RECT  91.404 53.131 91.458 53.249 ;
     RECT  92.34 52.987 92.358 53.285 ;
     RECT  96.048 52.987 96.93 53.285 ;
     RECT  97.668 52.987 98.37 53.285 ;
     RECT  82.224 53.015 82.386 53.309 ;
     RECT  93.312 53.221 93.33 53.321 ;
     RECT  2.304 53.131 2.862 53.401 ;
     RECT  3.816 52.445 5.022 53.401 ;
     RECT  83.16 53.015 83.697 53.401 ;
     RECT  84.924 52.439 84.942 53.401 ;
     RECT  86.256 53.021 86.418 53.401 ;
     RECT  88.815 52.169 89.097 53.401 ;
     RECT  96.336 53.285 96.93 53.401 ;
     RECT  123.768 52.051 123.93 53.401 ;
     RECT  83.16 53.401 85.086 53.405 ;
     RECT  80.424 53.401 80.55 53.519 ;
     RECT  82.368 53.309 82.386 53.519 ;
     RECT  85.068 53.405 85.086 53.519 ;
     RECT  96.336 53.401 97.506 53.519 ;
     RECT  2.304 53.401 5.022 53.555 ;
     RECT  80.532 53.519 80.55 53.555 ;
     RECT  83.16 53.405 84.222 53.555 ;
     RECT  96.336 53.519 97.362 53.555 ;
     RECT  122.544 53.401 122.562 53.555 ;
     RECT  123.768 53.401 124.254 53.555 ;
     RECT  88.344 53.401 89.298 53.563 ;
     RECT  90.036 53.491 90.054 53.563 ;
     RECT  94.068 52.987 94.497 53.563 ;
     RECT  98.316 53.285 98.37 53.563 ;
     RECT  125.856 52.169 125.874 53.563 ;
     RECT  126.615 52.987 127.134 53.563 ;
     RECT  88.344 53.563 90.054 53.591 ;
     RECT  3.636 53.555 5.022 53.597 ;
     RECT  72.615 53.015 73.134 53.597 ;
     RECT  92.592 53.527 92.754 53.597 ;
     RECT  97.344 53.555 97.362 53.597 ;
     RECT  123.768 53.555 123.786 53.597 ;
     RECT  129.492 53.491 129.51 53.597 ;
     RECT  5.004 53.597 5.022 53.671 ;
     RECT  5.904 52.745 5.922 53.671 ;
     RECT  74.34 53.563 74.358 53.671 ;
     RECT  94.068 53.563 95.202 53.671 ;
     RECT  74.34 53.671 74.826 53.789 ;
     RECT  77.508 53.015 78.297 53.789 ;
     RECT  96.336 53.555 96.354 53.789 ;
     RECT  111.564 53.527 111.582 53.789 ;
     RECT  125.64 53.563 127.134 53.789 ;
     RECT  74.34 53.789 74.61 53.825 ;
     RECT  75.816 53.491 75.834 53.825 ;
     RECT  85.86 53.401 86.418 53.825 ;
     RECT  93.816 53.671 95.202 53.825 ;
     RECT  98.316 53.563 98.514 53.825 ;
     RECT  125.64 53.789 126.897 53.825 ;
     RECT  74.556 53.825 74.61 53.861 ;
     RECT  86.364 53.825 86.418 53.995 ;
     RECT  90.864 53.401 90.882 54.031 ;
     RECT  92.736 53.597 92.754 54.059 ;
     RECT  98.316 53.825 98.406 54.059 ;
     RECT  2.304 53.555 2.697 54.095 ;
     RECT  88.344 53.591 89.73 54.103 ;
     RECT  86.364 53.995 86.85 54.211 ;
     RECT  90.648 54.031 90.882 54.211 ;
     RECT  82.188 54.283 82.206 54.329 ;
     RECT  85.464 54.031 85.482 54.329 ;
     RECT  86.364 54.211 86.994 54.329 ;
     RECT  87.84 54.103 89.73 54.329 ;
     RECT  123.336 54.283 123.354 54.329 ;
     RECT  86.364 54.329 86.382 54.365 ;
     RECT  87.84 54.329 89.097 54.365 ;
     RECT  90.648 54.211 90.954 54.365 ;
     RECT  78.015 53.789 78.297 54.379 ;
     RECT  74.556 53.861 74.574 54.413 ;
     RECT  3.636 53.597 3.834 54.445 ;
     RECT  83.232 53.555 83.697 54.445 ;
     RECT  98.316 54.059 98.37 54.445 ;
     RECT  3.6 54.445 3.834 54.481 ;
     RECT  5.004 53.671 5.922 54.481 ;
     RECT  78.015 54.379 78.642 54.481 ;
     RECT  83.232 54.445 84.402 54.481 ;
     RECT  99.615 20.615 99.897 54.481 ;
     RECT  125.64 53.825 125.874 54.481 ;
     RECT  78.015 54.481 79.182 54.509 ;
     RECT  98.208 54.445 98.37 54.509 ;
     RECT  72.615 53.597 72.897 54.571 ;
     RECT  125.316 54.481 125.874 54.571 ;
     RECT  126.615 53.825 126.897 54.571 ;
     RECT  3.6 54.481 5.922 54.599 ;
     RECT  76.968 54.481 77.094 54.599 ;
     RECT  78.015 54.509 78.39 54.599 ;
     RECT  80.496 54.481 80.586 54.599 ;
     RECT  82.332 54.481 82.35 54.599 ;
     RECT  83.124 54.481 84.402 54.599 ;
     RECT  87.876 54.365 88.038 54.599 ;
     RECT  90.756 54.365 90.954 54.599 ;
     RECT  98.352 54.509 98.37 54.599 ;
     RECT  100.836 54.481 100.854 54.599 ;
     RECT  123.48 54.481 123.498 54.599 ;
     RECT  125.316 54.571 126.897 54.599 ;
     RECT  128.808 54.427 128.826 54.599 ;
     RECT  75.492 54.481 75.51 54.635 ;
     RECT  77.076 54.599 77.094 54.635 ;
     RECT  79.164 54.509 79.182 54.635 ;
     RECT  80.568 54.599 80.586 54.635 ;
     RECT  83.124 54.599 84.078 54.635 ;
     RECT  87.876 54.599 87.894 54.635 ;
     RECT  90.756 54.599 90.774 54.635 ;
     RECT  99.144 54.481 99.897 54.635 ;
     RECT  112.176 54.301 112.194 54.635 ;
     RECT  124.272 54.481 124.29 54.635 ;
     RECT  94.215 53.825 94.986 54.643 ;
     RECT  3.6 54.599 4.554 54.653 ;
     RECT  99.576 54.635 99.897 54.707 ;
     RECT  2.415 54.095 2.697 54.859 ;
     RECT  94.215 54.643 95.13 54.869 ;
     RECT  95.904 54.751 96.534 54.905 ;
     RECT  91.728 54.949 91.746 55.003 ;
     RECT  2.34 54.859 2.697 55.175 ;
     RECT  96.3 54.905 96.534 55.175 ;
     RECT  7.56 52.861 8.097 55.243 ;
     RECT  5.292 54.599 5.922 55.255 ;
     RECT  6.84 55.243 8.097 55.255 ;
     RECT  5.292 55.255 8.097 55.409 ;
     RECT  91.728 55.003 91.818 55.409 ;
     RECT  128.232 55.291 128.25 55.409 ;
     RECT  92.736 55.021 93.294 55.445 ;
     RECT  123.732 55.387 123.75 55.445 ;
     RECT  72.615 54.571 73.494 55.561 ;
     RECT  78.015 54.599 78.297 55.561 ;
     RECT  79.2 55.291 79.218 55.561 ;
     RECT  83.415 54.635 84.078 55.561 ;
     RECT  86.976 55.291 86.994 55.561 ;
     RECT  98.82 55.291 98.838 55.561 ;
     RECT  99.615 54.707 99.897 55.561 ;
     RECT  76.104 55.525 76.122 55.565 ;
     RECT  74.664 55.381 74.682 55.589 ;
     RECT  84.996 55.561 85.014 55.651 ;
     RECT  86.256 55.561 87.138 55.651 ;
     RECT  6.228 55.409 8.097 55.679 ;
     RECT  79.2 55.561 79.362 55.679 ;
     RECT  83.415 55.561 84.222 55.679 ;
     RECT  84.996 55.651 87.138 55.679 ;
     RECT  89.928 55.561 89.946 55.679 ;
     RECT  92.34 55.531 92.43 55.679 ;
     RECT  94.215 54.869 94.698 55.679 ;
     RECT  96.948 55.561 97.074 55.679 ;
     RECT  123.912 55.561 123.93 55.679 ;
     RECT  124.704 55.561 125.046 55.679 ;
     RECT  77.076 55.561 78.297 55.715 ;
     RECT  84.996 55.679 85.626 55.715 ;
     RECT  86.364 55.679 87.138 55.715 ;
     RECT  87.912 55.561 87.93 55.715 ;
     RECT  95.472 55.561 95.49 55.715 ;
     RECT  97.056 55.679 97.074 55.715 ;
     RECT  111.924 55.381 111.942 55.715 ;
     RECT  124.704 55.679 124.722 55.715 ;
     RECT  85.212 55.715 85.626 55.751 ;
     RECT  3.816 54.653 4.554 55.831 ;
     RECT  5.292 55.409 5.31 55.831 ;
     RECT  98.82 55.561 99.954 55.831 ;
     RECT  98.82 55.831 99.99 55.901 ;
     RECT  86.652 55.715 87.138 55.915 ;
     RECT  6.228 55.679 6.39 55.949 ;
     RECT  77.184 55.715 78.297 55.949 ;
     RECT  92.412 55.679 92.43 55.949 ;
     RECT  98.028 55.867 98.046 55.957 ;
     RECT  3.816 55.831 5.31 55.985 ;
     RECT  77.184 55.949 77.202 55.985 ;
     RECT  83.415 55.679 83.697 56.065 ;
     RECT  99.252 55.901 99.99 56.093 ;
     RECT  83.376 56.065 83.697 56.101 ;
     RECT  88.815 54.365 89.097 56.101 ;
     RECT  97.704 55.957 98.046 56.129 ;
     RECT  128.808 56.101 128.826 56.189 ;
     RECT  83.124 56.101 83.697 56.219 ;
     RECT  86.652 55.915 87.57 56.219 ;
     RECT  90.108 56.101 90.126 56.219 ;
     RECT  93.348 55.831 93.474 56.219 ;
     RECT  125.856 54.599 126.897 56.219 ;
     RECT  83.232 56.219 83.697 56.255 ;
     RECT  84.456 56.101 84.474 56.255 ;
     RECT  87.12 56.219 87.138 56.255 ;
     RECT  88.344 56.101 89.097 56.255 ;
     RECT  93.348 56.219 93.366 56.255 ;
     RECT  83.376 56.255 83.697 56.285 ;
     RECT  85.212 55.751 85.23 56.291 ;
     RECT  80.136 55.561 80.154 56.335 ;
     RECT  81.576 55.561 81.666 56.335 ;
     RECT  78.015 55.949 78.297 56.347 ;
     RECT  79.2 55.679 79.218 56.347 ;
     RECT  80.064 56.335 80.154 56.371 ;
     RECT  78.015 56.347 79.218 56.381 ;
     RECT  120.348 56.335 120.366 56.381 ;
     RECT  99.252 56.093 99.897 56.429 ;
     RECT  7.56 55.679 8.097 56.489 ;
     RECT  81.576 56.335 81.774 56.489 ;
     RECT  99.396 56.429 99.897 56.489 ;
     RECT  101.988 56.371 102.366 56.489 ;
     RECT  111.636 56.191 111.654 56.489 ;
     RECT  122.94 56.371 123.138 56.489 ;
     RECT  78.015 56.381 78.678 56.525 ;
     RECT  81.576 56.489 81.594 56.525 ;
     RECT  100.728 56.371 100.746 56.525 ;
     RECT  102.348 56.489 102.366 56.525 ;
     RECT  122.94 56.489 122.958 56.525 ;
     RECT  2.415 55.175 2.697 56.587 ;
     RECT  74.988 56.569 75.006 56.605 ;
     RECT  72.615 55.561 73.566 56.641 ;
     RECT  80.064 56.371 80.19 56.641 ;
     RECT  95.796 56.635 95.814 56.641 ;
     RECT  80.064 56.641 80.226 56.669 ;
     RECT  95.796 56.641 95.958 56.675 ;
     RECT  80.172 56.669 80.226 56.717 ;
     RECT  96.732 56.641 96.75 56.731 ;
     RECT  97.704 56.129 97.722 56.731 ;
     RECT  80.172 56.717 80.19 56.759 ;
     RECT  95.94 56.675 95.958 56.759 ;
     RECT  96.732 56.731 97.722 56.759 ;
     RECT  78.015 56.525 78.534 56.795 ;
     RECT  96.732 56.759 97.29 56.795 ;
     RECT  2.304 56.587 2.697 56.911 ;
     RECT  92.88 56.683 92.898 56.911 ;
     RECT  94.215 55.679 94.497 56.911 ;
     RECT  76.14 56.641 76.158 56.971 ;
     RECT  74.988 56.605 75.222 57.005 ;
     RECT  5.292 55.985 5.31 57.029 ;
     RECT  94.104 56.911 94.806 57.029 ;
     RECT  2.304 56.911 2.97 57.037 ;
     RECT  3.816 55.985 4.554 57.037 ;
     RECT  88.815 56.255 89.097 57.037 ;
     RECT  92.304 56.911 92.898 57.053 ;
     RECT  119.7 57.001 119.718 57.053 ;
     RECT  91.44 57.019 91.566 57.065 ;
     RECT  94.104 57.029 94.497 57.065 ;
     RECT  124.164 57.019 124.182 57.065 ;
     RECT  88.2 57.037 89.097 57.101 ;
     RECT  85.608 57.145 85.626 57.181 ;
     RECT  88.38 57.101 89.097 57.181 ;
     RECT  125.856 56.219 125.874 57.181 ;
     RECT  126.615 56.219 126.897 57.181 ;
     RECT  92.304 57.053 92.322 57.209 ;
     RECT  2.304 57.037 4.554 57.299 ;
     RECT  120.24 57.181 120.258 57.299 ;
     RECT  113.976 57.271 113.994 57.307 ;
     RECT  2.304 57.299 2.97 57.335 ;
     RECT  86.58 57.181 86.922 57.335 ;
     RECT  91.548 57.065 91.566 57.335 ;
     RECT  124.344 57.181 124.362 57.335 ;
     RECT  125.136 57.181 126.897 57.335 ;
     RECT  85.608 57.181 85.806 57.341 ;
     RECT  125.568 57.335 126.897 57.415 ;
     RECT  113.976 57.307 114.174 57.443 ;
     RECT  76.032 56.971 76.158 57.451 ;
     RECT  99.615 56.489 99.897 57.451 ;
     RECT  114.156 57.443 114.174 57.479 ;
     RECT  78.015 56.795 78.297 57.541 ;
     RECT  81.864 57.307 81.882 57.541 ;
     RECT  97.272 56.795 97.29 57.541 ;
     RECT  101.376 57.451 101.394 57.541 ;
     RECT  97.128 57.541 97.29 57.547 ;
     RECT  76.032 57.451 76.194 57.569 ;
     RECT  81.288 57.541 81.882 57.569 ;
     RECT  85.788 57.341 85.806 57.569 ;
     RECT  86.688 57.335 86.814 57.569 ;
     RECT  99.18 57.451 99.897 57.569 ;
     RECT  103.536 57.451 103.554 57.569 ;
     RECT  125.568 57.415 127.098 57.569 ;
     RECT  101.376 57.541 102.114 57.595 ;
     RECT  86.688 57.569 86.706 57.605 ;
     RECT  99.54 57.569 99.897 57.605 ;
     RECT  100.944 57.595 102.114 57.605 ;
     RECT  83.415 56.285 83.697 57.685 ;
     RECT  98.244 57.541 98.262 57.685 ;
     RECT  102.096 57.605 102.114 57.713 ;
     RECT  83.124 57.685 83.697 57.721 ;
     RECT  95.76 57.541 95.778 57.721 ;
     RECT  3.96 57.299 4.554 57.749 ;
     RECT  76.032 57.569 76.086 57.749 ;
     RECT  76.932 57.721 76.95 57.811 ;
     RECT  97.128 57.547 97.506 57.839 ;
     RECT  78.015 57.541 78.786 57.875 ;
     RECT  81.288 57.569 81.558 57.875 ;
     RECT  82.98 57.721 83.697 57.875 ;
     RECT  95.544 57.721 95.778 57.875 ;
     RECT  98.244 57.685 98.55 57.875 ;
     RECT  94.215 57.065 94.497 57.955 ;
     RECT  122.904 57.787 122.922 57.965 ;
     RECT  76.932 57.811 76.986 57.991 ;
     RECT  88.38 57.181 89.37 57.991 ;
     RECT  94.212 57.955 94.497 57.991 ;
     RECT  95.4 57.955 95.418 57.991 ;
     RECT  83.415 57.875 83.697 58.075 ;
     RECT  79.776 57.541 79.794 58.081 ;
     RECT  76.932 57.991 77.094 58.109 ;
     RECT  94.212 57.991 95.418 58.109 ;
     RECT  103.068 57.991 103.086 58.109 ;
     RECT  123.048 57.991 123.066 58.109 ;
     RECT  125.568 57.569 126.897 58.109 ;
     RECT  88.092 57.991 89.478 58.123 ;
     RECT  90.252 57.991 90.27 58.123 ;
     RECT  91.872 57.991 91.998 58.123 ;
     RECT  88.092 58.123 90.27 58.145 ;
     RECT  94.212 58.109 95.166 58.145 ;
     RECT  100.944 57.605 100.962 58.145 ;
     RECT  113.112 57.811 113.13 58.145 ;
     RECT  123.84 57.991 123.858 58.145 ;
     RECT  125.856 58.109 126.897 58.145 ;
     RECT  76.932 58.109 76.986 58.157 ;
     RECT  82.476 58.117 82.494 58.157 ;
     RECT  102.204 58.117 102.222 58.225 ;
     RECT  83.415 58.075 84.294 58.261 ;
     RECT  79.776 58.081 80.406 58.379 ;
     RECT  81.54 57.875 81.558 58.379 ;
     RECT  83.415 58.261 84.438 58.379 ;
     RECT  100.872 58.261 100.89 58.379 ;
     RECT  102.204 58.225 102.402 58.379 ;
     RECT  80.064 58.379 80.406 58.415 ;
     RECT  83.415 58.379 84.294 58.415 ;
     RECT  97.488 57.839 97.506 58.415 ;
     RECT  102.204 58.379 102.222 58.415 ;
     RECT  0.108 58.315 0.126 58.493 ;
     RECT  2.304 57.335 2.697 58.531 ;
     RECT  72.615 56.641 73.926 58.531 ;
     RECT  74.988 57.005 75.006 58.531 ;
     RECT  99.615 57.605 99.897 58.531 ;
     RECT  6.372 55.949 6.39 58.559 ;
     RECT  78.015 57.875 78.297 58.621 ;
     RECT  91.872 58.123 92.61 58.621 ;
     RECT  94.212 58.145 94.986 58.621 ;
     RECT  72.615 58.531 75.006 58.649 ;
     RECT  83.415 58.415 83.934 58.649 ;
     RECT  96.372 58.531 96.462 58.649 ;
     RECT  98.136 58.531 98.154 58.649 ;
     RECT  87.696 58.621 87.786 58.685 ;
     RECT  91.224 58.621 92.61 58.685 ;
     RECT  96.444 58.649 96.462 58.685 ;
     RECT  98.928 58.531 99.897 58.685 ;
     RECT  87.768 58.685 87.786 58.919 ;
     RECT  88.704 58.145 90.27 58.919 ;
     RECT  91.224 58.685 92.43 58.919 ;
     RECT  88.704 58.919 89.622 58.955 ;
     RECT  91.224 58.919 92.214 58.955 ;
     RECT  94.068 58.621 94.986 58.955 ;
     RECT  98.964 58.685 99.897 58.955 ;
     RECT  2.304 58.531 2.826 59.071 ;
     RECT  125.856 58.145 125.874 59.071 ;
     RECT  80.064 58.415 80.082 59.161 ;
     RECT  99.072 58.955 99.897 59.161 ;
     RECT  79.92 59.161 80.082 59.189 ;
     RECT  85.608 59.071 85.626 59.189 ;
     RECT  125.64 59.071 125.874 59.189 ;
     RECT  122.832 59.071 122.85 59.197 ;
     RECT  79.92 59.189 79.938 59.213 ;
     RECT  122.652 59.197 122.85 59.261 ;
     RECT  81.036 59.197 81.054 59.341 ;
     RECT  82.08 59.161 82.098 59.341 ;
     RECT  85.068 59.305 85.086 59.341 ;
     RECT  99.072 59.161 100.998 59.341 ;
     RECT  83.415 58.649 83.79 59.459 ;
     RECT  84.852 59.341 85.086 59.459 ;
     RECT  99.072 59.341 101.07 59.459 ;
     RECT  103.716 59.233 103.878 59.459 ;
     RECT  113.508 59.071 113.526 59.459 ;
     RECT  125.1 59.341 125.118 59.459 ;
     RECT  81.036 59.341 82.098 59.495 ;
     RECT  99.072 59.459 100.854 59.495 ;
     RECT  102.024 59.197 102.042 59.495 ;
     RECT  103.86 59.459 103.878 59.495 ;
     RECT  123.696 59.197 123.714 59.495 ;
     RECT  3.96 57.749 3.978 59.531 ;
     RECT  94.14 58.955 94.986 59.611 ;
     RECT  125.856 59.189 125.874 59.701 ;
     RECT  126.615 58.145 126.897 59.701 ;
     RECT  97.164 59.611 97.29 59.729 ;
     RECT  99.072 59.495 100.278 59.729 ;
     RECT  128.808 57.019 128.826 59.729 ;
     RECT  2.304 59.071 2.898 59.737 ;
     RECT  81.18 59.495 81.594 59.765 ;
     RECT  97.272 59.729 97.29 59.765 ;
     RECT  99.072 59.729 100.026 59.765 ;
     RECT  120.348 59.737 120.366 59.789 ;
     RECT  125.856 59.701 126.897 59.801 ;
     RECT  88.812 58.955 89.097 59.803 ;
     RECT  105.015 41.099 105.297 59.809 ;
     RECT  118.584 59.701 118.602 59.837 ;
     RECT  88.524 59.803 89.097 59.843 ;
     RECT  91.368 58.955 91.638 59.845 ;
     RECT  77.796 58.621 78.297 59.851 ;
     RECT  84.852 59.459 84.942 59.851 ;
     RECT  88.815 59.843 89.097 59.881 ;
     RECT  91.368 59.845 92.142 59.881 ;
     RECT  84.6 59.851 84.942 59.999 ;
     RECT  88.815 59.881 92.142 59.999 ;
     RECT  112.608 59.701 112.626 59.999 ;
     RECT  124.236 59.809 124.254 59.999 ;
     RECT  2.304 59.737 3.006 60.035 ;
     RECT  91.656 59.999 92.142 60.035 ;
     RECT  104.184 59.809 105.297 60.035 ;
     RECT  122.976 59.701 122.994 60.035 ;
     RECT  77.796 59.851 78.57 60.241 ;
     RECT  94.14 59.611 95.13 60.241 ;
     RECT  99.072 59.765 99.897 60.241 ;
     RECT  3.996 59.611 4.014 60.269 ;
     RECT  87.768 59.701 87.786 60.269 ;
     RECT  104.184 60.035 104.202 60.269 ;
     RECT  88.815 59.999 90.666 60.305 ;
     RECT  91.656 60.035 91.854 60.305 ;
     RECT  102.852 59.755 102.87 60.305 ;
     RECT  83.415 59.459 83.697 60.379 ;
     RECT  76.968 58.157 76.986 60.385 ;
     RECT  77.796 60.241 78.75 60.385 ;
     RECT  81.468 59.765 81.594 60.385 ;
     RECT  92.916 60.313 92.934 60.385 ;
     RECT  94.14 60.241 95.202 60.385 ;
     RECT  76.968 60.385 78.75 60.413 ;
     RECT  83.412 60.379 83.697 60.419 ;
     RECT  81.468 60.385 82.098 60.421 ;
     RECT  84.6 59.999 84.87 60.421 ;
     RECT  92.916 60.385 95.202 60.421 ;
     RECT  98.64 60.241 99.897 60.421 ;
     RECT  101.484 60.385 101.502 60.421 ;
     RECT  126.615 59.801 126.897 60.421 ;
     RECT  125.1 60.421 125.118 60.427 ;
     RECT  2.34 60.035 3.006 60.539 ;
     RECT  81.468 60.421 82.674 60.539 ;
     RECT  97.452 60.241 97.47 60.539 ;
     RECT  98.604 60.421 99.897 60.539 ;
     RECT  102.564 60.385 102.582 60.539 ;
     RECT  124.92 60.427 125.118 60.539 ;
     RECT  128.808 60.475 128.826 60.539 ;
     RECT  79.812 60.241 79.83 60.575 ;
     RECT  81.576 60.539 82.674 60.575 ;
     RECT  92.7 60.421 95.202 60.575 ;
     RECT  98.604 60.539 98.658 60.575 ;
     RECT  101.484 60.421 101.574 60.575 ;
     RECT  126.615 60.421 127.134 60.575 ;
     RECT  124.92 60.539 124.938 60.611 ;
     RECT  90.108 60.305 90.666 60.647 ;
     RECT  98.604 60.575 98.622 60.647 ;
     RECT  101.556 60.575 101.574 60.647 ;
     RECT  99.615 60.539 99.897 60.655 ;
     RECT  125.856 59.801 125.874 60.655 ;
     RECT  125.784 60.655 125.874 60.691 ;
     RECT  126.615 60.575 126.897 60.691 ;
     RECT  91.836 60.305 91.854 60.809 ;
     RECT  92.808 60.575 92.934 60.809 ;
     RECT  99.615 60.655 99.99 60.809 ;
     RECT  125.784 60.691 126.897 60.809 ;
     RECT  84.492 60.421 84.87 60.845 ;
     RECT  92.808 60.809 92.826 60.845 ;
     RECT  126.216 60.809 126.897 60.845 ;
     RECT  2.34 60.539 2.862 60.907 ;
     RECT  88.815 60.305 89.097 60.961 ;
     RECT  2.304 60.907 2.862 61.079 ;
     RECT  88.776 60.961 89.097 61.079 ;
     RECT  81.576 60.575 81.594 61.115 ;
     RECT  90.108 60.647 90.414 61.115 ;
     RECT  84.816 60.845 84.87 61.133 ;
     RECT  82.512 60.575 82.674 61.231 ;
     RECT  83.415 60.419 83.697 61.231 ;
     RECT  84.96 61.231 84.978 61.349 ;
     RECT  90.216 61.115 90.414 61.349 ;
     RECT  82.512 61.231 83.898 61.385 ;
     RECT  85.752 61.231 86.274 61.385 ;
     RECT  90.216 61.349 90.234 61.385 ;
     RECT  82.656 61.385 83.697 61.619 ;
     RECT  86.076 61.385 86.274 61.619 ;
     RECT  82.656 61.619 82.674 61.655 ;
     RECT  86.076 61.619 86.094 61.655 ;
     RECT  0.108 61.465 0.126 61.805 ;
     RECT  2.34 61.079 2.862 62.303 ;
     RECT  2.34 62.303 2.826 62.581 ;
     RECT  0.108 62.815 0.126 63.533 ;
     RECT  2.304 62.581 2.826 63.779 ;
     RECT  2.304 63.779 2.697 64.397 ;
     RECT  2.34 64.397 2.697 65.261 ;
     RECT  59.688 41.099 59.706 81.869 ;
     RECT  70.164 52.169 70.182 81.869 ;
     RECT  52.884 36.959 53.334 81.985 ;
     RECT  55.368 38.939 55.386 81.985 ;
     RECT  56.232 40.019 57.258 81.985 ;
     RECT  52.74 81.985 53.334 82.021 ;
     RECT  60.624 42.449 60.642 82.021 ;
     RECT  66.672 48.929 68.094 82.021 ;
     RECT  71.028 52.745 71.694 82.021 ;
     RECT  72.615 58.649 73.926 82.021 ;
     RECT  59.544 81.985 59.562 82.061 ;
     RECT  70.02 81.985 70.038 82.061 ;
     RECT  54.612 38.939 54.63 82.075 ;
     RECT  55.368 81.985 57.258 82.075 ;
     RECT  63.252 44.447 63.27 82.139 ;
     RECT  69.192 51.089 69.21 82.139 ;
     RECT  54.612 82.075 57.258 82.147 ;
     RECT  54.468 82.147 57.258 82.175 ;
     RECT  55.368 82.175 57.258 82.205 ;
     RECT  64.872 45.599 64.89 82.255 ;
     RECT  65.736 45.455 65.754 82.255 ;
     RECT  72.615 82.021 74.25 82.255 ;
     RECT  50.76 35.573 51.822 82.291 ;
     RECT  52.74 82.021 53.622 82.291 ;
     RECT  56.124 82.205 57.258 82.291 ;
     RECT  58.032 40.289 58.05 82.291 ;
     RECT  58.788 40.493 58.806 82.291 ;
     RECT  61.524 43.835 62.154 82.291 ;
     RECT  63.108 82.255 63.126 82.291 ;
     RECT  64.008 45.599 64.026 82.291 ;
     RECT  64.872 82.255 65.754 82.291 ;
     RECT  66.528 82.021 68.094 82.291 ;
     RECT  69.048 82.255 69.066 82.301 ;
     RECT  54.468 82.175 54.63 82.409 ;
     RECT  64.872 82.291 68.094 82.409 ;
     RECT  76.968 60.413 78.354 82.525 ;
     RECT  50.76 82.291 53.622 82.561 ;
     RECT  61.38 82.291 62.154 82.561 ;
     RECT  62.892 82.291 63.126 82.561 ;
     RECT  72.612 82.255 74.25 82.561 ;
     RECT  64.008 82.291 64.062 82.603 ;
     RECT  64.872 82.409 67.878 82.603 ;
     RECT  70.956 82.021 71.694 82.603 ;
     RECT  54.468 82.409 54.486 82.637 ;
     RECT  64.008 82.603 67.878 82.637 ;
     RECT  64.008 82.637 64.89 82.651 ;
     RECT  72.432 82.561 74.25 82.651 ;
     RECT  74.988 58.649 75.006 82.651 ;
     RECT  76.068 57.749 76.086 82.651 ;
     RECT  61.38 82.561 63.126 82.685 ;
     RECT  75.924 82.651 76.086 82.688 ;
     RECT  63.864 82.651 64.89 82.715 ;
     RECT  50.76 82.561 53.73 82.795 ;
     RECT  76.932 82.525 78.354 82.795 ;
     RECT  50.652 82.795 53.73 82.831 ;
     RECT  60.444 82.021 60.642 82.831 ;
     RECT  61.38 82.685 62.982 82.831 ;
     RECT  70.884 82.603 71.694 82.831 ;
     RECT  72.432 82.651 75.006 82.831 ;
     RECT  76.932 82.795 79.11 82.831 ;
     RECT  56.124 82.291 59.49 82.949 ;
     RECT  57.96 82.949 59.49 82.985 ;
     RECT  56.124 82.949 57.15 83.057 ;
     RECT  76.86 82.831 79.218 83.065 ;
     RECT  55.368 82.205 55.386 83.101 ;
     RECT  60.444 82.831 62.982 83.101 ;
     RECT  69.84 82.291 69.858 83.101 ;
     RECT  70.776 82.831 71.694 83.101 ;
     RECT  72.432 82.831 75.69 83.101 ;
     RECT  76.608 83.065 79.218 83.219 ;
     RECT  55.332 83.101 55.386 83.371 ;
     RECT  56.124 83.057 57.078 83.371 ;
     RECT  59.364 82.985 59.49 83.371 ;
     RECT  65.628 82.637 67.878 83.371 ;
     RECT  69.696 83.101 69.858 83.371 ;
     RECT  50.652 82.831 54.27 83.461 ;
     RECT  63.972 82.715 64.89 83.461 ;
     RECT  65.628 83.371 67.914 83.461 ;
     RECT  68.724 82.561 68.778 83.605 ;
     RECT  50.436 83.461 54.27 83.641 ;
     RECT  55.332 83.371 57.078 83.641 ;
     RECT  59.364 83.371 59.562 83.641 ;
     RECT  60.336 83.101 62.982 83.641 ;
     RECT  63.72 83.461 67.914 83.641 ;
     RECT  68.652 83.605 68.778 83.641 ;
     RECT  69.588 83.371 69.858 83.641 ;
     RECT  70.776 83.101 75.69 83.641 ;
     RECT  76.608 83.219 76.734 83.641 ;
     RECT  59.364 83.641 67.914 83.731 ;
     RECT  68.652 83.641 68.85 83.731 ;
     RECT  69.588 83.641 75.762 83.731 ;
     RECT  76.5 83.641 76.734 83.731 ;
     RECT  59.364 83.731 68.85 83.759 ;
     RECT  69.588 83.731 76.734 83.759 ;
     RECT  50.292 83.641 57.078 83.795 ;
     RECT  50.688 83.795 57.078 83.837 ;
     RECT  77.472 83.219 79.218 83.839 ;
     RECT  51.015 83.837 57.078 83.875 ;
     RECT  57.96 82.985 58.59 83.875 ;
     RECT  67.104 83.759 68.85 83.875 ;
     RECT  69.588 83.759 69.714 83.875 ;
     RECT  51.015 83.875 58.59 83.911 ;
     RECT  59.364 83.759 62.802 83.911 ;
     RECT  2.415 65.261 2.697 83.987 ;
     RECT  7.815 56.489 8.097 83.987 ;
     RECT  13.215 37.328 13.497 83.987 ;
     RECT  18.615 21.389 18.897 83.987 ;
     RECT  24.015 37.328 24.297 83.987 ;
     RECT  29.415 44.339 29.697 83.987 ;
     RECT  34.815 37.325 35.097 83.987 ;
     RECT  40.215 24.359 40.497 83.987 ;
     RECT  45.615 21.197 45.897 83.987 ;
     RECT  51.015 83.911 62.802 83.987 ;
     RECT  83.415 61.619 83.697 83.987 ;
     RECT  88.815 61.079 89.097 83.987 ;
     RECT  94.215 60.575 94.497 83.987 ;
     RECT  99.615 60.809 99.897 83.987 ;
     RECT  105.015 60.035 105.297 83.987 ;
     RECT  110.415 53.015 110.697 83.987 ;
     RECT  115.815 25.133 116.097 83.987 ;
     RECT  121.215 52.979 121.497 83.987 ;
     RECT  126.615 60.845 126.897 83.987 ;
     RECT  51.015 83.987 61.905 84.029 ;
     RECT  63.648 83.759 64.458 84.029 ;
     RECT  67.104 83.875 69.714 84.029 ;
     RECT  70.56 83.759 76.734 84.029 ;
     RECT  77.472 83.839 79.362 84.029 ;
     RECT  51.015 84.029 54.054 84.065 ;
     RECT  56.052 84.029 58.626 84.065 ;
     RECT  67.104 84.029 67.878 84.065 ;
     RECT  68.832 84.029 69.714 84.065 ;
     RECT  74.88 84.029 75.762 84.065 ;
     RECT  77.472 84.029 79.218 84.065 ;
     RECT  57.6 84.065 58.626 84.101 ;
     RECT  59.616 84.029 61.905 84.101 ;
     RECT  65.448 83.759 66.258 84.137 ;
     RECT  57.6 84.101 58.482 84.173 ;
     RECT  70.56 84.029 74.142 84.173 ;
     RECT  53.1 84.065 54.054 84.209 ;
     RECT  71.424 84.173 73.17 84.209 ;
     RECT  74.016 84.173 74.142 84.209 ;
     RECT  2.415 83.987 2.505 84.257 ;
     RECT  7.815 83.987 7.905 84.257 ;
     RECT  13.215 83.987 13.305 84.257 ;
     RECT  18.615 83.987 18.705 84.257 ;
     RECT  24.015 83.987 24.105 84.257 ;
     RECT  29.415 83.987 29.505 84.257 ;
     RECT  34.815 83.987 34.905 84.257 ;
     RECT  40.215 83.987 40.305 84.257 ;
     RECT  45.615 83.987 45.705 84.257 ;
     RECT  51.015 84.065 52.254 84.257 ;
     RECT  61.128 84.101 61.905 84.257 ;
     RECT  72.18 84.209 73.17 84.257 ;
     RECT  83.415 83.987 83.505 84.257 ;
     RECT  88.815 83.987 88.905 84.257 ;
     RECT  94.215 83.987 94.305 84.257 ;
     RECT  99.615 83.987 99.705 84.257 ;
     RECT  105.015 83.987 105.105 84.257 ;
     RECT  110.415 83.987 110.505 84.257 ;
     RECT  115.815 83.987 115.905 84.257 ;
     RECT  121.215 83.987 121.305 84.257 ;
     RECT  126.615 83.987 126.705 84.257 ;
     RECT  54.036 84.209 54.054 84.365 ;
     RECT  51.552 84.257 52.254 84.941 ;
     RECT  54.864 84.029 54.882 84.941 ;
     RECT  56.052 84.065 56.754 84.941 ;
     RECT  58.464 84.173 58.482 84.941 ;
     RECT  59.616 84.101 60.21 84.941 ;
     RECT  61.128 84.257 61.794 84.941 ;
     RECT  63.648 84.029 63.666 84.941 ;
     RECT  65.448 84.137 65.466 84.941 ;
     RECT  68.832 84.065 69.57 84.941 ;
     RECT  70.56 84.173 70.578 84.941 ;
     RECT  71.424 84.209 71.442 84.941 ;
     RECT  72.18 84.257 72.198 84.941 ;
     RECT  73.152 84.257 73.17 84.941 ;
     RECT  74.88 84.065 74.898 84.941 ;
     RECT  75.744 84.065 75.762 84.941 ;
     RECT  77.472 84.065 78.174 84.941 ;
     RECT  67.104 84.065 67.842 85.517 ;
     RECT  64.44 84.029 64.458 86.045 ;
     RECT  53.1 84.209 53.118 86.285 ;
     RECT  56.052 84.941 56.07 86.285 ;
     RECT  57.6 84.173 57.618 86.285 ;
     RECT  59.616 84.941 59.634 86.285 ;
     RECT  61.128 84.941 61.146 86.285 ;
     RECT  62.784 83.987 62.802 86.285 ;
     RECT  66.24 84.137 66.258 86.285 ;
     RECT  67.104 85.517 67.122 86.285 ;
     RECT  69.552 84.941 69.57 86.285 ;
     RECT  74.016 84.209 74.034 86.285 ;
     RECT  76.716 84.029 76.734 86.285 ;
     RECT  79.2 84.065 79.218 86.285 ;
    LAYER M4 ;
     RECT  0.06 21.168 0.137 65.256 ;
     RECT  0.137 21.168 2.408 22.056 ;
     RECT  0.137 23.76 2.408 47.112 ;
     RECT  0.137 48.816 2.408 57.48 ;
     RECT  0.137 58.464 2.408 60.936 ;
     RECT  0.137 62.64 2.408 62.664 ;
     RECT  0.137 64.368 2.408 65.256 ;
     RECT  2.408 2.148 2.512 84.252 ;
     RECT  2.512 2.418 2.704 83.982 ;
     RECT  2.704 34.992 2.765 35.016 ;
     RECT  2.704 38.448 2.765 39.336 ;
     RECT  2.704 46.176 2.765 47.112 ;
     RECT  2.704 51.408 2.837 51.432 ;
     RECT  2.765 39.312 2.981 39.336 ;
     RECT  2.704 42.768 3.341 43.32 ;
     RECT  2.704 54.624 3.683 54.744 ;
     RECT  2.704 57.024 3.683 57.048 ;
     RECT  2.704 50.112 4.021 50.136 ;
     RECT  4.021 50.112 4.061 50.616 ;
     RECT  4.316 39.888 4.357 39.912 ;
     RECT  3.341 43.296 4.357 43.32 ;
     RECT  4.357 39.888 4.403 41.64 ;
     RECT  4.403 40.704 4.493 41.64 ;
     RECT  4.357 42.768 4.493 43.32 ;
     RECT  2.704 22.752 4.501 22.776 ;
     RECT  4.345 25.44 4.501 25.464 ;
     RECT  4.501 22.752 4.547 23.784 ;
     RECT  4.501 25.44 4.547 26.28 ;
     RECT  4.547 23.28 4.588 23.784 ;
     RECT  4.345 53.568 4.595 53.592 ;
     RECT  4.604 32.448 4.645 32.472 ;
     RECT  4.597 33.6 4.645 33.624 ;
     RECT  4.604 35.664 4.645 35.688 ;
     RECT  4.645 31.776 4.691 32.472 ;
     RECT  4.645 33.6 4.691 34.152 ;
     RECT  4.645 35.28 4.691 35.688 ;
     RECT  4.645 36.768 4.777 36.792 ;
     RECT  4.777 36.768 4.817 37.032 ;
     RECT  4.061 50.592 4.913 50.616 ;
     RECT  4.913 50.592 4.979 51.336 ;
     RECT  4.979 51.312 4.997 51.336 ;
     RECT  4.549 52.416 5.057 52.44 ;
     RECT  4.817 37.008 5.077 37.032 ;
     RECT  4.357 38.208 5.077 38.232 ;
     RECT  5.057 51.888 5.141 52.44 ;
     RECT  4.633 29.184 5.171 29.208 ;
     RECT  5.125 27.312 5.249 27.336 ;
     RECT  3.683 54.72 5.353 54.744 ;
     RECT  5.353 54.72 5.393 55.272 ;
     RECT  4.588 23.28 5.573 23.304 ;
     RECT  5.077 37.008 5.609 38.232 ;
     RECT  4.493 43.296 5.641 43.32 ;
     RECT  5.612 44.352 5.641 44.376 ;
     RECT  2.765 46.176 5.653 46.2 ;
     RECT  5.641 43.296 5.699 44.376 ;
     RECT  5.653 45.84 5.699 46.2 ;
     RECT  5.605 47.28 5.747 47.304 ;
     RECT  4.691 31.776 5.789 31.8 ;
     RECT  4.691 34.128 5.933 34.152 ;
     RECT  5.701 48.432 5.941 48.456 ;
     RECT  4.933 49.584 5.941 49.608 ;
     RECT  5.941 48.432 5.987 49.608 ;
     RECT  5.987 48.432 6.028 48.84 ;
     RECT  5.609 37.584 6.329 38.232 ;
     RECT  5.699 45.84 6.437 45.864 ;
     RECT  4.493 41.616 6.581 41.64 ;
     RECT  6.028 48.432 6.617 48.456 ;
     RECT  4.691 35.28 6.653 35.304 ;
     RECT  5.141 52.416 6.653 52.44 ;
     RECT  4.547 26.256 6.901 26.28 ;
     RECT  6.901 24.48 7.808 26.28 ;
     RECT  6.893 27.36 7.808 27.384 ;
     RECT  6.329 37.584 7.808 37.608 ;
     RECT  5.699 43.296 7.808 44.136 ;
     RECT  5.393 55.248 7.808 55.272 ;
     RECT  7.808 2.148 7.912 84.252 ;
     RECT  7.912 2.418 8.104 83.982 ;
     RECT  8.104 37.584 9.109 37.608 ;
     RECT  9.109 37.296 9.155 37.608 ;
     RECT  8.104 25.296 9.421 25.32 ;
     RECT  9.421 25.056 9.461 25.32 ;
     RECT  9.461 25.056 9.505 25.08 ;
     RECT  9.637 24.912 13.208 24.936 ;
     RECT  9.155 37.296 13.208 37.32 ;
     RECT  8.104 43.296 13.208 44.136 ;
     RECT  13.208 2.148 13.312 84.252 ;
     RECT  13.312 2.418 13.504 83.982 ;
     RECT  13.504 24.912 18.608 24.936 ;
     RECT  13.504 37.296 18.608 37.32 ;
     RECT  13.504 43.296 18.608 44.136 ;
     RECT  18.608 2.148 18.712 84.252 ;
     RECT  18.712 2.418 18.904 83.982 ;
     RECT  18.904 24.912 24.008 24.936 ;
     RECT  18.904 37.296 24.008 37.32 ;
     RECT  18.904 43.296 24.008 44.136 ;
     RECT  24.008 2.148 24.112 84.252 ;
     RECT  24.112 2.418 24.304 83.982 ;
     RECT  24.304 24.912 29.408 24.936 ;
     RECT  24.304 37.296 29.408 37.32 ;
     RECT  24.304 43.296 29.408 44.136 ;
     RECT  29.408 2.148 29.512 84.252 ;
     RECT  29.512 2.418 29.704 83.982 ;
     RECT  29.704 43.296 29.873 44.136 ;
     RECT  32.732 16.128 32.819 16.152 ;
     RECT  29.704 24.912 32.819 24.936 ;
     RECT  32.773 15.072 33.329 15.096 ;
     RECT  29.704 37.296 34.808 37.32 ;
     RECT  29.873 43.296 34.808 44.088 ;
     RECT  34.808 2.148 34.912 84.252 ;
     RECT  34.912 2.418 35.104 83.982 ;
     RECT  35.104 25.632 36.179 26.28 ;
     RECT  36.179 25.632 36.461 25.656 ;
     RECT  38.545 23.952 38.677 24.072 ;
     RECT  38.677 22.992 38.723 24.072 ;
     RECT  38.221 11.376 38.761 11.4 ;
     RECT  35.104 37.296 38.761 37.32 ;
     RECT  38.329 21.648 38.771 21.672 ;
     RECT  38.723 24.048 38.771 24.072 ;
     RECT  38.761 11.232 38.801 11.4 ;
     RECT  38.761 37.152 38.801 37.32 ;
     RECT  38.723 22.992 39.517 23.016 ;
     RECT  38.149 3.408 40.208 3.432 ;
     RECT  38.801 11.232 40.208 11.256 ;
     RECT  39.517 22.8 40.208 23.016 ;
     RECT  36.133 35.424 40.208 35.448 ;
     RECT  38.801 37.152 40.208 37.176 ;
     RECT  35.104 43.296 40.208 44.088 ;
     RECT  40.208 2.148 40.312 84.252 ;
     RECT  40.312 2.418 40.504 83.982 ;
     RECT  40.504 37.152 40.739 37.176 ;
     RECT  40.504 6.24 40.825 6.504 ;
     RECT  40.504 30.816 40.883 30.936 ;
     RECT  40.504 22.8 41.557 22.824 ;
     RECT  41.557 22.8 41.603 23.4 ;
     RECT  41.605 20.16 41.699 20.184 ;
     RECT  40.504 11.232 41.747 11.256 ;
     RECT  41.701 8.448 41.843 8.472 ;
     RECT  41.557 21.264 41.861 21.672 ;
     RECT  41.603 23.376 41.861 23.4 ;
     RECT  40.504 3.408 41.929 3.432 ;
     RECT  40.825 6.48 42.14 6.504 ;
     RECT  41.929 3.408 42.181 3.72 ;
     RECT  42.181 3.408 42.227 3.864 ;
     RECT  42.14 6.24 42.227 6.504 ;
     RECT  37.105 0.096 42.373 0.12 ;
     RECT  40.883 30.816 42.757 30.84 ;
     RECT  42.757 30.816 42.797 30.984 ;
     RECT  42.227 3.552 43.196 3.864 ;
     RECT  43.196 3.552 43.237 4.104 ;
     RECT  43.237 3.408 43.283 4.104 ;
     RECT  43.189 1.728 43.337 1.752 ;
     RECT  41.861 21.648 43.765 21.672 ;
     RECT  43.765 21.12 43.877 21.672 ;
     RECT  44.017 0.096 44.101 0.12 ;
     RECT  42.797 30.96 44.521 30.984 ;
     RECT  44.909 1.728 44.993 1.752 ;
     RECT  43.283 3.408 45.608 3.432 ;
     RECT  44.953 18.768 45.608 18.792 ;
     RECT  43.877 21.12 45.608 21.192 ;
     RECT  44.521 30.864 45.608 30.984 ;
     RECT  40.504 35.424 45.608 35.448 ;
     RECT  40.504 43.296 45.608 44.088 ;
     RECT  45.608 2.148 45.712 84.252 ;
     RECT  45.712 2.418 45.904 83.982 ;
     RECT  45.904 30.72 46.019 30.984 ;
     RECT  45.904 3.264 46.217 4.296 ;
     RECT  46.217 3.408 48.485 4.296 ;
     RECT  48.485 3.984 48.521 4.296 ;
     RECT  48.521 4.176 49.525 4.296 ;
     RECT  49.525 3.936 49.709 4.296 ;
     RECT  45.904 21.12 49.813 21.192 ;
     RECT  46.019 30.864 49.916 30.888 ;
     RECT  49.813 21.12 50.003 21.768 ;
     RECT  49.916 30.528 50.003 30.888 ;
     RECT  50.003 30.864 50.137 30.888 ;
     RECT  49.709 3.936 50.677 4.2 ;
     RECT  49.813 18.72 50.869 18.744 ;
     RECT  50.677 3.408 51.008 4.2 ;
     RECT  50.869 15.84 51.008 15.864 ;
     RECT  50.869 18.528 51.008 18.744 ;
     RECT  50.003 21.744 51.008 21.768 ;
     RECT  50.137 30.864 51.008 30.984 ;
     RECT  45.904 35.136 51.008 35.448 ;
     RECT  45.904 43.296 51.008 44.088 ;
     RECT  50.641 82.8 51.008 82.824 ;
     RECT  50.533 83.808 51.008 83.832 ;
     RECT  45.745 0.096 51.013 0.12 ;
     RECT  51.008 2.148 51.304 84.252 ;
     RECT  51.304 82.656 51.509 82.824 ;
     RECT  51.304 2.832 51.964 4.728 ;
     RECT  51.397 84.912 52.309 84.936 ;
     RECT  51.304 15.84 52.373 15.864 ;
     RECT  51.964 3.408 52.409 4.728 ;
     RECT  51.509 82.656 52.729 82.68 ;
     RECT  51.304 35.424 52.748 35.448 ;
     RECT  52.748 35.328 52.789 35.448 ;
     RECT  52.729 82.032 52.813 82.68 ;
     RECT  52.409 3.408 52.841 4.68 ;
     RECT  51.793 1.728 52.985 1.752 ;
     RECT  52.813 82.608 53.162 82.68 ;
     RECT  53.089 86.256 53.173 86.28 ;
     RECT  52.789 35.328 53.309 36.264 ;
     RECT  52.841 3.552 53.741 4.68 ;
     RECT  53.741 3.936 53.747 4.68 ;
     RECT  53.701 7.344 53.989 7.368 ;
     RECT  53.747 4.128 53.993 4.68 ;
     RECT  53.989 7.344 54.035 8.232 ;
     RECT  53.981 84.336 54.065 84.36 ;
     RECT  53.162 82.608 54.497 82.632 ;
     RECT  51.304 30.864 54.613 30.984 ;
     RECT  53.993 4.128 54.641 4.536 ;
     RECT  54.613 30.768 54.749 30.984 ;
     RECT  54.853 84.912 54.937 84.936 ;
     RECT  54.641 4.128 55.141 4.392 ;
     RECT  53.309 36.24 56.041 36.264 ;
     RECT  55.825 38.112 56.053 38.136 ;
     RECT  55.213 82.08 56.077 82.104 ;
     RECT  55.717 86.256 56.081 86.28 ;
     RECT  55.141 3.936 56.408 4.392 ;
     RECT  54.035 8.208 56.408 8.232 ;
     RECT  52.988 24.096 56.408 24.12 ;
     RECT  54.749 30.864 56.408 30.984 ;
     RECT  56.041 36.24 56.408 36.552 ;
     RECT  56.053 37.584 56.408 38.136 ;
     RECT  56.293 39.216 56.408 39.24 ;
     RECT  51.304 43.296 56.408 44.088 ;
     RECT  56.077 82.08 56.408 82.2 ;
     RECT  56.408 2.148 56.512 84.252 ;
     RECT  56.512 2.418 56.581 84.252 ;
     RECT  56.581 2.418 56.704 84.936 ;
     RECT  56.704 84.912 56.765 84.936 ;
     RECT  56.704 24.096 57.045 24.12 ;
     RECT  56.704 82.176 57.089 82.68 ;
     RECT  56.704 3.168 57.197 4.152 ;
     RECT  57.445 86.256 57.629 86.28 ;
     RECT  56.704 26.496 57.733 26.52 ;
     RECT  57.733 26.496 57.773 26.76 ;
     RECT  56.704 39.216 57.773 39.24 ;
     RECT  57.805 35.328 58.169 35.352 ;
     RECT  58.309 84.912 58.493 84.936 ;
     RECT  57.197 3.408 58.601 4.152 ;
     RECT  57.089 82.656 58.633 82.68 ;
     RECT  56.704 36.528 58.645 36.552 ;
     RECT  58.645 36.528 58.691 36.84 ;
     RECT  58.093 39.264 58.933 39.288 ;
     RECT  58.933 38.4 58.981 39.288 ;
     RECT  57.773 26.736 58.988 26.76 ;
     RECT  58.981 38.4 59.027 40.008 ;
     RECT  57.805 22.752 59.029 22.776 ;
     RECT  59.027 39.984 59.029 40.008 ;
     RECT  59.029 39.984 59.069 40.488 ;
     RECT  58.988 26.496 59.075 26.76 ;
     RECT  56.704 30.864 59.075 30.984 ;
     RECT  58.691 36.816 59.101 36.84 ;
     RECT  59.101 36.816 59.141 37.08 ;
     RECT  58.633 82.656 59.533 82.776 ;
     RECT  59.533 82.032 59.617 82.776 ;
     RECT  59.173 86.256 59.645 86.28 ;
     RECT  58.601 3.84 59.701 4.152 ;
     RECT  59.653 6.816 59.708 6.84 ;
     RECT  59.708 6.816 59.749 7.8 ;
     RECT  59.749 6.816 59.795 7.896 ;
     RECT  59.701 3.84 59.797 4.248 ;
     RECT  59.797 3.648 59.843 4.248 ;
     RECT  59.795 7.872 59.843 7.896 ;
     RECT  59.641 10.944 59.843 10.968 ;
     RECT  60.037 84.912 60.221 84.936 ;
     RECT  59.069 40.464 60.437 40.488 ;
     RECT  59.617 82.608 60.509 82.776 ;
     RECT  59.075 26.736 60.572 26.76 ;
     RECT  60.572 26.496 60.613 26.76 ;
     RECT  60.613 26.496 60.659 27.624 ;
     RECT  60.577 24.48 60.661 24.504 ;
     RECT  59.141 37.056 60.829 37.08 ;
     RECT  59.027 38.4 60.829 38.424 ;
     RECT  60.901 86.256 61.157 86.28 ;
     RECT  60.973 42.144 61.237 42.168 ;
     RECT  56.704 43.296 61.237 44.088 ;
     RECT  59.843 3.648 61.808 3.96 ;
     RECT  60.145 11.376 61.808 11.4 ;
     RECT  61.669 14.112 61.808 14.136 ;
     RECT  61.669 15.216 61.808 15.24 ;
     RECT  59.029 22.464 61.808 22.776 ;
     RECT  60.659 27.6 61.808 27.624 ;
     RECT  59.075 30.864 61.808 30.888 ;
     RECT  58.933 35.232 61.808 35.256 ;
     RECT  60.829 37.056 61.808 38.424 ;
     RECT  61.237 42.144 61.808 44.088 ;
     RECT  60.509 82.608 61.808 82.632 ;
     RECT  61.765 84.912 61.808 84.936 ;
     RECT  61.808 2.148 61.849 84.936 ;
     RECT  61.849 2.148 61.912 84.252 ;
     RECT  61.912 2.418 62.104 83.982 ;
     RECT  62.104 37.056 62.339 40.008 ;
     RECT  62.339 38.352 62.531 40.008 ;
     RECT  62.629 86.256 62.813 86.28 ;
     RECT  62.104 14.112 62.921 14.136 ;
     RECT  62.104 27.6 62.921 27.624 ;
     RECT  62.531 38.352 62.921 39.288 ;
     RECT  62.339 37.056 62.957 37.08 ;
     RECT  62.921 38.352 62.957 38.712 ;
     RECT  62.104 82.272 63.097 82.296 ;
     RECT  63.097 82.272 63.137 82.68 ;
     RECT  62.104 35.136 63.317 35.352 ;
     RECT  62.104 42.72 63.389 43.32 ;
     RECT  63.493 84.912 63.677 84.936 ;
     RECT  63.137 82.656 63.893 82.68 ;
     RECT  62.104 3.552 64.145 3.864 ;
     RECT  64.357 86.016 64.469 86.04 ;
     RECT  63.389 43.296 64.505 43.32 ;
     RECT  62.957 38.688 64.796 38.712 ;
     RECT  64.796 37.824 64.883 38.712 ;
     RECT  64.145 3.552 65.132 3.576 ;
     RECT  65.132 3.312 65.219 3.576 ;
     RECT  64.717 43.92 65.401 43.944 ;
     RECT  65.401 43.92 65.441 44.472 ;
     RECT  64.681 41.088 65.468 41.112 ;
     RECT  65.221 84.912 65.477 84.936 ;
     RECT  65.173 17.28 65.555 17.304 ;
     RECT  65.468 41.088 65.555 41.64 ;
     RECT  65.441 44.448 65.653 44.472 ;
     RECT  65.653 44.448 65.699 45.432 ;
     RECT  65.699 44.88 65.74 45.432 ;
     RECT  65.509 18.384 65.833 18.408 ;
     RECT  65.833 18.384 65.873 18.744 ;
     RECT  65.9 43.296 65.905 43.32 ;
     RECT  62.104 30.864 65.987 30.888 ;
     RECT  65.905 42.48 65.987 43.32 ;
     RECT  65.219 3.552 66.193 3.576 ;
     RECT  63.317 35.136 66.229 35.16 ;
     RECT  64.717 82.608 66.476 82.632 ;
     RECT  66.229 34.8 66.697 35.16 ;
     RECT  64.883 38.688 66.697 38.712 ;
     RECT  66.476 82.032 66.941 82.632 ;
     RECT  66.085 86.256 67.133 86.28 ;
     RECT  64.573 36.432 67.165 36.456 ;
     RECT  66.193 3.552 67.208 3.864 ;
     RECT  65.873 18.72 67.208 18.744 ;
     RECT  62.104 22.464 67.208 22.488 ;
     RECT  65.473 25.008 67.208 25.032 ;
     RECT  66.337 28.944 67.208 28.968 ;
     RECT  66.697 34.8 67.208 35.256 ;
     RECT  67.165 36.336 67.208 36.456 ;
     RECT  66.697 38.688 67.208 39.336 ;
     RECT  65.555 41.088 67.208 41.112 ;
     RECT  65.987 42.48 67.208 42.792 ;
     RECT  65.74 44.88 67.208 45 ;
     RECT  65.941 46.848 67.208 46.872 ;
     RECT  66.941 82.032 67.208 83.256 ;
     RECT  67.208 2.148 67.312 84.252 ;
     RECT  67.312 2.418 67.504 83.982 ;
     RECT  67.504 28.944 67.619 29.256 ;
     RECT  67.504 44.448 67.619 45 ;
     RECT  67.504 46.32 67.619 47.304 ;
     RECT  67.504 18.72 67.715 18.744 ;
     RECT  67.504 22.608 67.715 22.632 ;
     RECT  67.504 25.008 67.715 25.032 ;
     RECT  67.504 36.336 67.811 37.08 ;
     RECT  67.772 85.488 67.859 85.512 ;
     RECT  68.677 84.912 68.861 84.936 ;
     RECT  67.504 34.896 68.993 35.256 ;
     RECT  68.993 34.752 69.077 35.256 ;
     RECT  67.811 37.056 69.185 37.08 ;
     RECT  67.619 46.752 69.361 47.304 ;
     RECT  69.325 48.432 69.361 48.456 ;
     RECT  69.361 46.752 69.365 48.456 ;
     RECT  69.365 46.752 69.541 46.872 ;
     RECT  67.619 44.448 69.581 44.472 ;
     RECT  69.541 86.256 69.625 86.28 ;
     RECT  67.504 26.112 69.653 26.136 ;
     RECT  67.504 82.272 69.98 82.296 ;
     RECT  69.932 30.528 70.019 30.552 ;
     RECT  69.98 82.032 70.021 82.296 ;
     RECT  70.021 82.032 70.067 82.632 ;
     RECT  67.504 42.48 70.081 42.504 ;
     RECT  68.569 40.752 70.117 40.776 ;
     RECT  70.081 42.48 70.117 42.792 ;
     RECT  69.365 47.904 70.117 48.456 ;
     RECT  70.117 40.272 70.121 42.792 ;
     RECT  69.077 34.896 70.153 35.256 ;
     RECT  70.121 40.272 70.163 41.736 ;
     RECT  70.117 47.904 70.163 49.032 ;
     RECT  70.076 50.208 70.163 50.232 ;
     RECT  70.153 34.896 70.193 35.88 ;
     RECT  70.163 49.008 70.265 49.032 ;
     RECT  70.163 41.712 70.373 41.736 ;
     RECT  70.163 40.272 70.453 40.296 ;
     RECT  70.453 39.312 70.54 40.296 ;
     RECT  67.619 29.232 70.589 29.256 ;
     RECT  70.193 35.136 70.693 35.88 ;
     RECT  70.117 51.36 70.693 51.384 ;
     RECT  70.693 51.36 70.733 51.672 ;
     RECT  70.693 35.136 70.739 36.504 ;
     RECT  70.067 82.608 70.913 82.632 ;
     RECT  70.739 36.48 70.985 36.504 ;
     RECT  70.121 42.768 71.021 42.792 ;
     RECT  67.504 3.552 71.305 3.672 ;
     RECT  71.521 81.504 71.605 82.296 ;
     RECT  70.739 35.136 71.773 35.16 ;
     RECT  70.54 40.272 71.809 40.296 ;
     RECT  69.541 46.608 72.421 46.872 ;
     RECT  71.305 2.832 72.608 3.672 ;
     RECT  71.773 34.992 72.608 35.16 ;
     RECT  71.809 40.272 72.608 40.44 ;
     RECT  72.38 42.096 72.608 42.12 ;
     RECT  72.421 46.08 72.608 46.872 ;
     RECT  70.163 47.904 72.608 47.928 ;
     RECT  70.733 51.648 72.608 51.672 ;
     RECT  71.708 52.704 72.608 52.728 ;
     RECT  71.557 56.496 72.608 56.52 ;
     RECT  71.605 82.272 72.608 82.296 ;
     RECT  70.405 84.912 72.608 84.936 ;
     RECT  72.608 2.148 72.712 84.936 ;
     RECT  72.712 2.418 72.904 84.936 ;
     RECT  72.904 3.408 73.043 3.864 ;
     RECT  72.904 84.912 73.181 84.936 ;
     RECT  72.904 33.792 73.331 35.16 ;
     RECT  72.904 82.032 73.379 82.68 ;
     RECT  73.043 3.648 73.397 3.864 ;
     RECT  73.331 34.752 73.513 35.16 ;
     RECT  72.904 39.888 73.523 40.44 ;
     RECT  72.904 53.568 73.523 54.312 ;
     RECT  72.904 46.08 73.571 47.928 ;
     RECT  72.904 43.92 73.721 44.472 ;
     RECT  73.571 47.904 73.829 47.928 ;
     RECT  73.571 46.08 73.933 46.872 ;
     RECT  72.904 31.296 73.973 31.32 ;
     RECT  73.861 86.256 74.045 86.28 ;
     RECT  72.904 41.76 74.257 41.784 ;
     RECT  74.257 41.28 74.297 41.784 ;
     RECT  73.523 39.888 74.405 39.912 ;
     RECT  73.523 54.288 74.545 54.312 ;
     RECT  74.545 54.288 74.585 54.408 ;
     RECT  73.721 44.448 74.761 44.472 ;
     RECT  72.904 51.648 74.933 51.672 ;
     RECT  73.397 3.84 74.945 3.864 ;
     RECT  74.933 50.688 75.017 51.672 ;
     RECT  72.904 56.496 75.193 56.52 ;
     RECT  74.761 44.448 75.356 44.904 ;
     RECT  73.933 45.936 75.356 46.872 ;
     RECT  75.356 44.448 75.443 46.872 ;
     RECT  74.297 41.28 75.548 41.304 ;
     RECT  75.548 40.752 75.629 41.304 ;
     RECT  75.629 40.752 75.635 41.256 ;
     RECT  75.017 51.648 75.665 51.672 ;
     RECT  74.725 84.912 75.773 84.936 ;
     RECT  73.513 35.136 76.021 35.16 ;
     RECT  76.021 34.8 76.061 35.16 ;
     RECT  72.904 37.296 76.061 37.32 ;
     RECT  75.193 56.496 76.069 57 ;
     RECT  76.061 34.8 76.105 34.824 ;
     RECT  76.069 55.536 76.125 57 ;
     RECT  76.125 55.536 76.211 56.52 ;
     RECT  76.453 86.256 76.745 86.28 ;
     RECT  75.157 3.408 76.748 3.432 ;
     RECT  76.7 37.584 76.787 37.608 ;
     RECT  76.748 3.408 76.835 4.104 ;
     RECT  73.379 82.656 76.961 82.68 ;
     RECT  76.885 58.128 76.972 58.152 ;
     RECT  77.317 52.896 77.509 52.92 ;
     RECT  74.585 54.384 77.509 54.408 ;
     RECT  76.835 3.408 77.965 3.432 ;
     RECT  77.965 3.312 78.008 3.432 ;
     RECT  76.021 33.36 78.008 33.384 ;
     RECT  76.741 36.528 78.008 36.552 ;
     RECT  75.635 41.232 78.008 41.256 ;
     RECT  75.805 42.768 78.008 42.792 ;
     RECT  75.443 44.448 78.008 44.472 ;
     RECT  75.443 46.032 78.008 46.872 ;
     RECT  76.021 48.432 78.008 48.456 ;
     RECT  77.749 50.4 78.008 50.424 ;
     RECT  77.509 52.896 78.008 54.408 ;
     RECT  76.211 56.496 78.008 56.52 ;
     RECT  76.885 59.856 78.008 59.88 ;
     RECT  77.425 83.04 78.008 83.064 ;
     RECT  77.317 84.912 78.008 84.936 ;
     RECT  78.008 2.148 78.112 84.936 ;
     RECT  78.112 2.418 78.229 84.936 ;
     RECT  78.229 2.418 78.304 83.982 ;
     RECT  78.304 50.4 78.419 51.336 ;
     RECT  78.419 51.312 78.509 51.336 ;
     RECT  78.304 59.856 78.581 59.88 ;
     RECT  78.304 54.384 78.653 55.32 ;
     RECT  78.304 37.632 78.659 38.04 ;
     RECT  78.304 46.032 78.659 47.304 ;
     RECT  78.304 48.432 78.689 49.032 ;
     RECT  78.304 35.328 78.707 36.552 ;
     RECT  78.653 54.48 78.707 55.32 ;
     RECT  78.659 37.632 78.733 37.656 ;
     RECT  78.304 42.768 78.797 42.792 ;
     RECT  78.659 46.224 78.941 47.304 ;
     RECT  78.304 3.312 79.049 3.336 ;
     RECT  78.707 35.328 79.193 35.88 ;
     RECT  78.707 55.296 79.229 55.32 ;
     RECT  79.045 86.256 79.229 86.28 ;
     RECT  78.304 34.176 79.235 34.2 ;
     RECT  79.193 35.328 79.661 35.352 ;
     RECT  78.304 56.352 80.093 56.52 ;
     RECT  80.093 56.496 80.156 56.52 ;
     RECT  80.156 56.496 80.197 56.712 ;
     RECT  79.729 3.696 80.453 3.72 ;
     RECT  80.377 44.448 80.557 44.472 ;
     RECT  80.125 40.464 80.849 40.488 ;
     RECT  80.557 37.008 80.953 37.032 ;
     RECT  80.953 37.008 80.993 37.608 ;
     RECT  78.941 46.752 80.993 47.304 ;
     RECT  80.557 43.536 81.061 44.472 ;
     RECT  81.061 43.536 81.101 45 ;
     RECT  80.993 46.752 81.389 47.256 ;
     RECT  81.101 44.976 81.445 45 ;
     RECT  81.389 46.752 81.445 47.16 ;
     RECT  81.445 44.976 81.491 47.16 ;
     RECT  81.491 45.84 81.749 47.16 ;
     RECT  80.993 37.584 81.785 37.608 ;
     RECT  81.781 41.904 82.069 41.928 ;
     RECT  81.101 43.536 82.069 43.56 ;
     RECT  82.069 41.904 82.153 43.56 ;
     RECT  81.421 52.992 82.175 53.016 ;
     RECT  82.175 52.992 82.253 53.304 ;
     RECT  82.172 54.288 82.259 54.312 ;
     RECT  80.197 56.496 82.453 57.336 ;
     RECT  78.689 48.96 82.645 48.984 ;
     RECT  79.909 59.184 83.221 59.208 ;
     RECT  81.565 61.008 83.221 61.032 ;
     RECT  82.153 41.904 83.249 41.928 ;
     RECT  82.453 56.496 83.269 58.152 ;
     RECT  82.357 3.408 83.408 3.432 ;
     RECT  80.485 13.344 83.408 13.368 ;
     RECT  79.801 39.36 83.408 39.384 ;
     RECT  83.249 40.992 83.408 41.928 ;
     RECT  82.153 43.536 83.408 43.56 ;
     RECT  81.749 46.512 83.408 47.16 ;
     RECT  82.645 48.432 83.408 48.984 ;
     RECT  82.645 50.256 83.408 50.28 ;
     RECT  82.253 53.28 83.408 53.304 ;
     RECT  83.269 56.256 83.408 58.152 ;
     RECT  83.221 59.184 83.408 61.128 ;
     RECT  83.408 2.148 83.512 84.252 ;
     RECT  83.512 2.418 83.704 83.982 ;
     RECT  83.704 48.432 84.053 48.456 ;
     RECT  83.704 55.296 84.089 55.32 ;
     RECT  83.704 56.496 84.316 58.104 ;
     RECT  84.316 56.496 84.659 57.336 ;
     RECT  83.704 59.808 84.673 59.88 ;
     RECT  83.704 44.448 84.805 44.472 ;
     RECT  84.805 44.448 84.845 45 ;
     RECT  83.704 61.104 84.845 61.128 ;
     RECT  83.704 53.28 84.913 53.4 ;
     RECT  84.673 59.808 84.913 59.832 ;
     RECT  84.913 52.944 84.953 53.4 ;
     RECT  84.913 59.712 84.953 59.832 ;
     RECT  85.196 50.208 85.237 50.232 ;
     RECT  85.237 49.536 85.283 50.232 ;
     RECT  83.704 51.84 85.283 51.864 ;
     RECT  84.659 56.928 85.637 57.336 ;
     RECT  83.704 41.904 85.813 41.928 ;
     RECT  85.813 41.904 85.853 42.216 ;
     RECT  84.845 44.976 85.868 45 ;
     RECT  83.704 46.752 85.868 47.16 ;
     RECT  85.868 44.976 85.955 47.16 ;
     RECT  85.283 49.536 85.961 49.56 ;
     RECT  85.853 42.192 86.137 42.216 ;
     RECT  86.137 42.192 86.177 42.456 ;
     RECT  84.953 52.944 86.3 52.968 ;
     RECT  85.955 46.752 86.387 47.16 ;
     RECT  86.3 52.896 86.387 52.968 ;
     RECT  85.637 56.928 86.387 57.048 ;
     RECT  86.177 42.432 86.461 42.456 ;
     RECT  86.461 42.432 86.545 43.32 ;
     RECT  83.704 3.408 86.749 3.432 ;
     RECT  86.773 54.096 86.78 54.12 ;
     RECT  86.749 3.408 86.789 3.96 ;
     RECT  86.78 54 86.861 54.12 ;
     RECT  86.861 54 86.867 54.024 ;
     RECT  86.773 55.296 87.005 55.32 ;
     RECT  87.404 6.144 87.433 6.168 ;
     RECT  87.433 6 87.491 6.168 ;
     RECT  83.704 13.344 87.491 13.368 ;
     RECT  85.955 44.976 87.505 45 ;
     RECT  86.387 46.752 87.541 46.872 ;
     RECT  87.505 44.448 87.609 45 ;
     RECT  84.953 59.712 87.685 59.736 ;
     RECT  87.644 58.656 87.731 58.68 ;
     RECT  87.685 59.712 87.731 59.832 ;
     RECT  87.541 46.464 87.779 46.872 ;
     RECT  86.387 57.024 88.189 57.048 ;
     RECT  86.605 52.992 88.333 53.016 ;
     RECT  86.965 47.856 88.412 47.88 ;
     RECT  88.412 47.856 88.453 48.408 ;
     RECT  86.789 3.936 88.513 3.96 ;
     RECT  88.513 3.408 88.808 3.96 ;
     RECT  87.491 6 88.808 6.024 ;
     RECT  87.445 14.928 88.808 14.952 ;
     RECT  86.545 42.432 88.808 42.456 ;
     RECT  87.609 44.448 88.808 44.472 ;
     RECT  87.779 46.848 88.808 46.872 ;
     RECT  88.453 47.856 88.808 49.032 ;
     RECT  88.021 51.936 88.808 51.96 ;
     RECT  88.333 52.992 88.808 53.592 ;
     RECT  87.397 55.92 88.808 55.944 ;
     RECT  88.189 57.024 88.808 57.096 ;
     RECT  87.731 59.808 88.808 59.832 ;
     RECT  88.549 60.816 88.808 60.84 ;
     RECT  88.808 2.148 88.912 84.252 ;
     RECT  88.912 2.418 89.104 83.982 ;
     RECT  89.104 49.008 89.237 49.416 ;
     RECT  89.104 57.024 89.309 58.152 ;
     RECT  89.104 53.568 89.597 53.592 ;
     RECT  89.104 42.432 90.092 42.456 ;
     RECT  89.104 3.408 90.173 3.432 ;
     RECT  89.104 6 90.179 6.024 ;
     RECT  90.092 42.144 90.179 42.456 ;
     RECT  89.104 46.752 90.205 46.968 ;
     RECT  90.205 46.752 90.613 47.256 ;
     RECT  90.613 46.128 90.7 47.256 ;
     RECT  89.237 49.392 90.956 49.416 ;
     RECT  90.956 49.392 90.997 50.28 ;
     RECT  90.7 46.752 91.043 47.256 ;
     RECT  90.997 48.432 91.043 50.28 ;
     RECT  89.309 58.128 91.381 58.152 ;
     RECT  91.381 58.128 91.427 58.68 ;
     RECT  89.104 51.936 91.433 51.96 ;
     RECT  91.349 59.856 91.433 59.88 ;
     RECT  91.532 51.888 91.573 51.912 ;
     RECT  91.573 51.264 91.619 51.912 ;
     RECT  91.619 51.264 92.009 51.288 ;
     RECT  91.789 55.008 92.303 55.032 ;
     RECT  92.303 55.008 92.387 55.56 ;
     RECT  91.043 46.752 92.396 46.872 ;
     RECT  91.043 48.432 92.396 48.456 ;
     RECT  92.396 46.752 92.483 48.456 ;
     RECT  53.521 0.096 92.485 0.12 ;
     RECT  91.427 58.656 92.581 58.68 ;
     RECT  92.341 53.568 92.621 53.592 ;
     RECT  92.581 58.128 92.621 58.68 ;
     RECT  89.309 57.024 92.828 57.048 ;
     RECT  92.828 56.688 92.915 57.048 ;
     RECT  92.915 57.024 92.973 57.048 ;
     RECT  92.483 46.752 93.089 46.968 ;
     RECT  92.387 55.536 93.397 55.56 ;
     RECT  89.104 14.928 93.884 14.952 ;
     RECT  92.483 48.432 94.021 48.456 ;
     RECT  93.949 50.16 94.021 50.184 ;
     RECT  93.884 14.928 94.208 15.048 ;
     RECT  93.925 17.952 94.208 17.976 ;
     RECT  90.179 42.432 94.208 42.456 ;
     RECT  93.089 46.944 94.208 46.968 ;
     RECT  94.021 48.432 94.208 50.184 ;
     RECT  93.397 55.536 94.208 55.992 ;
     RECT  92.621 58.128 94.208 58.152 ;
     RECT  94.069 59.28 94.208 59.304 ;
     RECT  94.208 2.148 94.312 84.252 ;
     RECT  94.312 2.418 94.504 83.982 ;
     RECT  94.504 55.536 94.565 55.992 ;
     RECT  94.565 55.968 95.785 55.992 ;
     RECT  95.497 52.464 96.437 52.488 ;
     RECT  94.504 54.48 97.292 54.504 ;
     RECT  97.292 53.568 97.379 54.504 ;
     RECT  95.785 55.968 97.429 56.664 ;
     RECT  97.429 55.968 97.475 57.576 ;
     RECT  97.475 57.552 97.517 57.576 ;
     RECT  94.504 17.952 97.733 17.976 ;
     RECT  97.475 55.968 97.733 56.424 ;
     RECT  97.733 55.968 98.017 55.992 ;
     RECT  97.379 54.48 98.809 54.504 ;
     RECT  98.017 55.872 98.809 55.992 ;
     RECT  98.809 54.48 99.061 55.992 ;
     RECT  94.504 42.432 99.608 42.456 ;
     RECT  99.061 54.48 99.608 56.424 ;
     RECT  99.061 57.6 99.608 57.624 ;
     RECT  99.02 59.424 99.608 59.448 ;
     RECT  99.608 2.148 99.712 84.252 ;
     RECT  99.712 2.418 99.904 83.982 ;
     RECT  99.904 57.6 100.973 57.624 ;
     RECT  100.969 59.232 102.613 59.256 ;
     RECT  102.613 59.232 102.659 59.784 ;
     RECT  101.761 21.264 104.869 21.288 ;
     RECT  104.869 19.632 105.008 21.288 ;
     RECT  99.904 42.432 105.008 42.456 ;
     RECT  99.904 55.968 105.008 55.992 ;
     RECT  102.659 59.76 105.008 59.784 ;
     RECT  105.008 2.148 105.112 84.252 ;
     RECT  105.112 2.418 105.304 83.982 ;
     RECT  105.304 20.592 110.408 20.616 ;
     RECT  110.293 23.28 110.408 23.304 ;
     RECT  105.304 42.432 110.408 42.456 ;
     RECT  105.304 55.968 110.408 55.992 ;
     RECT  105.304 59.76 110.408 59.784 ;
     RECT  110.408 2.148 110.512 84.252 ;
     RECT  110.512 2.418 110.704 83.982 ;
     RECT  110.704 23.28 115.808 23.304 ;
     RECT  110.704 42.432 115.808 42.456 ;
     RECT  110.704 55.968 115.808 55.992 ;
     RECT  110.704 59.76 115.808 59.784 ;
     RECT  115.808 2.148 115.912 84.252 ;
     RECT  115.912 2.418 116.104 83.982 ;
     RECT  116.104 24.336 117.421 25.128 ;
     RECT  117.421 24.336 117.461 25.512 ;
     RECT  117.461 24.336 118.573 24.36 ;
     RECT  118.573 24.336 118.613 24.456 ;
     RECT  119.66 57.024 120.229 57.048 ;
     RECT  116.104 55.968 120.332 55.992 ;
     RECT  120.229 57.024 120.332 57.24 ;
     RECT  118.613 24.432 121.208 24.456 ;
     RECT  117.461 25.488 121.208 25.512 ;
     RECT  121.093 27.168 121.208 27.192 ;
     RECT  121.093 28.176 121.208 28.2 ;
     RECT  116.104 42.432 121.208 42.456 ;
     RECT  120.332 55.968 121.208 57.24 ;
     RECT  116.104 59.76 121.208 59.784 ;
     RECT  121.208 2.148 121.312 84.252 ;
     RECT  121.312 2.418 121.504 83.982 ;
     RECT  121.504 46.128 121.889 46.152 ;
     RECT  121.504 30.864 122.003 31.944 ;
     RECT  121.504 27.168 122.033 27.336 ;
     RECT  122.003 30.864 122.213 30.984 ;
     RECT  121.504 38.928 122.677 38.952 ;
     RECT  121.504 57.024 122.869 57.048 ;
     RECT  122.869 57.024 122.893 57.816 ;
     RECT  122.636 59.232 122.963 59.256 ;
     RECT  122.893 57.024 122.977 57.96 ;
     RECT  123.217 34.848 123.349 34.872 ;
     RECT  121.504 35.856 123.349 35.88 ;
     RECT  121.504 47.664 123.356 47.688 ;
     RECT  121.504 24.432 123.395 24.456 ;
     RECT  121.504 55.968 123.443 55.992 ;
     RECT  123.356 47.28 123.509 47.688 ;
     RECT  123.349 34.848 123.685 35.88 ;
     RECT  122.677 38.112 123.685 38.952 ;
     RECT  121.504 52.752 123.685 52.776 ;
     RECT  123.325 54.288 123.685 54.312 ;
     RECT  123.685 37.44 123.731 39.768 ;
     RECT  123.685 52.752 123.731 54.312 ;
     RECT  123.685 34.848 123.769 36.456 ;
     RECT  123.685 55.392 123.772 55.416 ;
     RECT  123.731 52.752 123.797 53.592 ;
     RECT  122.677 44.832 123.829 44.856 ;
     RECT  123.509 47.28 123.877 47.352 ;
     RECT  123.829 44.4 123.923 44.856 ;
     RECT  122.213 30.864 123.925 30.888 ;
     RECT  123.925 30.432 123.971 30.888 ;
     RECT  123.769 34.848 123.971 35.88 ;
     RECT  123.925 33.024 124.012 33.816 ;
     RECT  123.971 35.664 124.013 35.88 ;
     RECT  122.033 27.312 124.021 27.336 ;
     RECT  124.021 26.736 124.067 27.336 ;
     RECT  124.067 26.736 124.081 26.76 ;
     RECT  124.081 26.208 124.121 26.76 ;
     RECT  122.977 57.024 124.193 57.048 ;
     RECT  124.009 41.376 124.213 41.4 ;
     RECT  123.877 46.752 124.229 47.352 ;
     RECT  123.731 39.744 124.259 39.768 ;
     RECT  124.213 40.8 124.259 41.4 ;
     RECT  124.213 29.376 124.3 29.4 ;
     RECT  123.877 43.296 124.373 43.32 ;
     RECT  123.731 37.44 124.625 37.464 ;
     RECT  124.259 40.8 124.697 40.824 ;
     RECT  123.971 30.432 124.733 30.456 ;
     RECT  124.229 47.328 124.837 47.352 ;
     RECT  124.297 50.736 124.837 50.76 ;
     RECT  124.837 50.112 124.883 50.76 ;
     RECT  124.883 50.112 124.924 50.136 ;
     RECT  124.121 26.208 124.949 26.232 ;
     RECT  124.012 33.024 124.949 33.048 ;
     RECT  122.677 60.432 124.949 60.456 ;
     RECT  124.837 47.328 125.057 47.736 ;
     RECT  124.013 35.856 125.453 35.88 ;
     RECT  126.608 2.148 126.712 84.252 ;
     RECT  126.712 2.418 126.904 83.982 ;
     RECT  126.904 38.64 127.289 38.664 ;
     RECT  128.257 46.656 128.797 46.68 ;
     RECT  128.221 55.296 128.797 55.32 ;
     RECT  128.797 32.832 128.833 32.856 ;
     RECT  128.797 34.56 128.833 38.04 ;
     RECT  128.797 39.744 128.833 47.544 ;
     RECT  128.797 25.92 129.481 26.808 ;
     RECT  128.797 28.512 129.481 29.4 ;
     RECT  128.797 31.104 129.481 31.128 ;
     RECT  128.833 32.832 129.481 47.544 ;
     RECT  128.797 49.248 129.481 52.728 ;
     RECT  128.797 54.432 129.481 60.504 ;
     RECT  129.481 25.92 129.564 60.504 ;
    LAYER M5 ;
     RECT  37.152 0.016 92.472 0.131 ;
     RECT  43.2 0.131 43.224 1.763 ;
     RECT  44.928 0.131 44.952 1.763 ;
     RECT  51.84 0.131 52.728 1.763 ;
     RECT  2.4 2.137 2.52 2.151 ;
     RECT  7.8 2.137 7.92 2.151 ;
     RECT  13.2 2.137 13.32 2.151 ;
     RECT  18.6 2.137 18.72 2.151 ;
     RECT  24 2.137 24.12 2.151 ;
     RECT  29.4 2.137 29.52 2.151 ;
     RECT  34.8 2.137 34.92 2.151 ;
     RECT  40.2 2.137 40.32 2.151 ;
     RECT  45.6 2.137 45.72 2.151 ;
     RECT  56.4 2.137 56.52 2.151 ;
     RECT  61.8 2.137 61.92 2.151 ;
     RECT  67.2 2.137 67.32 2.151 ;
     RECT  72.6 2.137 72.72 2.151 ;
     RECT  78 2.137 78.12 2.151 ;
     RECT  83.4 2.137 83.52 2.151 ;
     RECT  88.8 2.137 88.92 2.151 ;
     RECT  94.2 2.137 94.32 2.151 ;
     RECT  99.6 2.137 99.72 2.151 ;
     RECT  105 2.137 105.12 2.151 ;
     RECT  110.4 2.137 110.52 2.151 ;
     RECT  115.8 2.137 115.92 2.151 ;
     RECT  121.2 2.137 121.32 2.151 ;
     RECT  126.6 2.137 126.72 2.151 ;
     RECT  51 2.137 51.312 2.821 ;
     RECT  72.6 2.151 72.912 2.821 ;
     RECT  56.4 2.151 56.712 3.157 ;
     RECT  71.76 2.821 72.912 3.397 ;
     RECT  51 2.821 51.912 3.443 ;
     RECT  71.76 3.397 73.032 3.683 ;
     RECT  59.808 3.637 59.832 3.829 ;
     RECT  72.6 3.683 73.032 3.875 ;
     RECT  56.4 3.157 57.144 3.971 ;
     RECT  43.248 3.397 43.272 4.115 ;
     RECT  76.8 3.397 76.824 4.115 ;
     RECT  59.712 3.829 59.832 4.117 ;
     RECT  40.2 2.151 40.512 6.229 ;
     RECT  42.192 3.397 42.216 6.469 ;
     RECT  41.808 6.469 42.216 6.515 ;
     RECT  59.664 4.117 59.832 6.851 ;
     RECT  53.712 3.925 53.736 7.333 ;
     RECT  53.712 7.333 54.024 7.379 ;
     RECT  54 7.379 54.024 8.243 ;
     RECT  40.2 6.229 40.776 8.437 ;
     RECT  41.808 6.515 41.832 8.437 ;
     RECT  40.2 8.437 41.832 8.483 ;
     RECT  59.76 6.851 59.832 10.979 ;
     RECT  40.2 8.483 41.736 11.267 ;
     RECT  61.8 2.151 62.112 11.365 ;
     RECT  87.456 3.925 87.48 14.963 ;
     RECT  94.2 2.151 94.512 15.013 ;
     RECT  51 3.443 51.312 15.829 ;
     RECT  65.184 3.301 65.208 17.269 ;
     RECT  65.184 17.269 65.544 17.315 ;
     RECT  93.936 15.013 94.512 17.987 ;
     RECT  65.52 17.315 65.544 18.419 ;
     RECT  67.2 2.151 67.512 18.709 ;
     RECT  50.88 15.829 51.312 18.755 ;
     RECT  45.6 2.151 45.912 18.757 ;
     RECT  105 2.151 105.312 19.621 ;
     RECT  40.2 11.267 40.776 20.149 ;
     RECT  110.4 2.151 110.712 20.581 ;
     RECT  49.824 18.709 49.848 21.109 ;
     RECT  44.976 18.757 45.912 21.203 ;
     RECT  40.2 20.149 41.688 21.299 ;
     RECT  104.88 19.621 105.312 21.299 ;
     RECT  49.824 21.109 49.992 21.779 ;
     RECT  59.76 10.979 59.784 22.453 ;
     RECT  59.04 22.453 59.784 22.499 ;
     RECT  61.68 11.365 62.112 22.787 ;
     RECT  38.736 21.637 38.76 22.981 ;
     RECT  110.304 20.581 110.712 23.315 ;
     RECT  40.2 21.299 41.592 23.411 ;
     RECT  38.688 22.981 38.76 23.987 ;
     RECT  38.736 23.987 38.76 24.083 ;
     RECT  56.4 3.971 56.712 24.085 ;
     RECT  7.8 2.151 8.112 24.469 ;
     RECT  32.784 15.061 32.808 24.947 ;
     RECT  67.2 18.709 67.704 25.043 ;
     RECT  121.2 2.151 121.512 25.477 ;
     RECT  34.8 2.151 35.112 25.621 ;
     RECT  34.8 25.621 35.928 26.245 ;
     RECT  4.512 22.741 4.536 26.291 ;
     RECT  34.8 26.245 36.168 26.291 ;
     RECT  56.4 24.085 57 26.531 ;
     RECT  123.36 24.421 123.384 26.725 ;
     RECT  123.36 26.725 124.056 27.347 ;
     RECT  6.912 24.469 8.112 27.395 ;
     RECT  60.624 24.469 60.648 27.635 ;
     RECT  121.104 25.477 121.512 28.211 ;
     RECT  67.2 25.043 67.608 28.979 ;
     RECT  5.136 27.301 5.16 29.219 ;
     RECT  123.36 27.347 123.384 29.365 ;
     RECT  123.36 29.365 124.248 30.467 ;
     RECT  49.968 21.779 49.992 30.563 ;
     RECT  69.984 29.221 70.008 30.563 ;
     RECT  45.6 21.203 45.912 30.709 ;
     RECT  40.2 23.411 40.776 30.805 ;
     RECT  40.2 30.805 40.872 30.947 ;
     RECT  59.04 22.499 59.064 30.949 ;
     RECT  121.2 28.211 121.512 30.949 ;
     RECT  54.624 30.757 54.648 30.995 ;
     RECT  58.944 30.949 59.064 30.995 ;
     RECT  72.6 3.875 72.912 31.285 ;
     RECT  121.2 30.949 121.992 31.955 ;
     RECT  78 2.151 78.312 34.165 ;
     RECT  72.6 31.285 73.32 34.741 ;
     RECT  76.032 33.349 76.056 34.835 ;
     RECT  69.024 34.741 69.048 34.931 ;
     RECT  45.6 30.709 46.008 35.171 ;
     RECT  72.6 34.741 73.464 35.171 ;
     RECT  53.04 24.085 53.064 35.317 ;
     RECT  61.8 22.787 62.112 35.317 ;
     RECT  52.8 35.317 53.064 35.363 ;
     RECT  78 34.165 79.224 35.363 ;
     RECT  36.144 26.291 36.168 35.459 ;
     RECT  123.36 30.467 123.96 35.651 ;
     RECT  123.408 35.651 123.96 35.699 ;
     RECT  56.4 26.531 56.712 36.229 ;
     RECT  52.8 35.363 52.824 36.275 ;
     RECT  67.2 28.979 67.512 36.325 ;
     RECT  70.704 35.845 70.728 36.515 ;
     RECT  58.944 30.995 58.968 36.517 ;
     RECT  4.656 31.765 4.68 36.803 ;
     RECT  58.656 36.517 58.968 36.851 ;
     RECT  61.8 35.317 62.76 37.091 ;
     RECT  67.2 36.325 67.8 37.091 ;
     RECT  40.2 30.947 40.728 37.187 ;
     RECT  9.456 25.045 9.48 37.285 ;
     RECT  29.4 2.151 29.712 37.285 ;
     RECT  9.12 37.285 9.48 37.331 ;
     RECT  9.12 37.331 9.144 37.619 ;
     RECT  76.752 36.517 76.776 37.619 ;
     RECT  78 35.363 78.696 37.667 ;
     RECT  64.848 36.421 64.872 37.859 ;
     RECT  56.064 36.229 56.712 38.147 ;
     RECT  5.088 37.573 5.112 38.197 ;
     RECT  56.304 38.147 56.712 39.251 ;
     RECT  58.944 36.851 58.968 39.253 ;
     RECT  61.8 37.091 62.328 39.253 ;
     RECT  65.952 30.853 65.976 39.301 ;
     RECT  67.2 37.091 67.512 39.301 ;
     RECT  123.408 35.699 123.72 39.733 ;
     RECT  72.6 35.171 72.912 39.877 ;
     RECT  58.944 39.253 59.016 40.019 ;
     RECT  61.8 39.253 62.52 40.019 ;
     RECT  70.464 39.301 70.488 40.261 ;
     RECT  70.128 40.261 70.488 40.307 ;
     RECT  72.6 39.877 73.512 40.451 ;
     RECT  83.4 2.151 83.712 40.981 ;
     RECT  65.952 39.301 67.512 41.077 ;
     RECT  65.52 41.077 67.512 41.123 ;
     RECT  75.6 40.741 75.624 41.221 ;
     RECT  75.6 41.221 76.392 41.267 ;
     RECT  123.408 39.733 124.248 41.411 ;
     RECT  65.52 41.123 65.976 41.651 ;
     RECT  70.128 40.307 70.152 41.747 ;
     RECT  72.6 40.451 73.032 41.795 ;
     RECT  83.28 40.981 83.712 41.939 ;
     RECT  72.6 41.795 72.912 42.085 ;
     RECT  61.8 40.019 62.112 42.133 ;
     RECT  65.952 41.651 65.976 42.469 ;
     RECT  67.2 41.123 67.512 42.469 ;
     RECT  4.368 38.197 5.112 42.803 ;
     RECT  65.952 42.469 67.512 42.803 ;
     RECT  76.368 41.267 76.392 42.803 ;
     RECT  82.08 41.893 82.104 42.803 ;
     RECT  123.408 41.411 123.432 43.285 ;
     RECT  29.4 37.285 29.88 43.955 ;
     RECT  61.248 42.133 62.112 44.099 ;
     RECT  5.088 42.803 5.112 44.341 ;
     RECT  65.952 42.803 65.976 44.437 ;
     RECT  67.2 42.803 67.512 44.965 ;
     RECT  86.496 43.285 86.52 44.965 ;
     RECT  85.92 44.965 86.52 45.011 ;
     RECT  75.408 44.437 75.432 45.395 ;
     RECT  65.664 44.437 65.976 45.443 ;
     RECT  85.92 45.011 85.944 45.971 ;
     RECT  90.144 5.989 90.168 46.117 ;
     RECT  121.2 31.955 121.512 46.117 ;
     RECT  5.088 44.341 5.688 46.211 ;
     RECT  87.552 44.965 87.576 46.453 ;
     RECT  87.552 46.453 87.768 46.499 ;
     RECT  123.408 43.285 123.912 46.787 ;
     RECT  65.952 45.443 65.976 46.883 ;
     RECT  81.456 44.965 81.48 46.883 ;
     RECT  94.2 17.987 94.512 46.933 ;
     RECT  90.144 46.117 90.648 46.979 ;
     RECT  5.088 46.211 5.112 47.269 ;
     RECT  72.432 42.085 72.912 47.269 ;
     RECT  67.2 44.965 67.608 47.315 ;
     RECT  78 37.667 78.648 47.315 ;
     RECT  121.2 46.117 121.656 47.699 ;
     RECT  93.408 46.933 94.512 47.749 ;
     RECT  87.744 46.499 87.768 47.891 ;
     RECT  72.432 47.269 73.56 47.939 ;
     RECT  88.8 2.151 89.112 48.373 ;
     RECT  83.4 41.939 83.712 48.421 ;
     RECT  92.448 47.749 94.512 48.467 ;
     RECT  5.088 47.269 5.736 48.805 ;
     RECT  78 47.315 78.312 48.997 ;
     RECT  88.464 48.373 89.112 49.043 ;
     RECT  5.088 48.805 5.976 49.573 ;
     RECT  4.944 49.573 5.976 49.619 ;
     RECT  82.656 48.421 83.712 50.291 ;
     RECT  91.008 47.221 91.032 50.291 ;
     RECT  124.848 47.701 124.872 50.771 ;
     RECT  4.944 49.619 5.112 51.347 ;
     RECT  78 48.997 78.408 51.347 ;
     RECT  70.128 48.421 70.152 51.395 ;
     RECT  72.6 47.939 72.912 51.637 ;
     RECT  74.976 50.677 75 51.683 ;
     RECT  85.248 49.525 85.272 51.875 ;
     RECT  5.088 51.347 5.112 51.923 ;
     RECT  91.584 51.253 91.608 51.923 ;
     RECT  88.8 49.043 89.112 51.925 ;
     RECT  71.76 51.637 72.912 52.739 ;
     RECT  78 51.347 78.312 52.885 ;
     RECT  86.352 46.837 86.376 52.981 ;
     RECT  88.032 51.925 89.112 53.027 ;
     RECT  83.4 50.291 83.712 53.269 ;
     RECT  72.6 52.739 72.912 53.557 ;
     RECT  123.408 46.787 123.432 53.557 ;
     RECT  86.352 52.981 86.856 54.035 ;
     RECT  72.6 53.557 73.512 54.323 ;
     RECT  82.224 53.269 82.248 54.323 ;
     RECT  77.52 52.885 78.312 54.419 ;
     RECT  78 54.419 78.312 54.469 ;
     RECT  99.6 2.151 99.912 54.469 ;
     RECT  97.344 53.557 97.368 54.515 ;
     RECT  2.4 2.151 2.712 54.613 ;
     RECT  4.56 52.405 4.584 54.613 ;
     RECT  2.4 54.613 4.584 54.755 ;
     RECT  78 54.469 78.696 55.331 ;
     RECT  83.4 53.269 84.072 55.331 ;
     RECT  86.352 54.035 86.808 55.331 ;
     RECT  98.832 54.469 99.912 55.331 ;
     RECT  76.176 54.373 76.2 55.525 ;
     RECT  92.352 53.557 92.376 55.525 ;
     RECT  93.408 48.467 94.512 55.525 ;
     RECT  76.08 55.525 76.2 55.571 ;
     RECT  92.352 55.525 94.512 55.571 ;
     RECT  88.608 53.027 89.112 55.909 ;
     RECT  92.88 55.571 94.512 56.003 ;
     RECT  123.408 53.557 123.72 56.003 ;
     RECT  83.4 55.331 83.712 56.245 ;
     RECT  119.712 55.957 119.736 56.341 ;
     RECT  121.2 47.699 121.512 56.341 ;
     RECT  83.28 56.245 83.712 56.485 ;
     RECT  76.08 55.571 76.104 57.011 ;
     RECT  123.696 56.003 123.72 57.013 ;
     RECT  2.4 54.755 3.672 57.059 ;
     RECT  86.352 55.331 86.376 57.059 ;
     RECT  119.712 56.341 121.512 57.059 ;
     RECT  122.88 57.013 123.72 57.059 ;
     RECT  88.368 55.909 89.112 57.061 ;
     RECT  88.368 57.061 89.256 57.107 ;
     RECT  80.208 56.677 80.232 57.347 ;
     RECT  97.44 56.389 97.464 57.587 ;
     RECT  122.88 57.059 122.952 57.827 ;
     RECT  88.8 57.107 89.256 57.875 ;
     RECT  83.28 56.485 84.648 58.117 ;
     RECT  94.2 56.003 94.512 58.117 ;
     RECT  92.88 56.003 92.904 58.163 ;
     RECT  82.464 58.117 84.648 59.219 ;
     RECT  122.928 57.827 122.952 59.221 ;
     RECT  122.688 59.221 122.952 59.267 ;
     RECT  94.08 58.117 94.512 59.315 ;
     RECT  99.072 55.331 99.912 59.459 ;
     RECT  102.624 59.221 102.648 59.795 ;
     RECT  120.384 57.059 121.512 59.795 ;
     RECT  87.696 58.645 87.72 59.797 ;
     RECT  88.8 57.875 89.112 59.797 ;
     RECT  87.696 59.797 89.112 59.843 ;
     RECT  76.896 58.117 76.92 59.891 ;
     RECT  83.232 59.219 84.648 59.891 ;
     RECT  91.392 58.117 91.416 59.891 ;
     RECT  122.688 59.267 122.712 60.467 ;
     RECT  88.56 59.843 89.112 60.851 ;
     RECT  83.232 59.891 83.712 61.139 ;
     RECT  71.568 56.485 71.592 81.539 ;
     RECT  58.944 40.019 58.968 82.021 ;
     RECT  67.2 47.315 67.512 82.021 ;
     RECT  72.6 54.323 72.912 82.021 ;
     RECT  66.528 82.021 67.512 82.643 ;
     RECT  70.032 82.021 70.056 82.643 ;
     RECT  52.752 82.021 52.776 82.691 ;
     RECT  58.944 82.021 59.592 82.691 ;
     RECT  72.6 82.021 73.368 82.691 ;
     RECT  59.568 82.691 59.592 82.787 ;
     RECT  66.96 82.643 67.512 83.267 ;
     RECT  51 18.755 51.312 83.797 ;
     RECT  2.4 57.059 2.712 84.249 ;
     RECT  7.8 27.395 8.112 84.249 ;
     RECT  13.2 2.151 13.512 84.249 ;
     RECT  18.6 2.151 18.912 84.249 ;
     RECT  24 2.151 24.312 84.249 ;
     RECT  29.4 43.955 29.712 84.249 ;
     RECT  34.8 26.291 35.112 84.249 ;
     RECT  40.2 37.187 40.512 84.249 ;
     RECT  45.6 35.171 45.912 84.249 ;
     RECT  56.4 39.251 56.712 84.249 ;
     RECT  61.8 44.099 62.112 84.249 ;
     RECT  67.2 83.267 67.512 84.249 ;
     RECT  78 55.331 78.312 84.249 ;
     RECT  83.4 61.139 83.712 84.249 ;
     RECT  88.8 60.851 89.112 84.249 ;
     RECT  94.2 59.315 94.512 84.249 ;
     RECT  99.6 59.459 99.912 84.249 ;
     RECT  105 21.299 105.312 84.249 ;
     RECT  110.4 23.315 110.712 84.249 ;
     RECT  115.8 2.151 116.112 84.249 ;
     RECT  121.2 59.795 121.512 84.249 ;
     RECT  126.6 2.151 126.912 84.249 ;
     RECT  2.4 84.249 2.52 84.263 ;
     RECT  7.8 84.249 7.92 84.263 ;
     RECT  13.2 84.249 13.32 84.263 ;
     RECT  18.6 84.249 18.72 84.263 ;
     RECT  24 84.249 24.12 84.263 ;
     RECT  29.4 84.249 29.52 84.263 ;
     RECT  34.8 84.249 34.92 84.263 ;
     RECT  40.2 84.249 40.32 84.263 ;
     RECT  45.6 84.249 45.72 84.263 ;
     RECT  56.4 84.249 56.616 84.263 ;
     RECT  61.8 84.249 61.92 84.263 ;
     RECT  67.2 84.249 67.32 84.263 ;
     RECT  83.4 84.249 83.52 84.263 ;
     RECT  88.8 84.249 88.92 84.263 ;
     RECT  94.2 84.249 94.32 84.263 ;
     RECT  99.6 84.249 99.72 84.263 ;
     RECT  105 84.249 105.12 84.263 ;
     RECT  110.4 84.249 110.52 84.263 ;
     RECT  115.8 84.249 115.92 84.263 ;
     RECT  121.2 84.249 121.32 84.263 ;
     RECT  126.6 84.249 126.72 84.263 ;
     RECT  50.544 83.797 51.312 84.901 ;
     RECT  54 84.325 54.024 84.901 ;
     RECT  72.6 82.691 72.912 84.901 ;
     RECT  78 84.249 78.216 84.901 ;
     RECT  68.688 84.901 68.712 85.477 ;
     RECT  63.504 84.901 63.528 86.005 ;
     RECT  65.232 84.901 65.256 86.005 ;
     RECT  50.544 84.901 52.296 86.245 ;
     RECT  54 84.901 54.888 86.245 ;
     RECT  56.592 84.263 56.616 86.245 ;
     RECT  58.32 84.901 58.344 86.245 ;
     RECT  60.048 84.901 60.072 86.245 ;
     RECT  61.776 84.901 61.8 86.245 ;
     RECT  63.504 86.005 65.256 86.245 ;
     RECT  67.824 85.477 68.712 86.245 ;
     RECT  70.416 84.901 73.032 86.245 ;
     RECT  74.736 84.901 75.624 86.245 ;
     RECT  77.328 84.901 78.216 86.245 ;
     RECT  50.544 86.245 79.08 86.352 ;
     RECT  51.84 1.763 51.912 2.137 ;
     RECT  51.312 2.137 51.912 2.821 ;
     RECT  42.216 3.397 43.248 4.115 ;
     RECT  76.824 3.397 78 4.115 ;
     RECT  87.48 3.925 88.8 14.963 ;
     RECT  89.112 5.989 90.144 46.979 ;
     RECT  40.776 6.229 42.192 6.469 ;
     RECT  40.776 6.469 41.808 8.437 ;
     RECT  49.848 18.709 50.88 18.755 ;
     RECT  49.848 18.755 51 21.109 ;
     RECT  49.992 21.109 51 30.563 ;
     RECT  38.76 21.637 40.2 24.083 ;
     RECT  60.648 24.469 61.8 27.635 ;
     RECT  8.112 25.045 9.456 37.285 ;
     RECT  35.112 26.291 36.144 35.459 ;
     RECT  65.976 30.853 67.2 39.301 ;
     RECT  121.992 30.949 123.36 31.955 ;
     RECT  67.512 34.741 69.024 34.931 ;
     RECT  67.512 34.931 67.8 36.325 ;
     RECT  51.312 35.317 52.8 36.275 ;
     RECT  64.872 36.421 65.952 37.859 ;
     RECT  76.776 36.517 78 37.619 ;
     RECT  4.656 36.803 4.68 37.573 ;
     RECT  8.112 37.285 9.12 37.619 ;
     RECT  4.656 37.573 5.088 38.197 ;
     RECT  65.976 41.123 67.2 42.469 ;
     RECT  82.104 41.893 83.28 41.939 ;
     RECT  82.104 41.939 83.4 42.803 ;
     RECT  65.976 42.803 67.2 46.883 ;
     RECT  86.52 44.965 87.552 45.011 ;
     RECT  87.576 44.965 88.8 46.453 ;
     RECT  5.112 46.211 5.688 47.269 ;
     RECT  87.768 46.453 88.8 47.891 ;
     RECT  87.552 46.499 87.744 46.837 ;
     RECT  123.432 46.787 123.912 47.701 ;
     RECT  86.376 46.837 87.744 47.891 ;
     RECT  123.432 47.701 124.848 50.771 ;
     RECT  91.032 47.749 92.448 48.467 ;
     RECT  88.464 47.891 88.8 48.373 ;
     RECT  85.272 49.525 86.352 51.875 ;
     RECT  86.856 52.981 88.032 53.027 ;
     RECT  82.248 53.269 83.4 54.323 ;
     RECT  92.376 53.557 93.408 55.525 ;
     RECT  76.2 54.373 77.52 54.419 ;
     RECT  97.368 54.469 98.832 54.515 ;
     RECT  83.712 55.331 84.072 56.485 ;
     RECT  119.736 55.957 121.2 56.341 ;
     RECT  92.904 56.003 94.2 58.117 ;
     RECT  123.408 56.003 123.696 57.013 ;
     RECT  71.592 56.485 72.6 81.539 ;
     RECT  121.512 57.013 122.88 57.827 ;
     RECT  121.512 57.827 122.928 59.221 ;
     RECT  76.92 58.117 78 59.891 ;
     RECT  91.416 58.117 92.88 58.163 ;
     RECT  92.904 58.117 94.08 58.163 ;
     RECT  87.72 58.645 88.8 59.797 ;
     RECT  121.512 59.221 122.688 60.467 ;
     RECT  51.312 82.021 52.752 82.691 ;
  END
END ot_hgi_hc_bank_control_static
END LIBRARY
